VERSION 5.8 ;
DIVIDERCHAR "/" ;
BUSBITCHARS "[]" ;

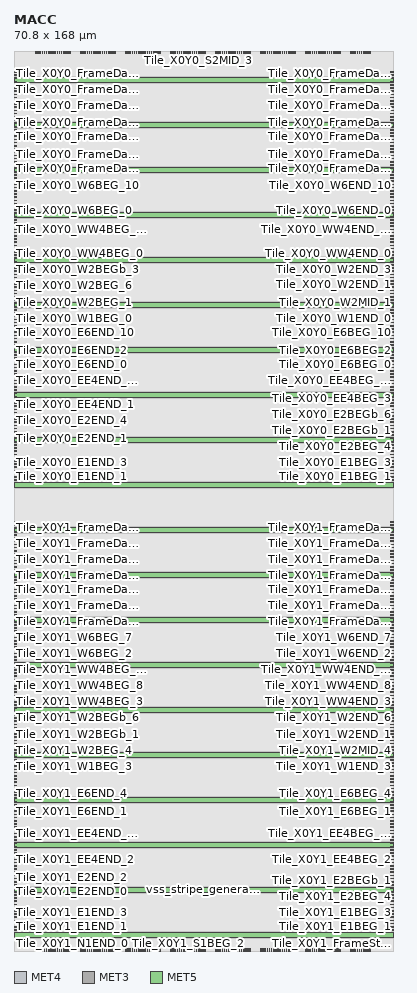
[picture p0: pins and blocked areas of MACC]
MACRO MACC
  CLASS BLOCK ;
  FOREIGN MACC ;
  ORIGIN 0.0 0.0 ;
  SIZE 70.800 BY 168.000 ;
  SYMMETRY X Y ;
  PIN Tile_X0Y0_N_GBUF_BEG_0
    DIRECTION OUTPUT ;
    USE SIGNAL ;
    PORT
      LAYER MET4 ;
        RECT 4.050 167.450 4.150 168.000 ;
    END
  END Tile_X0Y0_N_GBUF_BEG_0
  PIN Tile_X0Y0_N_GBUF_BEG_1
    DIRECTION OUTPUT ;
    USE SIGNAL ;
    PORT
      LAYER MET4 ;
        RECT 4.450 167.450 4.550 168.000 ;
    END
  END Tile_X0Y0_N_GBUF_BEG_1
  PIN Tile_X0Y0_N_GBUF_BEG_2
    DIRECTION OUTPUT ;
    USE SIGNAL ;
    PORT
      LAYER MET4 ;
        RECT 4.850 167.450 4.950 168.000 ;
    END
  END Tile_X0Y0_N_GBUF_BEG_2
  PIN Tile_X0Y0_N_GBUF_BEG_3
    DIRECTION OUTPUT ;
    USE SIGNAL ;
    PORT
      LAYER MET4 ;
        RECT 5.250 167.450 5.350 168.000 ;
    END
  END Tile_X0Y0_N_GBUF_BEG_3
  PIN Tile_X0Y0_N1BEG_0
    DIRECTION OUTPUT ;
    USE SIGNAL ;
    PORT
      LAYER MET4 ;
        RECT 5.650 167.450 5.750 168.000 ;
    END
  END Tile_X0Y0_N1BEG_0
  PIN Tile_X0Y0_N1BEG_1
    DIRECTION OUTPUT ;
    USE SIGNAL ;
    PORT
      LAYER MET4 ;
        RECT 6.050 167.450 6.150 168.000 ;
    END
  END Tile_X0Y0_N1BEG_1
  PIN Tile_X0Y0_N1BEG_2
    DIRECTION OUTPUT ;
    USE SIGNAL ;
    PORT
      LAYER MET4 ;
        RECT 6.450 167.450 6.550 168.000 ;
    END
  END Tile_X0Y0_N1BEG_2
  PIN Tile_X0Y0_N1BEG_3
    DIRECTION OUTPUT ;
    USE SIGNAL ;
    PORT
      LAYER MET4 ;
        RECT 6.850 167.450 6.950 168.000 ;
    END
  END Tile_X0Y0_N1BEG_3
  PIN Tile_X0Y0_N2BEG_0
    DIRECTION OUTPUT ;
    USE SIGNAL ;
    PORT
      LAYER MET4 ;
        RECT 7.250 167.450 7.350 168.000 ;
    END
  END Tile_X0Y0_N2BEG_0
  PIN Tile_X0Y0_N2BEG_1
    DIRECTION OUTPUT ;
    USE SIGNAL ;
    PORT
      LAYER MET4 ;
        RECT 7.650 167.450 7.750 168.000 ;
    END
  END Tile_X0Y0_N2BEG_1
  PIN Tile_X0Y0_N2BEG_2
    DIRECTION OUTPUT ;
    USE SIGNAL ;
    PORT
      LAYER MET4 ;
        RECT 8.050 167.450 8.150 168.000 ;
    END
  END Tile_X0Y0_N2BEG_2
  PIN Tile_X0Y0_N2BEG_3
    DIRECTION OUTPUT ;
    USE SIGNAL ;
    PORT
      LAYER MET4 ;
        RECT 8.450 167.450 8.550 168.000 ;
    END
  END Tile_X0Y0_N2BEG_3
  PIN Tile_X0Y0_N2BEG_4
    DIRECTION OUTPUT ;
    USE SIGNAL ;
    PORT
      LAYER MET4 ;
        RECT 8.850 167.450 8.950 168.000 ;
    END
  END Tile_X0Y0_N2BEG_4
  PIN Tile_X0Y0_N2BEG_5
    DIRECTION OUTPUT ;
    USE SIGNAL ;
    PORT
      LAYER MET4 ;
        RECT 9.250 167.450 9.350 168.000 ;
    END
  END Tile_X0Y0_N2BEG_5
  PIN Tile_X0Y0_N2BEG_6
    DIRECTION OUTPUT ;
    USE SIGNAL ;
    PORT
      LAYER MET4 ;
        RECT 9.650 167.450 9.750 168.000 ;
    END
  END Tile_X0Y0_N2BEG_6
  PIN Tile_X0Y0_N2BEG_7
    DIRECTION OUTPUT ;
    USE SIGNAL ;
    PORT
      LAYER MET4 ;
        RECT 10.050 167.450 10.150 168.000 ;
    END
  END Tile_X0Y0_N2BEG_7
  PIN Tile_X0Y0_N2BEGb_0
    DIRECTION OUTPUT ;
    USE SIGNAL ;
    PORT
      LAYER MET4 ;
        RECT 10.450 167.450 10.550 168.000 ;
    END
  END Tile_X0Y0_N2BEGb_0
  PIN Tile_X0Y0_N2BEGb_1
    DIRECTION OUTPUT ;
    USE SIGNAL ;
    PORT
      LAYER MET4 ;
        RECT 12.450 167.450 12.550 168.000 ;
    END
  END Tile_X0Y0_N2BEGb_1
  PIN Tile_X0Y0_N2BEGb_2
    DIRECTION OUTPUT ;
    USE SIGNAL ;
    PORT
      LAYER MET4 ;
        RECT 12.850 167.450 12.950 168.000 ;
    END
  END Tile_X0Y0_N2BEGb_2
  PIN Tile_X0Y0_N2BEGb_3
    DIRECTION OUTPUT ;
    USE SIGNAL ;
    PORT
      LAYER MET4 ;
        RECT 13.250 167.450 13.350 168.000 ;
    END
  END Tile_X0Y0_N2BEGb_3
  PIN Tile_X0Y0_N2BEGb_4
    DIRECTION OUTPUT ;
    USE SIGNAL ;
    PORT
      LAYER MET4 ;
        RECT 13.650 167.450 13.750 168.000 ;
    END
  END Tile_X0Y0_N2BEGb_4
  PIN Tile_X0Y0_N2BEGb_5
    DIRECTION OUTPUT ;
    USE SIGNAL ;
    PORT
      LAYER MET4 ;
        RECT 14.050 167.450 14.150 168.000 ;
    END
  END Tile_X0Y0_N2BEGb_5
  PIN Tile_X0Y0_N2BEGb_6
    DIRECTION OUTPUT ;
    USE SIGNAL ;
    PORT
      LAYER MET4 ;
        RECT 14.450 167.450 14.550 168.000 ;
    END
  END Tile_X0Y0_N2BEGb_6
  PIN Tile_X0Y0_N2BEGb_7
    DIRECTION OUTPUT ;
    USE SIGNAL ;
    PORT
      LAYER MET4 ;
        RECT 14.850 167.450 14.950 168.000 ;
    END
  END Tile_X0Y0_N2BEGb_7
  PIN Tile_X0Y0_N4BEG_0
    DIRECTION OUTPUT ;
    USE SIGNAL ;
    PORT
      LAYER MET4 ;
        RECT 15.250 167.450 15.350 168.000 ;
    END
  END Tile_X0Y0_N4BEG_0
  PIN Tile_X0Y0_N4BEG_1
    DIRECTION OUTPUT ;
    USE SIGNAL ;
    PORT
      LAYER MET4 ;
        RECT 15.650 167.450 15.750 168.000 ;
    END
  END Tile_X0Y0_N4BEG_1
  PIN Tile_X0Y0_N4BEG_2
    DIRECTION OUTPUT ;
    USE SIGNAL ;
    PORT
      LAYER MET4 ;
        RECT 16.050 167.450 16.150 168.000 ;
    END
  END Tile_X0Y0_N4BEG_2
  PIN Tile_X0Y0_N4BEG_3
    DIRECTION OUTPUT ;
    USE SIGNAL ;
    PORT
      LAYER MET4 ;
        RECT 16.450 167.450 16.550 168.000 ;
    END
  END Tile_X0Y0_N4BEG_3
  PIN Tile_X0Y0_N4BEG_4
    DIRECTION OUTPUT ;
    USE SIGNAL ;
    PORT
      LAYER MET4 ;
        RECT 16.850 167.450 16.950 168.000 ;
    END
  END Tile_X0Y0_N4BEG_4
  PIN Tile_X0Y0_N4BEG_5
    DIRECTION OUTPUT ;
    USE SIGNAL ;
    PORT
      LAYER MET4 ;
        RECT 17.250 167.450 17.350 168.000 ;
    END
  END Tile_X0Y0_N4BEG_5
  PIN Tile_X0Y0_N4BEG_6
    DIRECTION OUTPUT ;
    USE SIGNAL ;
    PORT
      LAYER MET4 ;
        RECT 17.650 167.450 17.750 168.000 ;
    END
  END Tile_X0Y0_N4BEG_6
  PIN Tile_X0Y0_N4BEG_7
    DIRECTION OUTPUT ;
    USE SIGNAL ;
    PORT
      LAYER MET4 ;
        RECT 18.050 167.450 18.150 168.000 ;
    END
  END Tile_X0Y0_N4BEG_7
  PIN Tile_X0Y0_N4BEG_8
    DIRECTION OUTPUT ;
    USE SIGNAL ;
    PORT
      LAYER MET4 ;
        RECT 18.450 167.450 18.550 168.000 ;
    END
  END Tile_X0Y0_N4BEG_8
  PIN Tile_X0Y0_N4BEG_9
    DIRECTION OUTPUT ;
    USE SIGNAL ;
    PORT
      LAYER MET4 ;
        RECT 18.850 167.450 18.950 168.000 ;
    END
  END Tile_X0Y0_N4BEG_9
  PIN Tile_X0Y0_N4BEG_10
    DIRECTION OUTPUT ;
    USE SIGNAL ;
    PORT
      LAYER MET4 ;
        RECT 20.850 167.450 20.950 168.000 ;
    END
  END Tile_X0Y0_N4BEG_10
  PIN Tile_X0Y0_N4BEG_11
    DIRECTION OUTPUT ;
    USE SIGNAL ;
    PORT
      LAYER MET4 ;
        RECT 21.250 167.450 21.350 168.000 ;
    END
  END Tile_X0Y0_N4BEG_11
  PIN Tile_X0Y0_N4BEG_12
    DIRECTION OUTPUT ;
    USE SIGNAL ;
    PORT
      LAYER MET4 ;
        RECT 21.650 167.450 21.750 168.000 ;
    END
  END Tile_X0Y0_N4BEG_12
  PIN Tile_X0Y0_N4BEG_13
    DIRECTION OUTPUT ;
    USE SIGNAL ;
    PORT
      LAYER MET4 ;
        RECT 22.050 167.450 22.150 168.000 ;
    END
  END Tile_X0Y0_N4BEG_13
  PIN Tile_X0Y0_N4BEG_14
    DIRECTION OUTPUT ;
    USE SIGNAL ;
    PORT
      LAYER MET4 ;
        RECT 22.450 167.450 22.550 168.000 ;
    END
  END Tile_X0Y0_N4BEG_14
  PIN Tile_X0Y0_N4BEG_15
    DIRECTION OUTPUT ;
    USE SIGNAL ;
    PORT
      LAYER MET4 ;
        RECT 22.850 167.450 22.950 168.000 ;
    END
  END Tile_X0Y0_N4BEG_15
  PIN Tile_X0Y0_NN4BEG_0
    DIRECTION OUTPUT ;
    USE SIGNAL ;
    PORT
      LAYER MET4 ;
        RECT 23.250 167.450 23.350 168.000 ;
    END
  END Tile_X0Y0_NN4BEG_0
  PIN Tile_X0Y0_NN4BEG_1
    DIRECTION OUTPUT ;
    USE SIGNAL ;
    PORT
      LAYER MET4 ;
        RECT 23.650 167.450 23.750 168.000 ;
    END
  END Tile_X0Y0_NN4BEG_1
  PIN Tile_X0Y0_NN4BEG_2
    DIRECTION OUTPUT ;
    USE SIGNAL ;
    PORT
      LAYER MET4 ;
        RECT 24.050 167.450 24.150 168.000 ;
    END
  END Tile_X0Y0_NN4BEG_2
  PIN Tile_X0Y0_NN4BEG_3
    DIRECTION OUTPUT ;
    USE SIGNAL ;
    PORT
      LAYER MET4 ;
        RECT 24.450 167.450 24.550 168.000 ;
    END
  END Tile_X0Y0_NN4BEG_3
  PIN Tile_X0Y0_NN4BEG_4
    DIRECTION OUTPUT ;
    USE SIGNAL ;
    PORT
      LAYER MET4 ;
        RECT 24.850 167.450 24.950 168.000 ;
    END
  END Tile_X0Y0_NN4BEG_4
  PIN Tile_X0Y0_NN4BEG_5
    DIRECTION OUTPUT ;
    USE SIGNAL ;
    PORT
      LAYER MET4 ;
        RECT 25.250 167.450 25.350 168.000 ;
    END
  END Tile_X0Y0_NN4BEG_5
  PIN Tile_X0Y0_NN4BEG_6
    DIRECTION OUTPUT ;
    USE SIGNAL ;
    PORT
      LAYER MET4 ;
        RECT 25.650 167.450 25.750 168.000 ;
    END
  END Tile_X0Y0_NN4BEG_6
  PIN Tile_X0Y0_NN4BEG_7
    DIRECTION OUTPUT ;
    USE SIGNAL ;
    PORT
      LAYER MET4 ;
        RECT 26.050 167.450 26.150 168.000 ;
    END
  END Tile_X0Y0_NN4BEG_7
  PIN Tile_X0Y0_NN4BEG_8
    DIRECTION OUTPUT ;
    USE SIGNAL ;
    PORT
      LAYER MET4 ;
        RECT 26.450 167.450 26.550 168.000 ;
    END
  END Tile_X0Y0_NN4BEG_8
  PIN Tile_X0Y0_NN4BEG_9
    DIRECTION OUTPUT ;
    USE SIGNAL ;
    PORT
      LAYER MET4 ;
        RECT 26.850 167.450 26.950 168.000 ;
    END
  END Tile_X0Y0_NN4BEG_9
  PIN Tile_X0Y0_NN4BEG_10
    DIRECTION OUTPUT ;
    USE SIGNAL ;
    PORT
      LAYER MET4 ;
        RECT 27.250 167.450 27.350 168.000 ;
    END
  END Tile_X0Y0_NN4BEG_10
  PIN Tile_X0Y0_NN4BEG_11
    DIRECTION OUTPUT ;
    USE SIGNAL ;
    PORT
      LAYER MET4 ;
        RECT 29.250 167.450 29.350 168.000 ;
    END
  END Tile_X0Y0_NN4BEG_11
  PIN Tile_X0Y0_NN4BEG_12
    DIRECTION OUTPUT ;
    USE SIGNAL ;
    PORT
      LAYER MET4 ;
        RECT 29.650 167.450 29.750 168.000 ;
    END
  END Tile_X0Y0_NN4BEG_12
  PIN Tile_X0Y0_NN4BEG_13
    DIRECTION OUTPUT ;
    USE SIGNAL ;
    PORT
      LAYER MET4 ;
        RECT 30.050 167.450 30.150 168.000 ;
    END
  END Tile_X0Y0_NN4BEG_13
  PIN Tile_X0Y0_NN4BEG_14
    DIRECTION OUTPUT ;
    USE SIGNAL ;
    PORT
      LAYER MET4 ;
        RECT 30.450 167.450 30.550 168.000 ;
    END
  END Tile_X0Y0_NN4BEG_14
  PIN Tile_X0Y0_NN4BEG_15
    DIRECTION OUTPUT ;
    USE SIGNAL ;
    PORT
      LAYER MET4 ;
        RECT 30.850 167.450 30.950 168.000 ;
    END
  END Tile_X0Y0_NN4BEG_15
  PIN Tile_X0Y0_S1END_0
    DIRECTION INPUT ;
    USE SIGNAL ;
    PORT
      LAYER MET4 ;
        RECT 31.650 167.450 31.750 168.000 ;
    END
  END Tile_X0Y0_S1END_0
  PIN Tile_X0Y0_S1END_1
    DIRECTION INPUT ;
    USE SIGNAL ;
    PORT
      LAYER MET4 ;
        RECT 32.050 167.450 32.150 168.000 ;
    END
  END Tile_X0Y0_S1END_1
  PIN Tile_X0Y0_S1END_2
    DIRECTION INPUT ;
    USE SIGNAL ;
    PORT
      LAYER MET4 ;
        RECT 32.450 167.450 32.550 168.000 ;
    END
  END Tile_X0Y0_S1END_2
  PIN Tile_X0Y0_S1END_3
    DIRECTION INPUT ;
    USE SIGNAL ;
    PORT
      LAYER MET4 ;
        RECT 32.850 167.450 32.950 168.000 ;
    END
  END Tile_X0Y0_S1END_3
  PIN Tile_X0Y0_S2MID_0
    DIRECTION INPUT ;
    USE SIGNAL ;
    PORT
      LAYER MET4 ;
        RECT 33.250 167.450 33.350 168.000 ;
    END
  END Tile_X0Y0_S2MID_0
  PIN Tile_X0Y0_S2MID_1
    DIRECTION INPUT ;
    USE SIGNAL ;
    PORT
      LAYER MET4 ;
        RECT 33.650 167.450 33.750 168.000 ;
    END
  END Tile_X0Y0_S2MID_1
  PIN Tile_X0Y0_S2MID_2
    DIRECTION INPUT ;
    USE SIGNAL ;
    PORT
      LAYER MET4 ;
        RECT 34.050 167.450 34.150 168.000 ;
    END
  END Tile_X0Y0_S2MID_2
  PIN Tile_X0Y0_S2MID_3
    DIRECTION INPUT ;
    USE SIGNAL ;
    PORT
      LAYER MET4 ;
        RECT 34.450 167.450 34.550 168.000 ;
    END
  END Tile_X0Y0_S2MID_3
  PIN Tile_X0Y0_S2MID_4
    DIRECTION INPUT ;
    USE SIGNAL ;
    PORT
      LAYER MET4 ;
        RECT 34.850 167.450 34.950 168.000 ;
    END
  END Tile_X0Y0_S2MID_4
  PIN Tile_X0Y0_S2MID_5
    DIRECTION INPUT ;
    USE SIGNAL ;
    PORT
      LAYER MET4 ;
        RECT 35.250 167.450 35.350 168.000 ;
    END
  END Tile_X0Y0_S2MID_5
  PIN Tile_X0Y0_S2MID_6
    DIRECTION INPUT ;
    USE SIGNAL ;
    PORT
      LAYER MET4 ;
        RECT 35.650 167.450 35.750 168.000 ;
    END
  END Tile_X0Y0_S2MID_6
  PIN Tile_X0Y0_S2MID_7
    DIRECTION INPUT ;
    USE SIGNAL ;
    PORT
      LAYER MET4 ;
        RECT 37.650 167.450 37.750 168.000 ;
    END
  END Tile_X0Y0_S2MID_7
  PIN Tile_X0Y0_S2END_0
    DIRECTION INPUT ;
    USE SIGNAL ;
    PORT
      LAYER MET4 ;
        RECT 38.050 167.450 38.150 168.000 ;
    END
  END Tile_X0Y0_S2END_0
  PIN Tile_X0Y0_S2END_1
    DIRECTION INPUT ;
    USE SIGNAL ;
    PORT
      LAYER MET4 ;
        RECT 38.450 167.450 38.550 168.000 ;
    END
  END Tile_X0Y0_S2END_1
  PIN Tile_X0Y0_S2END_2
    DIRECTION INPUT ;
    USE SIGNAL ;
    PORT
      LAYER MET4 ;
        RECT 38.850 167.450 38.950 168.000 ;
    END
  END Tile_X0Y0_S2END_2
  PIN Tile_X0Y0_S2END_3
    DIRECTION INPUT ;
    USE SIGNAL ;
    PORT
      LAYER MET4 ;
        RECT 39.250 167.450 39.350 168.000 ;
    END
  END Tile_X0Y0_S2END_3
  PIN Tile_X0Y0_S2END_4
    DIRECTION INPUT ;
    USE SIGNAL ;
    PORT
      LAYER MET4 ;
        RECT 39.650 167.450 39.750 168.000 ;
    END
  END Tile_X0Y0_S2END_4
  PIN Tile_X0Y0_S2END_5
    DIRECTION INPUT ;
    USE SIGNAL ;
    PORT
      LAYER MET4 ;
        RECT 40.050 167.450 40.150 168.000 ;
    END
  END Tile_X0Y0_S2END_5
  PIN Tile_X0Y0_S2END_6
    DIRECTION INPUT ;
    USE SIGNAL ;
    PORT
      LAYER MET4 ;
        RECT 40.450 167.450 40.550 168.000 ;
    END
  END Tile_X0Y0_S2END_6
  PIN Tile_X0Y0_S2END_7
    DIRECTION INPUT ;
    USE SIGNAL ;
    PORT
      LAYER MET4 ;
        RECT 40.850 167.450 40.950 168.000 ;
    END
  END Tile_X0Y0_S2END_7
  PIN Tile_X0Y0_S4END_0
    DIRECTION INPUT ;
    USE SIGNAL ;
    PORT
      LAYER MET4 ;
        RECT 41.250 167.450 41.350 168.000 ;
    END
  END Tile_X0Y0_S4END_0
  PIN Tile_X0Y0_S4END_1
    DIRECTION INPUT ;
    USE SIGNAL ;
    PORT
      LAYER MET4 ;
        RECT 41.650 167.450 41.750 168.000 ;
    END
  END Tile_X0Y0_S4END_1
  PIN Tile_X0Y0_S4END_2
    DIRECTION INPUT ;
    USE SIGNAL ;
    PORT
      LAYER MET4 ;
        RECT 42.050 167.450 42.150 168.000 ;
    END
  END Tile_X0Y0_S4END_2
  PIN Tile_X0Y0_S4END_3
    DIRECTION INPUT ;
    USE SIGNAL ;
    PORT
      LAYER MET4 ;
        RECT 42.450 167.450 42.550 168.000 ;
    END
  END Tile_X0Y0_S4END_3
  PIN Tile_X0Y0_S4END_4
    DIRECTION INPUT ;
    USE SIGNAL ;
    PORT
      LAYER MET4 ;
        RECT 42.850 167.450 42.950 168.000 ;
    END
  END Tile_X0Y0_S4END_4
  PIN Tile_X0Y0_S4END_5
    DIRECTION INPUT ;
    USE SIGNAL ;
    PORT
      LAYER MET4 ;
        RECT 43.250 167.450 43.350 168.000 ;
    END
  END Tile_X0Y0_S4END_5
  PIN Tile_X0Y0_S4END_6
    DIRECTION INPUT ;
    USE SIGNAL ;
    PORT
      LAYER MET4 ;
        RECT 43.650 167.450 43.750 168.000 ;
    END
  END Tile_X0Y0_S4END_6
  PIN Tile_X0Y0_S4END_7
    DIRECTION INPUT ;
    USE SIGNAL ;
    PORT
      LAYER MET4 ;
        RECT 44.050 167.450 44.150 168.000 ;
    END
  END Tile_X0Y0_S4END_7
  PIN Tile_X0Y0_S4END_8
    DIRECTION INPUT ;
    USE SIGNAL ;
    PORT
      LAYER MET4 ;
        RECT 46.050 167.450 46.150 168.000 ;
    END
  END Tile_X0Y0_S4END_8
  PIN Tile_X0Y0_S4END_9
    DIRECTION INPUT ;
    USE SIGNAL ;
    PORT
      LAYER MET4 ;
        RECT 46.450 167.450 46.550 168.000 ;
    END
  END Tile_X0Y0_S4END_9
  PIN Tile_X0Y0_S4END_10
    DIRECTION INPUT ;
    USE SIGNAL ;
    PORT
      LAYER MET4 ;
        RECT 46.850 167.450 46.950 168.000 ;
    END
  END Tile_X0Y0_S4END_10
  PIN Tile_X0Y0_S4END_11
    DIRECTION INPUT ;
    USE SIGNAL ;
    PORT
      LAYER MET4 ;
        RECT 47.250 167.450 47.350 168.000 ;
    END
  END Tile_X0Y0_S4END_11
  PIN Tile_X0Y0_S4END_12
    DIRECTION INPUT ;
    USE SIGNAL ;
    PORT
      LAYER MET4 ;
        RECT 47.650 167.450 47.750 168.000 ;
    END
  END Tile_X0Y0_S4END_12
  PIN Tile_X0Y0_S4END_13
    DIRECTION INPUT ;
    USE SIGNAL ;
    PORT
      LAYER MET4 ;
        RECT 48.050 167.450 48.150 168.000 ;
    END
  END Tile_X0Y0_S4END_13
  PIN Tile_X0Y0_S4END_14
    DIRECTION INPUT ;
    USE SIGNAL ;
    PORT
      LAYER MET4 ;
        RECT 48.450 167.450 48.550 168.000 ;
    END
  END Tile_X0Y0_S4END_14
  PIN Tile_X0Y0_S4END_15
    DIRECTION INPUT ;
    USE SIGNAL ;
    PORT
      LAYER MET4 ;
        RECT 48.850 167.450 48.950 168.000 ;
    END
  END Tile_X0Y0_S4END_15
  PIN Tile_X0Y0_SS4END_0
    DIRECTION INPUT ;
    USE SIGNAL ;
    PORT
      LAYER MET4 ;
        RECT 49.250 167.450 49.350 168.000 ;
    END
  END Tile_X0Y0_SS4END_0
  PIN Tile_X0Y0_SS4END_1
    DIRECTION INPUT ;
    USE SIGNAL ;
    PORT
      LAYER MET4 ;
        RECT 49.650 167.450 49.750 168.000 ;
    END
  END Tile_X0Y0_SS4END_1
  PIN Tile_X0Y0_SS4END_2
    DIRECTION INPUT ;
    USE SIGNAL ;
    PORT
      LAYER MET4 ;
        RECT 50.050 167.450 50.150 168.000 ;
    END
  END Tile_X0Y0_SS4END_2
  PIN Tile_X0Y0_SS4END_3
    DIRECTION INPUT ;
    USE SIGNAL ;
    PORT
      LAYER MET4 ;
        RECT 50.450 167.450 50.550 168.000 ;
    END
  END Tile_X0Y0_SS4END_3
  PIN Tile_X0Y0_SS4END_4
    DIRECTION INPUT ;
    USE SIGNAL ;
    PORT
      LAYER MET4 ;
        RECT 50.850 167.450 50.950 168.000 ;
    END
  END Tile_X0Y0_SS4END_4
  PIN Tile_X0Y0_SS4END_5
    DIRECTION INPUT ;
    USE SIGNAL ;
    PORT
      LAYER MET4 ;
        RECT 51.250 167.450 51.350 168.000 ;
    END
  END Tile_X0Y0_SS4END_5
  PIN Tile_X0Y0_SS4END_6
    DIRECTION INPUT ;
    USE SIGNAL ;
    PORT
      LAYER MET4 ;
        RECT 51.650 167.450 51.750 168.000 ;
    END
  END Tile_X0Y0_SS4END_6
  PIN Tile_X0Y0_SS4END_7
    DIRECTION INPUT ;
    USE SIGNAL ;
    PORT
      LAYER MET4 ;
        RECT 52.050 167.450 52.150 168.000 ;
    END
  END Tile_X0Y0_SS4END_7
  PIN Tile_X0Y0_SS4END_8
    DIRECTION INPUT ;
    USE SIGNAL ;
    PORT
      LAYER MET4 ;
        RECT 52.450 167.450 52.550 168.000 ;
    END
  END Tile_X0Y0_SS4END_8
  PIN Tile_X0Y0_SS4END_9
    DIRECTION INPUT ;
    USE SIGNAL ;
    PORT
      LAYER MET4 ;
        RECT 54.450 167.450 54.550 168.000 ;
    END
  END Tile_X0Y0_SS4END_9
  PIN Tile_X0Y0_SS4END_10
    DIRECTION INPUT ;
    USE SIGNAL ;
    PORT
      LAYER MET4 ;
        RECT 54.850 167.450 54.950 168.000 ;
    END
  END Tile_X0Y0_SS4END_10
  PIN Tile_X0Y0_SS4END_11
    DIRECTION INPUT ;
    USE SIGNAL ;
    PORT
      LAYER MET4 ;
        RECT 55.250 167.450 55.350 168.000 ;
    END
  END Tile_X0Y0_SS4END_11
  PIN Tile_X0Y0_SS4END_12
    DIRECTION INPUT ;
    USE SIGNAL ;
    PORT
      LAYER MET4 ;
        RECT 55.650 167.450 55.750 168.000 ;
    END
  END Tile_X0Y0_SS4END_12
  PIN Tile_X0Y0_SS4END_13
    DIRECTION INPUT ;
    USE SIGNAL ;
    PORT
      LAYER MET4 ;
        RECT 56.050 167.450 56.150 168.000 ;
    END
  END Tile_X0Y0_SS4END_13
  PIN Tile_X0Y0_SS4END_14
    DIRECTION INPUT ;
    USE SIGNAL ;
    PORT
      LAYER MET4 ;
        RECT 56.450 167.450 56.550 168.000 ;
    END
  END Tile_X0Y0_SS4END_14
  PIN Tile_X0Y0_SS4END_15
    DIRECTION INPUT ;
    USE SIGNAL ;
    PORT
      LAYER MET4 ;
        RECT 56.850 167.450 56.950 168.000 ;
    END
  END Tile_X0Y0_SS4END_15
  PIN Tile_X0Y0_CO_0
    DIRECTION OUTPUT ;
    USE SIGNAL ;
    PORT
      LAYER MET4 ;
        RECT 31.250 167.450 31.350 168.000 ;
    END
  END Tile_X0Y0_CO_0
  PIN Tile_X0Y0_E1BEG_0
    DIRECTION OUTPUT ;
    USE SIGNAL ;
    PORT
      LAYER MET3 ;
        RECT 70.250 87.850 70.800 87.950 ;
    END
  END Tile_X0Y0_E1BEG_0
  PIN Tile_X0Y0_E1BEG_1
    DIRECTION OUTPUT ;
    USE SIGNAL ;
    PORT
      LAYER MET3 ;
        RECT 70.250 88.450 70.800 88.550 ;
    END
  END Tile_X0Y0_E1BEG_1
  PIN Tile_X0Y0_E1BEG_2
    DIRECTION OUTPUT ;
    USE SIGNAL ;
    PORT
      LAYER MET3 ;
        RECT 70.250 89.050 70.800 89.150 ;
    END
  END Tile_X0Y0_E1BEG_2
  PIN Tile_X0Y0_E1BEG_3
    DIRECTION OUTPUT ;
    USE SIGNAL ;
    PORT
      LAYER MET3 ;
        RECT 70.250 89.650 70.800 89.750 ;
    END
  END Tile_X0Y0_E1BEG_3
  PIN Tile_X0Y0_E2BEG_0
    DIRECTION OUTPUT ;
    USE SIGNAL ;
    PORT
      LAYER MET3 ;
        RECT 70.250 90.250 70.800 90.350 ;
    END
  END Tile_X0Y0_E2BEG_0
  PIN Tile_X0Y0_E2BEG_1
    DIRECTION OUTPUT ;
    USE SIGNAL ;
    PORT
      LAYER MET3 ;
        RECT 70.250 90.850 70.800 90.950 ;
    END
  END Tile_X0Y0_E2BEG_1
  PIN Tile_X0Y0_E2BEG_2
    DIRECTION OUTPUT ;
    USE SIGNAL ;
    PORT
      LAYER MET3 ;
        RECT 70.250 91.450 70.800 91.550 ;
    END
  END Tile_X0Y0_E2BEG_2
  PIN Tile_X0Y0_E2BEG_3
    DIRECTION OUTPUT ;
    USE SIGNAL ;
    PORT
      LAYER MET3 ;
        RECT 70.250 92.050 70.800 92.150 ;
    END
  END Tile_X0Y0_E2BEG_3
  PIN Tile_X0Y0_E2BEG_4
    DIRECTION OUTPUT ;
    USE SIGNAL ;
    PORT
      LAYER MET3 ;
        RECT 70.250 92.650 70.800 92.750 ;
    END
  END Tile_X0Y0_E2BEG_4
  PIN Tile_X0Y0_E2BEG_5
    DIRECTION OUTPUT ;
    USE SIGNAL ;
    PORT
      LAYER MET3 ;
        RECT 70.250 93.250 70.800 93.350 ;
    END
  END Tile_X0Y0_E2BEG_5
  PIN Tile_X0Y0_E2BEG_6
    DIRECTION OUTPUT ;
    USE SIGNAL ;
    PORT
      LAYER MET3 ;
        RECT 70.250 93.850 70.800 93.950 ;
    END
  END Tile_X0Y0_E2BEG_6
  PIN Tile_X0Y0_E2BEG_7
    DIRECTION OUTPUT ;
    USE SIGNAL ;
    PORT
      LAYER MET3 ;
        RECT 70.250 94.450 70.800 94.550 ;
    END
  END Tile_X0Y0_E2BEG_7
  PIN Tile_X0Y0_E2BEGb_0
    DIRECTION OUTPUT ;
    USE SIGNAL ;
    PORT
      LAYER MET3 ;
        RECT 70.250 95.050 70.800 95.150 ;
    END
  END Tile_X0Y0_E2BEGb_0
  PIN Tile_X0Y0_E2BEGb_1
    DIRECTION OUTPUT ;
    USE SIGNAL ;
    PORT
      LAYER MET3 ;
        RECT 70.250 95.650 70.800 95.750 ;
    END
  END Tile_X0Y0_E2BEGb_1
  PIN Tile_X0Y0_E2BEGb_2
    DIRECTION OUTPUT ;
    USE SIGNAL ;
    PORT
      LAYER MET3 ;
        RECT 70.250 96.250 70.800 96.350 ;
    END
  END Tile_X0Y0_E2BEGb_2
  PIN Tile_X0Y0_E2BEGb_3
    DIRECTION OUTPUT ;
    USE SIGNAL ;
    PORT
      LAYER MET3 ;
        RECT 70.250 96.850 70.800 96.950 ;
    END
  END Tile_X0Y0_E2BEGb_3
  PIN Tile_X0Y0_E2BEGb_4
    DIRECTION OUTPUT ;
    USE SIGNAL ;
    PORT
      LAYER MET3 ;
        RECT 70.250 97.450 70.800 97.550 ;
    END
  END Tile_X0Y0_E2BEGb_4
  PIN Tile_X0Y0_E2BEGb_5
    DIRECTION OUTPUT ;
    USE SIGNAL ;
    PORT
      LAYER MET3 ;
        RECT 70.250 98.050 70.800 98.150 ;
    END
  END Tile_X0Y0_E2BEGb_5
  PIN Tile_X0Y0_E2BEGb_6
    DIRECTION OUTPUT ;
    USE SIGNAL ;
    PORT
      LAYER MET3 ;
        RECT 70.250 98.650 70.800 98.750 ;
    END
  END Tile_X0Y0_E2BEGb_6
  PIN Tile_X0Y0_E2BEGb_7
    DIRECTION OUTPUT ;
    USE SIGNAL ;
    PORT
      LAYER MET3 ;
        RECT 70.250 99.250 70.800 99.350 ;
    END
  END Tile_X0Y0_E2BEGb_7
  PIN Tile_X0Y0_EE4BEG_0
    DIRECTION OUTPUT ;
    USE SIGNAL ;
    PORT
      LAYER MET3 ;
        RECT 70.250 99.850 70.800 99.950 ;
    END
  END Tile_X0Y0_EE4BEG_0
  PIN Tile_X0Y0_EE4BEG_1
    DIRECTION OUTPUT ;
    USE SIGNAL ;
    PORT
      LAYER MET3 ;
        RECT 70.250 100.450 70.800 100.550 ;
    END
  END Tile_X0Y0_EE4BEG_1
  PIN Tile_X0Y0_EE4BEG_2
    DIRECTION OUTPUT ;
    USE SIGNAL ;
    PORT
      LAYER MET3 ;
        RECT 70.250 101.050 70.800 101.150 ;
    END
  END Tile_X0Y0_EE4BEG_2
  PIN Tile_X0Y0_EE4BEG_3
    DIRECTION OUTPUT ;
    USE SIGNAL ;
    PORT
      LAYER MET3 ;
        RECT 70.250 101.650 70.800 101.750 ;
    END
  END Tile_X0Y0_EE4BEG_3
  PIN Tile_X0Y0_EE4BEG_4
    DIRECTION OUTPUT ;
    USE SIGNAL ;
    PORT
      LAYER MET3 ;
        RECT 70.250 102.250 70.800 102.350 ;
    END
  END Tile_X0Y0_EE4BEG_4
  PIN Tile_X0Y0_EE4BEG_5
    DIRECTION OUTPUT ;
    USE SIGNAL ;
    PORT
      LAYER MET3 ;
        RECT 70.250 102.850 70.800 102.950 ;
    END
  END Tile_X0Y0_EE4BEG_5
  PIN Tile_X0Y0_EE4BEG_6
    DIRECTION OUTPUT ;
    USE SIGNAL ;
    PORT
      LAYER MET3 ;
        RECT 70.250 103.450 70.800 103.550 ;
    END
  END Tile_X0Y0_EE4BEG_6
  PIN Tile_X0Y0_EE4BEG_7
    DIRECTION OUTPUT ;
    USE SIGNAL ;
    PORT
      LAYER MET3 ;
        RECT 70.250 104.050 70.800 104.150 ;
    END
  END Tile_X0Y0_EE4BEG_7
  PIN Tile_X0Y0_EE4BEG_8
    DIRECTION OUTPUT ;
    USE SIGNAL ;
    PORT
      LAYER MET3 ;
        RECT 70.250 104.650 70.800 104.750 ;
    END
  END Tile_X0Y0_EE4BEG_8
  PIN Tile_X0Y0_EE4BEG_9
    DIRECTION OUTPUT ;
    USE SIGNAL ;
    PORT
      LAYER MET3 ;
        RECT 70.250 105.250 70.800 105.350 ;
    END
  END Tile_X0Y0_EE4BEG_9
  PIN Tile_X0Y0_EE4BEG_10
    DIRECTION OUTPUT ;
    USE SIGNAL ;
    PORT
      LAYER MET3 ;
        RECT 70.250 105.850 70.800 105.950 ;
    END
  END Tile_X0Y0_EE4BEG_10
  PIN Tile_X0Y0_EE4BEG_11
    DIRECTION OUTPUT ;
    USE SIGNAL ;
    PORT
      LAYER MET3 ;
        RECT 70.250 106.450 70.800 106.550 ;
    END
  END Tile_X0Y0_EE4BEG_11
  PIN Tile_X0Y0_EE4BEG_12
    DIRECTION OUTPUT ;
    USE SIGNAL ;
    PORT
      LAYER MET3 ;
        RECT 70.250 107.050 70.800 107.150 ;
    END
  END Tile_X0Y0_EE4BEG_12
  PIN Tile_X0Y0_EE4BEG_13
    DIRECTION OUTPUT ;
    USE SIGNAL ;
    PORT
      LAYER MET3 ;
        RECT 70.250 107.650 70.800 107.750 ;
    END
  END Tile_X0Y0_EE4BEG_13
  PIN Tile_X0Y0_EE4BEG_14
    DIRECTION OUTPUT ;
    USE SIGNAL ;
    PORT
      LAYER MET3 ;
        RECT 70.250 108.250 70.800 108.350 ;
    END
  END Tile_X0Y0_EE4BEG_14
  PIN Tile_X0Y0_EE4BEG_15
    DIRECTION OUTPUT ;
    USE SIGNAL ;
    PORT
      LAYER MET3 ;
        RECT 70.250 108.850 70.800 108.950 ;
    END
  END Tile_X0Y0_EE4BEG_15
  PIN Tile_X0Y0_E6BEG_0
    DIRECTION OUTPUT ;
    USE SIGNAL ;
    PORT
      LAYER MET3 ;
        RECT 70.250 109.450 70.800 109.550 ;
    END
  END Tile_X0Y0_E6BEG_0
  PIN Tile_X0Y0_E6BEG_1
    DIRECTION OUTPUT ;
    USE SIGNAL ;
    PORT
      LAYER MET3 ;
        RECT 70.250 110.050 70.800 110.150 ;
    END
  END Tile_X0Y0_E6BEG_1
  PIN Tile_X0Y0_E6BEG_2
    DIRECTION OUTPUT ;
    USE SIGNAL ;
    PORT
      LAYER MET3 ;
        RECT 70.250 110.650 70.800 110.750 ;
    END
  END Tile_X0Y0_E6BEG_2
  PIN Tile_X0Y0_E6BEG_3
    DIRECTION OUTPUT ;
    USE SIGNAL ;
    PORT
      LAYER MET3 ;
        RECT 70.250 111.250 70.800 111.350 ;
    END
  END Tile_X0Y0_E6BEG_3
  PIN Tile_X0Y0_E6BEG_4
    DIRECTION OUTPUT ;
    USE SIGNAL ;
    PORT
      LAYER MET3 ;
        RECT 70.250 111.850 70.800 111.950 ;
    END
  END Tile_X0Y0_E6BEG_4
  PIN Tile_X0Y0_E6BEG_5
    DIRECTION OUTPUT ;
    USE SIGNAL ;
    PORT
      LAYER MET3 ;
        RECT 70.250 112.450 70.800 112.550 ;
    END
  END Tile_X0Y0_E6BEG_5
  PIN Tile_X0Y0_E6BEG_6
    DIRECTION OUTPUT ;
    USE SIGNAL ;
    PORT
      LAYER MET3 ;
        RECT 70.250 113.050 70.800 113.150 ;
    END
  END Tile_X0Y0_E6BEG_6
  PIN Tile_X0Y0_E6BEG_7
    DIRECTION OUTPUT ;
    USE SIGNAL ;
    PORT
      LAYER MET3 ;
        RECT 70.250 113.650 70.800 113.750 ;
    END
  END Tile_X0Y0_E6BEG_7
  PIN Tile_X0Y0_E6BEG_8
    DIRECTION OUTPUT ;
    USE SIGNAL ;
    PORT
      LAYER MET3 ;
        RECT 70.250 114.250 70.800 114.350 ;
    END
  END Tile_X0Y0_E6BEG_8
  PIN Tile_X0Y0_E6BEG_9
    DIRECTION OUTPUT ;
    USE SIGNAL ;
    PORT
      LAYER MET3 ;
        RECT 70.250 114.850 70.800 114.950 ;
    END
  END Tile_X0Y0_E6BEG_9
  PIN Tile_X0Y0_E6BEG_10
    DIRECTION OUTPUT ;
    USE SIGNAL ;
    PORT
      LAYER MET3 ;
        RECT 70.250 115.450 70.800 115.550 ;
    END
  END Tile_X0Y0_E6BEG_10
  PIN Tile_X0Y0_E6BEG_11
    DIRECTION OUTPUT ;
    USE SIGNAL ;
    PORT
      LAYER MET3 ;
        RECT 70.250 116.050 70.800 116.150 ;
    END
  END Tile_X0Y0_E6BEG_11
  PIN Tile_X0Y0_W1END_0
    DIRECTION INPUT ;
    USE SIGNAL ;
    PORT
      LAYER MET3 ;
        RECT 70.250 116.650 70.800 116.750 ;
    END
  END Tile_X0Y0_W1END_0
  PIN Tile_X0Y0_W1END_1
    DIRECTION INPUT ;
    USE SIGNAL ;
    PORT
      LAYER MET3 ;
        RECT 70.250 117.250 70.800 117.350 ;
    END
  END Tile_X0Y0_W1END_1
  PIN Tile_X0Y0_W1END_2
    DIRECTION INPUT ;
    USE SIGNAL ;
    PORT
      LAYER MET3 ;
        RECT 70.250 117.850 70.800 117.950 ;
    END
  END Tile_X0Y0_W1END_2
  PIN Tile_X0Y0_W1END_3
    DIRECTION INPUT ;
    USE SIGNAL ;
    PORT
      LAYER MET3 ;
        RECT 70.250 118.450 70.800 118.550 ;
    END
  END Tile_X0Y0_W1END_3
  PIN Tile_X0Y0_W2MID_0
    DIRECTION INPUT ;
    USE SIGNAL ;
    PORT
      LAYER MET3 ;
        RECT 70.250 119.050 70.800 119.150 ;
    END
  END Tile_X0Y0_W2MID_0
  PIN Tile_X0Y0_W2MID_1
    DIRECTION INPUT ;
    USE SIGNAL ;
    PORT
      LAYER MET3 ;
        RECT 70.250 119.650 70.800 119.750 ;
    END
  END Tile_X0Y0_W2MID_1
  PIN Tile_X0Y0_W2MID_2
    DIRECTION INPUT ;
    USE SIGNAL ;
    PORT
      LAYER MET3 ;
        RECT 70.250 120.250 70.800 120.350 ;
    END
  END Tile_X0Y0_W2MID_2
  PIN Tile_X0Y0_W2MID_3
    DIRECTION INPUT ;
    USE SIGNAL ;
    PORT
      LAYER MET3 ;
        RECT 70.250 120.850 70.800 120.950 ;
    END
  END Tile_X0Y0_W2MID_3
  PIN Tile_X0Y0_W2MID_4
    DIRECTION INPUT ;
    USE SIGNAL ;
    PORT
      LAYER MET3 ;
        RECT 70.250 121.450 70.800 121.550 ;
    END
  END Tile_X0Y0_W2MID_4
  PIN Tile_X0Y0_W2MID_5
    DIRECTION INPUT ;
    USE SIGNAL ;
    PORT
      LAYER MET3 ;
        RECT 70.250 122.050 70.800 122.150 ;
    END
  END Tile_X0Y0_W2MID_5
  PIN Tile_X0Y0_W2MID_6
    DIRECTION INPUT ;
    USE SIGNAL ;
    PORT
      LAYER MET3 ;
        RECT 70.250 122.650 70.800 122.750 ;
    END
  END Tile_X0Y0_W2MID_6
  PIN Tile_X0Y0_W2MID_7
    DIRECTION INPUT ;
    USE SIGNAL ;
    PORT
      LAYER MET3 ;
        RECT 70.250 123.250 70.800 123.350 ;
    END
  END Tile_X0Y0_W2MID_7
  PIN Tile_X0Y0_W2END_0
    DIRECTION INPUT ;
    USE SIGNAL ;
    PORT
      LAYER MET3 ;
        RECT 70.250 123.850 70.800 123.950 ;
    END
  END Tile_X0Y0_W2END_0
  PIN Tile_X0Y0_W2END_1
    DIRECTION INPUT ;
    USE SIGNAL ;
    PORT
      LAYER MET3 ;
        RECT 70.250 124.450 70.800 124.550 ;
    END
  END Tile_X0Y0_W2END_1
  PIN Tile_X0Y0_W2END_2
    DIRECTION INPUT ;
    USE SIGNAL ;
    PORT
      LAYER MET3 ;
        RECT 70.250 125.050 70.800 125.150 ;
    END
  END Tile_X0Y0_W2END_2
  PIN Tile_X0Y0_W2END_3
    DIRECTION INPUT ;
    USE SIGNAL ;
    PORT
      LAYER MET3 ;
        RECT 70.250 125.650 70.800 125.750 ;
    END
  END Tile_X0Y0_W2END_3
  PIN Tile_X0Y0_W2END_4
    DIRECTION INPUT ;
    USE SIGNAL ;
    PORT
      LAYER MET3 ;
        RECT 70.250 126.250 70.800 126.350 ;
    END
  END Tile_X0Y0_W2END_4
  PIN Tile_X0Y0_W2END_5
    DIRECTION INPUT ;
    USE SIGNAL ;
    PORT
      LAYER MET3 ;
        RECT 70.250 126.850 70.800 126.950 ;
    END
  END Tile_X0Y0_W2END_5
  PIN Tile_X0Y0_W2END_6
    DIRECTION INPUT ;
    USE SIGNAL ;
    PORT
      LAYER MET3 ;
        RECT 70.250 127.450 70.800 127.550 ;
    END
  END Tile_X0Y0_W2END_6
  PIN Tile_X0Y0_W2END_7
    DIRECTION INPUT ;
    USE SIGNAL ;
    PORT
      LAYER MET3 ;
        RECT 70.250 128.050 70.800 128.150 ;
    END
  END Tile_X0Y0_W2END_7
  PIN Tile_X0Y0_WW4END_0
    DIRECTION INPUT ;
    USE SIGNAL ;
    PORT
      LAYER MET3 ;
        RECT 70.250 128.650 70.800 128.750 ;
    END
  END Tile_X0Y0_WW4END_0
  PIN Tile_X0Y0_WW4END_1
    DIRECTION INPUT ;
    USE SIGNAL ;
    PORT
      LAYER MET3 ;
        RECT 70.250 129.250 70.800 129.350 ;
    END
  END Tile_X0Y0_WW4END_1
  PIN Tile_X0Y0_WW4END_2
    DIRECTION INPUT ;
    USE SIGNAL ;
    PORT
      LAYER MET3 ;
        RECT 70.250 129.850 70.800 129.950 ;
    END
  END Tile_X0Y0_WW4END_2
  PIN Tile_X0Y0_WW4END_3
    DIRECTION INPUT ;
    USE SIGNAL ;
    PORT
      LAYER MET3 ;
        RECT 70.250 130.450 70.800 130.550 ;
    END
  END Tile_X0Y0_WW4END_3
  PIN Tile_X0Y0_WW4END_4
    DIRECTION INPUT ;
    USE SIGNAL ;
    PORT
      LAYER MET3 ;
        RECT 70.250 131.050 70.800 131.150 ;
    END
  END Tile_X0Y0_WW4END_4
  PIN Tile_X0Y0_WW4END_5
    DIRECTION INPUT ;
    USE SIGNAL ;
    PORT
      LAYER MET3 ;
        RECT 70.250 131.650 70.800 131.750 ;
    END
  END Tile_X0Y0_WW4END_5
  PIN Tile_X0Y0_WW4END_6
    DIRECTION INPUT ;
    USE SIGNAL ;
    PORT
      LAYER MET3 ;
        RECT 70.250 132.250 70.800 132.350 ;
    END
  END Tile_X0Y0_WW4END_6
  PIN Tile_X0Y0_WW4END_7
    DIRECTION INPUT ;
    USE SIGNAL ;
    PORT
      LAYER MET3 ;
        RECT 70.250 132.850 70.800 132.950 ;
    END
  END Tile_X0Y0_WW4END_7
  PIN Tile_X0Y0_WW4END_8
    DIRECTION INPUT ;
    USE SIGNAL ;
    PORT
      LAYER MET3 ;
        RECT 70.250 133.450 70.800 133.550 ;
    END
  END Tile_X0Y0_WW4END_8
  PIN Tile_X0Y0_WW4END_9
    DIRECTION INPUT ;
    USE SIGNAL ;
    PORT
      LAYER MET3 ;
        RECT 70.250 134.050 70.800 134.150 ;
    END
  END Tile_X0Y0_WW4END_9
  PIN Tile_X0Y0_WW4END_10
    DIRECTION INPUT ;
    USE SIGNAL ;
    PORT
      LAYER MET3 ;
        RECT 70.250 134.650 70.800 134.750 ;
    END
  END Tile_X0Y0_WW4END_10
  PIN Tile_X0Y0_WW4END_11
    DIRECTION INPUT ;
    USE SIGNAL ;
    PORT
      LAYER MET3 ;
        RECT 70.250 135.250 70.800 135.350 ;
    END
  END Tile_X0Y0_WW4END_11
  PIN Tile_X0Y0_WW4END_12
    DIRECTION INPUT ;
    USE SIGNAL ;
    PORT
      LAYER MET3 ;
        RECT 70.250 135.850 70.800 135.950 ;
    END
  END Tile_X0Y0_WW4END_12
  PIN Tile_X0Y0_WW4END_13
    DIRECTION INPUT ;
    USE SIGNAL ;
    PORT
      LAYER MET3 ;
        RECT 70.250 136.450 70.800 136.550 ;
    END
  END Tile_X0Y0_WW4END_13
  PIN Tile_X0Y0_WW4END_14
    DIRECTION INPUT ;
    USE SIGNAL ;
    PORT
      LAYER MET3 ;
        RECT 70.250 137.050 70.800 137.150 ;
    END
  END Tile_X0Y0_WW4END_14
  PIN Tile_X0Y0_WW4END_15
    DIRECTION INPUT ;
    USE SIGNAL ;
    PORT
      LAYER MET3 ;
        RECT 70.250 137.650 70.800 137.750 ;
    END
  END Tile_X0Y0_WW4END_15
  PIN Tile_X0Y0_W6END_0
    DIRECTION INPUT ;
    USE SIGNAL ;
    PORT
      LAYER MET3 ;
        RECT 70.250 138.250 70.800 138.350 ;
    END
  END Tile_X0Y0_W6END_0
  PIN Tile_X0Y0_W6END_1
    DIRECTION INPUT ;
    USE SIGNAL ;
    PORT
      LAYER MET3 ;
        RECT 70.250 138.850 70.800 138.950 ;
    END
  END Tile_X0Y0_W6END_1
  PIN Tile_X0Y0_W6END_2
    DIRECTION INPUT ;
    USE SIGNAL ;
    PORT
      LAYER MET3 ;
        RECT 70.250 139.450 70.800 139.550 ;
    END
  END Tile_X0Y0_W6END_2
  PIN Tile_X0Y0_W6END_3
    DIRECTION INPUT ;
    USE SIGNAL ;
    PORT
      LAYER MET3 ;
        RECT 70.250 140.050 70.800 140.150 ;
    END
  END Tile_X0Y0_W6END_3
  PIN Tile_X0Y0_W6END_4
    DIRECTION INPUT ;
    USE SIGNAL ;
    PORT
      LAYER MET3 ;
        RECT 70.250 140.650 70.800 140.750 ;
    END
  END Tile_X0Y0_W6END_4
  PIN Tile_X0Y0_W6END_5
    DIRECTION INPUT ;
    USE SIGNAL ;
    PORT
      LAYER MET3 ;
        RECT 70.250 141.250 70.800 141.350 ;
    END
  END Tile_X0Y0_W6END_5
  PIN Tile_X0Y0_W6END_6
    DIRECTION INPUT ;
    USE SIGNAL ;
    PORT
      LAYER MET3 ;
        RECT 70.250 141.850 70.800 141.950 ;
    END
  END Tile_X0Y0_W6END_6
  PIN Tile_X0Y0_W6END_7
    DIRECTION INPUT ;
    USE SIGNAL ;
    PORT
      LAYER MET3 ;
        RECT 70.250 142.450 70.800 142.550 ;
    END
  END Tile_X0Y0_W6END_7
  PIN Tile_X0Y0_W6END_8
    DIRECTION INPUT ;
    USE SIGNAL ;
    PORT
      LAYER MET3 ;
        RECT 70.250 143.050 70.800 143.150 ;
    END
  END Tile_X0Y0_W6END_8
  PIN Tile_X0Y0_W6END_9
    DIRECTION INPUT ;
    USE SIGNAL ;
    PORT
      LAYER MET3 ;
        RECT 70.250 143.650 70.800 143.750 ;
    END
  END Tile_X0Y0_W6END_9
  PIN Tile_X0Y0_W6END_10
    DIRECTION INPUT ;
    USE SIGNAL ;
    PORT
      LAYER MET3 ;
        RECT 70.250 144.250 70.800 144.350 ;
    END
  END Tile_X0Y0_W6END_10
  PIN Tile_X0Y0_W6END_11
    DIRECTION INPUT ;
    USE SIGNAL ;
    PORT
      LAYER MET3 ;
        RECT 70.250 144.850 70.800 144.950 ;
    END
  END Tile_X0Y0_W6END_11
  PIN Tile_X0Y0_E1END_0
    DIRECTION INPUT ;
    USE SIGNAL ;
    PORT
      LAYER MET3 ;
        RECT 0.000 87.850 0.550 87.950 ;
    END
  END Tile_X0Y0_E1END_0
  PIN Tile_X0Y0_E1END_1
    DIRECTION INPUT ;
    USE SIGNAL ;
    PORT
      LAYER MET3 ;
        RECT 0.000 88.450 0.550 88.550 ;
    END
  END Tile_X0Y0_E1END_1
  PIN Tile_X0Y0_E1END_2
    DIRECTION INPUT ;
    USE SIGNAL ;
    PORT
      LAYER MET3 ;
        RECT 0.000 89.050 0.550 89.150 ;
    END
  END Tile_X0Y0_E1END_2
  PIN Tile_X0Y0_E1END_3
    DIRECTION INPUT ;
    USE SIGNAL ;
    PORT
      LAYER MET3 ;
        RECT 0.000 89.650 0.550 89.750 ;
    END
  END Tile_X0Y0_E1END_3
  PIN Tile_X0Y0_E2MID_0
    DIRECTION INPUT ;
    USE SIGNAL ;
    PORT
      LAYER MET3 ;
        RECT 0.000 90.250 0.550 90.350 ;
    END
  END Tile_X0Y0_E2MID_0
  PIN Tile_X0Y0_E2MID_1
    DIRECTION INPUT ;
    USE SIGNAL ;
    PORT
      LAYER MET3 ;
        RECT 0.000 90.850 0.550 90.950 ;
    END
  END Tile_X0Y0_E2MID_1
  PIN Tile_X0Y0_E2MID_2
    DIRECTION INPUT ;
    USE SIGNAL ;
    PORT
      LAYER MET3 ;
        RECT 0.000 91.450 0.550 91.550 ;
    END
  END Tile_X0Y0_E2MID_2
  PIN Tile_X0Y0_E2MID_3
    DIRECTION INPUT ;
    USE SIGNAL ;
    PORT
      LAYER MET3 ;
        RECT 0.000 92.050 0.550 92.150 ;
    END
  END Tile_X0Y0_E2MID_3
  PIN Tile_X0Y0_E2MID_4
    DIRECTION INPUT ;
    USE SIGNAL ;
    PORT
      LAYER MET3 ;
        RECT 0.000 92.650 0.550 92.750 ;
    END
  END Tile_X0Y0_E2MID_4
  PIN Tile_X0Y0_E2MID_5
    DIRECTION INPUT ;
    USE SIGNAL ;
    PORT
      LAYER MET3 ;
        RECT 0.000 93.250 0.550 93.350 ;
    END
  END Tile_X0Y0_E2MID_5
  PIN Tile_X0Y0_E2MID_6
    DIRECTION INPUT ;
    USE SIGNAL ;
    PORT
      LAYER MET3 ;
        RECT 0.000 93.850 0.550 93.950 ;
    END
  END Tile_X0Y0_E2MID_6
  PIN Tile_X0Y0_E2MID_7
    DIRECTION INPUT ;
    USE SIGNAL ;
    PORT
      LAYER MET3 ;
        RECT 0.000 94.450 0.550 94.550 ;
    END
  END Tile_X0Y0_E2MID_7
  PIN Tile_X0Y0_E2END_0
    DIRECTION INPUT ;
    USE SIGNAL ;
    PORT
      LAYER MET3 ;
        RECT 0.000 95.050 0.550 95.150 ;
    END
  END Tile_X0Y0_E2END_0
  PIN Tile_X0Y0_E2END_1
    DIRECTION INPUT ;
    USE SIGNAL ;
    PORT
      LAYER MET3 ;
        RECT 0.000 95.650 0.550 95.750 ;
    END
  END Tile_X0Y0_E2END_1
  PIN Tile_X0Y0_E2END_2
    DIRECTION INPUT ;
    USE SIGNAL ;
    PORT
      LAYER MET3 ;
        RECT 0.000 96.250 0.550 96.350 ;
    END
  END Tile_X0Y0_E2END_2
  PIN Tile_X0Y0_E2END_3
    DIRECTION INPUT ;
    USE SIGNAL ;
    PORT
      LAYER MET3 ;
        RECT 0.000 96.850 0.550 96.950 ;
    END
  END Tile_X0Y0_E2END_3
  PIN Tile_X0Y0_E2END_4
    DIRECTION INPUT ;
    USE SIGNAL ;
    PORT
      LAYER MET3 ;
        RECT 0.000 97.450 0.550 97.550 ;
    END
  END Tile_X0Y0_E2END_4
  PIN Tile_X0Y0_E2END_5
    DIRECTION INPUT ;
    USE SIGNAL ;
    PORT
      LAYER MET3 ;
        RECT 0.000 98.050 0.550 98.150 ;
    END
  END Tile_X0Y0_E2END_5
  PIN Tile_X0Y0_E2END_6
    DIRECTION INPUT ;
    USE SIGNAL ;
    PORT
      LAYER MET3 ;
        RECT 0.000 98.650 0.550 98.750 ;
    END
  END Tile_X0Y0_E2END_6
  PIN Tile_X0Y0_E2END_7
    DIRECTION INPUT ;
    USE SIGNAL ;
    PORT
      LAYER MET3 ;
        RECT 0.000 99.250 0.550 99.350 ;
    END
  END Tile_X0Y0_E2END_7
  PIN Tile_X0Y0_EE4END_0
    DIRECTION INPUT ;
    USE SIGNAL ;
    PORT
      LAYER MET3 ;
        RECT 0.000 99.850 0.550 99.950 ;
    END
  END Tile_X0Y0_EE4END_0
  PIN Tile_X0Y0_EE4END_1
    DIRECTION INPUT ;
    USE SIGNAL ;
    PORT
      LAYER MET3 ;
        RECT 0.000 100.450 0.550 100.550 ;
    END
  END Tile_X0Y0_EE4END_1
  PIN Tile_X0Y0_EE4END_2
    DIRECTION INPUT ;
    USE SIGNAL ;
    PORT
      LAYER MET3 ;
        RECT 0.000 101.050 0.550 101.150 ;
    END
  END Tile_X0Y0_EE4END_2
  PIN Tile_X0Y0_EE4END_3
    DIRECTION INPUT ;
    USE SIGNAL ;
    PORT
      LAYER MET3 ;
        RECT 0.000 101.650 0.550 101.750 ;
    END
  END Tile_X0Y0_EE4END_3
  PIN Tile_X0Y0_EE4END_4
    DIRECTION INPUT ;
    USE SIGNAL ;
    PORT
      LAYER MET3 ;
        RECT 0.000 102.250 0.550 102.350 ;
    END
  END Tile_X0Y0_EE4END_4
  PIN Tile_X0Y0_EE4END_5
    DIRECTION INPUT ;
    USE SIGNAL ;
    PORT
      LAYER MET3 ;
        RECT 0.000 102.850 0.550 102.950 ;
    END
  END Tile_X0Y0_EE4END_5
  PIN Tile_X0Y0_EE4END_6
    DIRECTION INPUT ;
    USE SIGNAL ;
    PORT
      LAYER MET3 ;
        RECT 0.000 103.450 0.550 103.550 ;
    END
  END Tile_X0Y0_EE4END_6
  PIN Tile_X0Y0_EE4END_7
    DIRECTION INPUT ;
    USE SIGNAL ;
    PORT
      LAYER MET3 ;
        RECT 0.000 104.050 0.550 104.150 ;
    END
  END Tile_X0Y0_EE4END_7
  PIN Tile_X0Y0_EE4END_8
    DIRECTION INPUT ;
    USE SIGNAL ;
    PORT
      LAYER MET3 ;
        RECT 0.000 104.650 0.550 104.750 ;
    END
  END Tile_X0Y0_EE4END_8
  PIN Tile_X0Y0_EE4END_9
    DIRECTION INPUT ;
    USE SIGNAL ;
    PORT
      LAYER MET3 ;
        RECT 0.000 105.250 0.550 105.350 ;
    END
  END Tile_X0Y0_EE4END_9
  PIN Tile_X0Y0_EE4END_10
    DIRECTION INPUT ;
    USE SIGNAL ;
    PORT
      LAYER MET3 ;
        RECT 0.000 105.850 0.550 105.950 ;
    END
  END Tile_X0Y0_EE4END_10
  PIN Tile_X0Y0_EE4END_11
    DIRECTION INPUT ;
    USE SIGNAL ;
    PORT
      LAYER MET3 ;
        RECT 0.000 106.450 0.550 106.550 ;
    END
  END Tile_X0Y0_EE4END_11
  PIN Tile_X0Y0_EE4END_12
    DIRECTION INPUT ;
    USE SIGNAL ;
    PORT
      LAYER MET3 ;
        RECT 0.000 107.050 0.550 107.150 ;
    END
  END Tile_X0Y0_EE4END_12
  PIN Tile_X0Y0_EE4END_13
    DIRECTION INPUT ;
    USE SIGNAL ;
    PORT
      LAYER MET3 ;
        RECT 0.000 107.650 0.550 107.750 ;
    END
  END Tile_X0Y0_EE4END_13
  PIN Tile_X0Y0_EE4END_14
    DIRECTION INPUT ;
    USE SIGNAL ;
    PORT
      LAYER MET3 ;
        RECT 0.000 108.250 0.550 108.350 ;
    END
  END Tile_X0Y0_EE4END_14
  PIN Tile_X0Y0_EE4END_15
    DIRECTION INPUT ;
    USE SIGNAL ;
    PORT
      LAYER MET3 ;
        RECT 0.000 108.850 0.550 108.950 ;
    END
  END Tile_X0Y0_EE4END_15
  PIN Tile_X0Y0_E6END_0
    DIRECTION INPUT ;
    USE SIGNAL ;
    PORT
      LAYER MET3 ;
        RECT 0.000 109.450 0.550 109.550 ;
    END
  END Tile_X0Y0_E6END_0
  PIN Tile_X0Y0_E6END_1
    DIRECTION INPUT ;
    USE SIGNAL ;
    PORT
      LAYER MET3 ;
        RECT 0.000 110.050 0.550 110.150 ;
    END
  END Tile_X0Y0_E6END_1
  PIN Tile_X0Y0_E6END_2
    DIRECTION INPUT ;
    USE SIGNAL ;
    PORT
      LAYER MET3 ;
        RECT 0.000 110.650 0.550 110.750 ;
    END
  END Tile_X0Y0_E6END_2
  PIN Tile_X0Y0_E6END_3
    DIRECTION INPUT ;
    USE SIGNAL ;
    PORT
      LAYER MET3 ;
        RECT 0.000 111.250 0.550 111.350 ;
    END
  END Tile_X0Y0_E6END_3
  PIN Tile_X0Y0_E6END_4
    DIRECTION INPUT ;
    USE SIGNAL ;
    PORT
      LAYER MET3 ;
        RECT 0.000 111.850 0.550 111.950 ;
    END
  END Tile_X0Y0_E6END_4
  PIN Tile_X0Y0_E6END_5
    DIRECTION INPUT ;
    USE SIGNAL ;
    PORT
      LAYER MET3 ;
        RECT 0.000 112.450 0.550 112.550 ;
    END
  END Tile_X0Y0_E6END_5
  PIN Tile_X0Y0_E6END_6
    DIRECTION INPUT ;
    USE SIGNAL ;
    PORT
      LAYER MET3 ;
        RECT 0.000 113.050 0.550 113.150 ;
    END
  END Tile_X0Y0_E6END_6
  PIN Tile_X0Y0_E6END_7
    DIRECTION INPUT ;
    USE SIGNAL ;
    PORT
      LAYER MET3 ;
        RECT 0.000 113.650 0.550 113.750 ;
    END
  END Tile_X0Y0_E6END_7
  PIN Tile_X0Y0_E6END_8
    DIRECTION INPUT ;
    USE SIGNAL ;
    PORT
      LAYER MET3 ;
        RECT 0.000 114.250 0.550 114.350 ;
    END
  END Tile_X0Y0_E6END_8
  PIN Tile_X0Y0_E6END_9
    DIRECTION INPUT ;
    USE SIGNAL ;
    PORT
      LAYER MET3 ;
        RECT 0.000 114.850 0.550 114.950 ;
    END
  END Tile_X0Y0_E6END_9
  PIN Tile_X0Y0_E6END_10
    DIRECTION INPUT ;
    USE SIGNAL ;
    PORT
      LAYER MET3 ;
        RECT 0.000 115.450 0.550 115.550 ;
    END
  END Tile_X0Y0_E6END_10
  PIN Tile_X0Y0_E6END_11
    DIRECTION INPUT ;
    USE SIGNAL ;
    PORT
      LAYER MET3 ;
        RECT 0.000 116.050 0.550 116.150 ;
    END
  END Tile_X0Y0_E6END_11
  PIN Tile_X0Y0_W1BEG_0
    DIRECTION OUTPUT ;
    USE SIGNAL ;
    PORT
      LAYER MET3 ;
        RECT 0.000 116.650 0.550 116.750 ;
    END
  END Tile_X0Y0_W1BEG_0
  PIN Tile_X0Y0_W1BEG_1
    DIRECTION OUTPUT ;
    USE SIGNAL ;
    PORT
      LAYER MET3 ;
        RECT 0.000 117.250 0.550 117.350 ;
    END
  END Tile_X0Y0_W1BEG_1
  PIN Tile_X0Y0_W1BEG_2
    DIRECTION OUTPUT ;
    USE SIGNAL ;
    PORT
      LAYER MET3 ;
        RECT 0.000 117.850 0.550 117.950 ;
    END
  END Tile_X0Y0_W1BEG_2
  PIN Tile_X0Y0_W1BEG_3
    DIRECTION OUTPUT ;
    USE SIGNAL ;
    PORT
      LAYER MET3 ;
        RECT 0.000 118.450 0.550 118.550 ;
    END
  END Tile_X0Y0_W1BEG_3
  PIN Tile_X0Y0_W2BEG_0
    DIRECTION OUTPUT ;
    USE SIGNAL ;
    PORT
      LAYER MET3 ;
        RECT 0.000 119.050 0.550 119.150 ;
    END
  END Tile_X0Y0_W2BEG_0
  PIN Tile_X0Y0_W2BEG_1
    DIRECTION OUTPUT ;
    USE SIGNAL ;
    PORT
      LAYER MET3 ;
        RECT 0.000 119.650 0.550 119.750 ;
    END
  END Tile_X0Y0_W2BEG_1
  PIN Tile_X0Y0_W2BEG_2
    DIRECTION OUTPUT ;
    USE SIGNAL ;
    PORT
      LAYER MET3 ;
        RECT 0.000 120.250 0.550 120.350 ;
    END
  END Tile_X0Y0_W2BEG_2
  PIN Tile_X0Y0_W2BEG_3
    DIRECTION OUTPUT ;
    USE SIGNAL ;
    PORT
      LAYER MET3 ;
        RECT 0.000 120.850 0.550 120.950 ;
    END
  END Tile_X0Y0_W2BEG_3
  PIN Tile_X0Y0_W2BEG_4
    DIRECTION OUTPUT ;
    USE SIGNAL ;
    PORT
      LAYER MET3 ;
        RECT 0.000 121.450 0.550 121.550 ;
    END
  END Tile_X0Y0_W2BEG_4
  PIN Tile_X0Y0_W2BEG_5
    DIRECTION OUTPUT ;
    USE SIGNAL ;
    PORT
      LAYER MET3 ;
        RECT 0.000 122.050 0.550 122.150 ;
    END
  END Tile_X0Y0_W2BEG_5
  PIN Tile_X0Y0_W2BEG_6
    DIRECTION OUTPUT ;
    USE SIGNAL ;
    PORT
      LAYER MET3 ;
        RECT 0.000 122.650 0.550 122.750 ;
    END
  END Tile_X0Y0_W2BEG_6
  PIN Tile_X0Y0_W2BEG_7
    DIRECTION OUTPUT ;
    USE SIGNAL ;
    PORT
      LAYER MET3 ;
        RECT 0.000 123.250 0.550 123.350 ;
    END
  END Tile_X0Y0_W2BEG_7
  PIN Tile_X0Y0_W2BEGb_0
    DIRECTION OUTPUT ;
    USE SIGNAL ;
    PORT
      LAYER MET3 ;
        RECT 0.000 123.850 0.550 123.950 ;
    END
  END Tile_X0Y0_W2BEGb_0
  PIN Tile_X0Y0_W2BEGb_1
    DIRECTION OUTPUT ;
    USE SIGNAL ;
    PORT
      LAYER MET3 ;
        RECT 0.000 124.450 0.550 124.550 ;
    END
  END Tile_X0Y0_W2BEGb_1
  PIN Tile_X0Y0_W2BEGb_2
    DIRECTION OUTPUT ;
    USE SIGNAL ;
    PORT
      LAYER MET3 ;
        RECT 0.000 125.050 0.550 125.150 ;
    END
  END Tile_X0Y0_W2BEGb_2
  PIN Tile_X0Y0_W2BEGb_3
    DIRECTION OUTPUT ;
    USE SIGNAL ;
    PORT
      LAYER MET3 ;
        RECT 0.000 125.650 0.550 125.750 ;
    END
  END Tile_X0Y0_W2BEGb_3
  PIN Tile_X0Y0_W2BEGb_4
    DIRECTION OUTPUT ;
    USE SIGNAL ;
    PORT
      LAYER MET3 ;
        RECT 0.000 126.250 0.550 126.350 ;
    END
  END Tile_X0Y0_W2BEGb_4
  PIN Tile_X0Y0_W2BEGb_5
    DIRECTION OUTPUT ;
    USE SIGNAL ;
    PORT
      LAYER MET3 ;
        RECT 0.000 126.850 0.550 126.950 ;
    END
  END Tile_X0Y0_W2BEGb_5
  PIN Tile_X0Y0_W2BEGb_6
    DIRECTION OUTPUT ;
    USE SIGNAL ;
    PORT
      LAYER MET3 ;
        RECT 0.000 127.450 0.550 127.550 ;
    END
  END Tile_X0Y0_W2BEGb_6
  PIN Tile_X0Y0_W2BEGb_7
    DIRECTION OUTPUT ;
    USE SIGNAL ;
    PORT
      LAYER MET3 ;
        RECT 0.000 128.050 0.550 128.150 ;
    END
  END Tile_X0Y0_W2BEGb_7
  PIN Tile_X0Y0_WW4BEG_0
    DIRECTION OUTPUT ;
    USE SIGNAL ;
    PORT
      LAYER MET3 ;
        RECT 0.000 128.650 0.550 128.750 ;
    END
  END Tile_X0Y0_WW4BEG_0
  PIN Tile_X0Y0_WW4BEG_1
    DIRECTION OUTPUT ;
    USE SIGNAL ;
    PORT
      LAYER MET3 ;
        RECT 0.000 129.250 0.550 129.350 ;
    END
  END Tile_X0Y0_WW4BEG_1
  PIN Tile_X0Y0_WW4BEG_2
    DIRECTION OUTPUT ;
    USE SIGNAL ;
    PORT
      LAYER MET3 ;
        RECT 0.000 129.850 0.550 129.950 ;
    END
  END Tile_X0Y0_WW4BEG_2
  PIN Tile_X0Y0_WW4BEG_3
    DIRECTION OUTPUT ;
    USE SIGNAL ;
    PORT
      LAYER MET3 ;
        RECT 0.000 130.450 0.550 130.550 ;
    END
  END Tile_X0Y0_WW4BEG_3
  PIN Tile_X0Y0_WW4BEG_4
    DIRECTION OUTPUT ;
    USE SIGNAL ;
    PORT
      LAYER MET3 ;
        RECT 0.000 131.050 0.550 131.150 ;
    END
  END Tile_X0Y0_WW4BEG_4
  PIN Tile_X0Y0_WW4BEG_5
    DIRECTION OUTPUT ;
    USE SIGNAL ;
    PORT
      LAYER MET3 ;
        RECT 0.000 131.650 0.550 131.750 ;
    END
  END Tile_X0Y0_WW4BEG_5
  PIN Tile_X0Y0_WW4BEG_6
    DIRECTION OUTPUT ;
    USE SIGNAL ;
    PORT
      LAYER MET3 ;
        RECT 0.000 132.250 0.550 132.350 ;
    END
  END Tile_X0Y0_WW4BEG_6
  PIN Tile_X0Y0_WW4BEG_7
    DIRECTION OUTPUT ;
    USE SIGNAL ;
    PORT
      LAYER MET3 ;
        RECT 0.000 132.850 0.550 132.950 ;
    END
  END Tile_X0Y0_WW4BEG_7
  PIN Tile_X0Y0_WW4BEG_8
    DIRECTION OUTPUT ;
    USE SIGNAL ;
    PORT
      LAYER MET3 ;
        RECT 0.000 133.450 0.550 133.550 ;
    END
  END Tile_X0Y0_WW4BEG_8
  PIN Tile_X0Y0_WW4BEG_9
    DIRECTION OUTPUT ;
    USE SIGNAL ;
    PORT
      LAYER MET3 ;
        RECT 0.000 134.050 0.550 134.150 ;
    END
  END Tile_X0Y0_WW4BEG_9
  PIN Tile_X0Y0_WW4BEG_10
    DIRECTION OUTPUT ;
    USE SIGNAL ;
    PORT
      LAYER MET3 ;
        RECT 0.000 134.650 0.550 134.750 ;
    END
  END Tile_X0Y0_WW4BEG_10
  PIN Tile_X0Y0_WW4BEG_11
    DIRECTION OUTPUT ;
    USE SIGNAL ;
    PORT
      LAYER MET3 ;
        RECT 0.000 135.250 0.550 135.350 ;
    END
  END Tile_X0Y0_WW4BEG_11
  PIN Tile_X0Y0_WW4BEG_12
    DIRECTION OUTPUT ;
    USE SIGNAL ;
    PORT
      LAYER MET3 ;
        RECT 0.000 135.850 0.550 135.950 ;
    END
  END Tile_X0Y0_WW4BEG_12
  PIN Tile_X0Y0_WW4BEG_13
    DIRECTION OUTPUT ;
    USE SIGNAL ;
    PORT
      LAYER MET3 ;
        RECT 0.000 136.450 0.550 136.550 ;
    END
  END Tile_X0Y0_WW4BEG_13
  PIN Tile_X0Y0_WW4BEG_14
    DIRECTION OUTPUT ;
    USE SIGNAL ;
    PORT
      LAYER MET3 ;
        RECT 0.000 137.050 0.550 137.150 ;
    END
  END Tile_X0Y0_WW4BEG_14
  PIN Tile_X0Y0_WW4BEG_15
    DIRECTION OUTPUT ;
    USE SIGNAL ;
    PORT
      LAYER MET3 ;
        RECT 0.000 137.650 0.550 137.750 ;
    END
  END Tile_X0Y0_WW4BEG_15
  PIN Tile_X0Y0_W6BEG_0
    DIRECTION OUTPUT ;
    USE SIGNAL ;
    PORT
      LAYER MET3 ;
        RECT 0.000 138.250 0.550 138.350 ;
    END
  END Tile_X0Y0_W6BEG_0
  PIN Tile_X0Y0_W6BEG_1
    DIRECTION OUTPUT ;
    USE SIGNAL ;
    PORT
      LAYER MET3 ;
        RECT 0.000 138.850 0.550 138.950 ;
    END
  END Tile_X0Y0_W6BEG_1
  PIN Tile_X0Y0_W6BEG_2
    DIRECTION OUTPUT ;
    USE SIGNAL ;
    PORT
      LAYER MET3 ;
        RECT 0.000 139.450 0.550 139.550 ;
    END
  END Tile_X0Y0_W6BEG_2
  PIN Tile_X0Y0_W6BEG_3
    DIRECTION OUTPUT ;
    USE SIGNAL ;
    PORT
      LAYER MET3 ;
        RECT 0.000 140.050 0.550 140.150 ;
    END
  END Tile_X0Y0_W6BEG_3
  PIN Tile_X0Y0_W6BEG_4
    DIRECTION OUTPUT ;
    USE SIGNAL ;
    PORT
      LAYER MET3 ;
        RECT 0.000 140.650 0.550 140.750 ;
    END
  END Tile_X0Y0_W6BEG_4
  PIN Tile_X0Y0_W6BEG_5
    DIRECTION OUTPUT ;
    USE SIGNAL ;
    PORT
      LAYER MET3 ;
        RECT 0.000 141.250 0.550 141.350 ;
    END
  END Tile_X0Y0_W6BEG_5
  PIN Tile_X0Y0_W6BEG_6
    DIRECTION OUTPUT ;
    USE SIGNAL ;
    PORT
      LAYER MET3 ;
        RECT 0.000 141.850 0.550 141.950 ;
    END
  END Tile_X0Y0_W6BEG_6
  PIN Tile_X0Y0_W6BEG_7
    DIRECTION OUTPUT ;
    USE SIGNAL ;
    PORT
      LAYER MET3 ;
        RECT 0.000 142.450 0.550 142.550 ;
    END
  END Tile_X0Y0_W6BEG_7
  PIN Tile_X0Y0_W6BEG_8
    DIRECTION OUTPUT ;
    USE SIGNAL ;
    PORT
      LAYER MET3 ;
        RECT 0.000 143.050 0.550 143.150 ;
    END
  END Tile_X0Y0_W6BEG_8
  PIN Tile_X0Y0_W6BEG_9
    DIRECTION OUTPUT ;
    USE SIGNAL ;
    PORT
      LAYER MET3 ;
        RECT 0.000 143.650 0.550 143.750 ;
    END
  END Tile_X0Y0_W6BEG_9
  PIN Tile_X0Y0_W6BEG_10
    DIRECTION OUTPUT ;
    USE SIGNAL ;
    PORT
      LAYER MET3 ;
        RECT 0.000 144.250 0.550 144.350 ;
    END
  END Tile_X0Y0_W6BEG_10
  PIN Tile_X0Y0_W6BEG_11
    DIRECTION OUTPUT ;
    USE SIGNAL ;
    PORT
      LAYER MET3 ;
        RECT 0.000 144.850 0.550 144.950 ;
    END
  END Tile_X0Y0_W6BEG_11
  PIN Tile_X0Y1_E1BEG_0
    DIRECTION OUTPUT ;
    USE SIGNAL ;
    PORT
      LAYER MET3 ;
        RECT 70.250 3.850 70.800 3.950 ;
    END
  END Tile_X0Y1_E1BEG_0
  PIN Tile_X0Y1_E1BEG_1
    DIRECTION OUTPUT ;
    USE SIGNAL ;
    PORT
      LAYER MET3 ;
        RECT 70.250 4.450 70.800 4.550 ;
    END
  END Tile_X0Y1_E1BEG_1
  PIN Tile_X0Y1_E1BEG_2
    DIRECTION OUTPUT ;
    USE SIGNAL ;
    PORT
      LAYER MET3 ;
        RECT 70.250 5.050 70.800 5.150 ;
    END
  END Tile_X0Y1_E1BEG_2
  PIN Tile_X0Y1_E1BEG_3
    DIRECTION OUTPUT ;
    USE SIGNAL ;
    PORT
      LAYER MET3 ;
        RECT 70.250 5.650 70.800 5.750 ;
    END
  END Tile_X0Y1_E1BEG_3
  PIN Tile_X0Y1_E2BEG_0
    DIRECTION OUTPUT ;
    USE SIGNAL ;
    PORT
      LAYER MET3 ;
        RECT 70.250 6.250 70.800 6.350 ;
    END
  END Tile_X0Y1_E2BEG_0
  PIN Tile_X0Y1_E2BEG_1
    DIRECTION OUTPUT ;
    USE SIGNAL ;
    PORT
      LAYER MET3 ;
        RECT 70.250 6.850 70.800 6.950 ;
    END
  END Tile_X0Y1_E2BEG_1
  PIN Tile_X0Y1_E2BEG_2
    DIRECTION OUTPUT ;
    USE SIGNAL ;
    PORT
      LAYER MET3 ;
        RECT 70.250 7.450 70.800 7.550 ;
    END
  END Tile_X0Y1_E2BEG_2
  PIN Tile_X0Y1_E2BEG_3
    DIRECTION OUTPUT ;
    USE SIGNAL ;
    PORT
      LAYER MET3 ;
        RECT 70.250 8.050 70.800 8.150 ;
    END
  END Tile_X0Y1_E2BEG_3
  PIN Tile_X0Y1_E2BEG_4
    DIRECTION OUTPUT ;
    USE SIGNAL ;
    PORT
      LAYER MET3 ;
        RECT 70.250 8.650 70.800 8.750 ;
    END
  END Tile_X0Y1_E2BEG_4
  PIN Tile_X0Y1_E2BEG_5
    DIRECTION OUTPUT ;
    USE SIGNAL ;
    PORT
      LAYER MET3 ;
        RECT 70.250 9.250 70.800 9.350 ;
    END
  END Tile_X0Y1_E2BEG_5
  PIN Tile_X0Y1_E2BEG_6
    DIRECTION OUTPUT ;
    USE SIGNAL ;
    PORT
      LAYER MET3 ;
        RECT 70.250 9.850 70.800 9.950 ;
    END
  END Tile_X0Y1_E2BEG_6
  PIN Tile_X0Y1_E2BEG_7
    DIRECTION OUTPUT ;
    USE SIGNAL ;
    PORT
      LAYER MET3 ;
        RECT 70.250 10.450 70.800 10.550 ;
    END
  END Tile_X0Y1_E2BEG_7
  PIN Tile_X0Y1_E2BEGb_0
    DIRECTION OUTPUT ;
    USE SIGNAL ;
    PORT
      LAYER MET3 ;
        RECT 70.250 11.050 70.800 11.150 ;
    END
  END Tile_X0Y1_E2BEGb_0
  PIN Tile_X0Y1_E2BEGb_1
    DIRECTION OUTPUT ;
    USE SIGNAL ;
    PORT
      LAYER MET3 ;
        RECT 70.250 11.650 70.800 11.750 ;
    END
  END Tile_X0Y1_E2BEGb_1
  PIN Tile_X0Y1_E2BEGb_2
    DIRECTION OUTPUT ;
    USE SIGNAL ;
    PORT
      LAYER MET3 ;
        RECT 70.250 12.250 70.800 12.350 ;
    END
  END Tile_X0Y1_E2BEGb_2
  PIN Tile_X0Y1_E2BEGb_3
    DIRECTION OUTPUT ;
    USE SIGNAL ;
    PORT
      LAYER MET3 ;
        RECT 70.250 12.850 70.800 12.950 ;
    END
  END Tile_X0Y1_E2BEGb_3
  PIN Tile_X0Y1_E2BEGb_4
    DIRECTION OUTPUT ;
    USE SIGNAL ;
    PORT
      LAYER MET3 ;
        RECT 70.250 13.450 70.800 13.550 ;
    END
  END Tile_X0Y1_E2BEGb_4
  PIN Tile_X0Y1_E2BEGb_5
    DIRECTION OUTPUT ;
    USE SIGNAL ;
    PORT
      LAYER MET3 ;
        RECT 70.250 14.050 70.800 14.150 ;
    END
  END Tile_X0Y1_E2BEGb_5
  PIN Tile_X0Y1_E2BEGb_6
    DIRECTION OUTPUT ;
    USE SIGNAL ;
    PORT
      LAYER MET3 ;
        RECT 70.250 14.650 70.800 14.750 ;
    END
  END Tile_X0Y1_E2BEGb_6
  PIN Tile_X0Y1_E2BEGb_7
    DIRECTION OUTPUT ;
    USE SIGNAL ;
    PORT
      LAYER MET3 ;
        RECT 70.250 15.250 70.800 15.350 ;
    END
  END Tile_X0Y1_E2BEGb_7
  PIN Tile_X0Y1_EE4BEG_0
    DIRECTION OUTPUT ;
    USE SIGNAL ;
    PORT
      LAYER MET3 ;
        RECT 70.250 15.850 70.800 15.950 ;
    END
  END Tile_X0Y1_EE4BEG_0
  PIN Tile_X0Y1_EE4BEG_1
    DIRECTION OUTPUT ;
    USE SIGNAL ;
    PORT
      LAYER MET3 ;
        RECT 70.250 16.450 70.800 16.550 ;
    END
  END Tile_X0Y1_EE4BEG_1
  PIN Tile_X0Y1_EE4BEG_2
    DIRECTION OUTPUT ;
    USE SIGNAL ;
    PORT
      LAYER MET3 ;
        RECT 70.250 17.050 70.800 17.150 ;
    END
  END Tile_X0Y1_EE4BEG_2
  PIN Tile_X0Y1_EE4BEG_3
    DIRECTION OUTPUT ;
    USE SIGNAL ;
    PORT
      LAYER MET3 ;
        RECT 70.250 17.650 70.800 17.750 ;
    END
  END Tile_X0Y1_EE4BEG_3
  PIN Tile_X0Y1_EE4BEG_4
    DIRECTION OUTPUT ;
    USE SIGNAL ;
    PORT
      LAYER MET3 ;
        RECT 70.250 18.250 70.800 18.350 ;
    END
  END Tile_X0Y1_EE4BEG_4
  PIN Tile_X0Y1_EE4BEG_5
    DIRECTION OUTPUT ;
    USE SIGNAL ;
    PORT
      LAYER MET3 ;
        RECT 70.250 18.850 70.800 18.950 ;
    END
  END Tile_X0Y1_EE4BEG_5
  PIN Tile_X0Y1_EE4BEG_6
    DIRECTION OUTPUT ;
    USE SIGNAL ;
    PORT
      LAYER MET3 ;
        RECT 70.250 19.450 70.800 19.550 ;
    END
  END Tile_X0Y1_EE4BEG_6
  PIN Tile_X0Y1_EE4BEG_7
    DIRECTION OUTPUT ;
    USE SIGNAL ;
    PORT
      LAYER MET3 ;
        RECT 70.250 20.050 70.800 20.150 ;
    END
  END Tile_X0Y1_EE4BEG_7
  PIN Tile_X0Y1_EE4BEG_8
    DIRECTION OUTPUT ;
    USE SIGNAL ;
    PORT
      LAYER MET3 ;
        RECT 70.250 20.650 70.800 20.750 ;
    END
  END Tile_X0Y1_EE4BEG_8
  PIN Tile_X0Y1_EE4BEG_9
    DIRECTION OUTPUT ;
    USE SIGNAL ;
    PORT
      LAYER MET3 ;
        RECT 70.250 21.250 70.800 21.350 ;
    END
  END Tile_X0Y1_EE4BEG_9
  PIN Tile_X0Y1_EE4BEG_10
    DIRECTION OUTPUT ;
    USE SIGNAL ;
    PORT
      LAYER MET3 ;
        RECT 70.250 21.850 70.800 21.950 ;
    END
  END Tile_X0Y1_EE4BEG_10
  PIN Tile_X0Y1_EE4BEG_11
    DIRECTION OUTPUT ;
    USE SIGNAL ;
    PORT
      LAYER MET3 ;
        RECT 70.250 22.450 70.800 22.550 ;
    END
  END Tile_X0Y1_EE4BEG_11
  PIN Tile_X0Y1_EE4BEG_12
    DIRECTION OUTPUT ;
    USE SIGNAL ;
    PORT
      LAYER MET3 ;
        RECT 70.250 23.050 70.800 23.150 ;
    END
  END Tile_X0Y1_EE4BEG_12
  PIN Tile_X0Y1_EE4BEG_13
    DIRECTION OUTPUT ;
    USE SIGNAL ;
    PORT
      LAYER MET3 ;
        RECT 70.250 23.650 70.800 23.750 ;
    END
  END Tile_X0Y1_EE4BEG_13
  PIN Tile_X0Y1_EE4BEG_14
    DIRECTION OUTPUT ;
    USE SIGNAL ;
    PORT
      LAYER MET3 ;
        RECT 70.250 24.250 70.800 24.350 ;
    END
  END Tile_X0Y1_EE4BEG_14
  PIN Tile_X0Y1_EE4BEG_15
    DIRECTION OUTPUT ;
    USE SIGNAL ;
    PORT
      LAYER MET3 ;
        RECT 70.250 24.850 70.800 24.950 ;
    END
  END Tile_X0Y1_EE4BEG_15
  PIN Tile_X0Y1_E6BEG_0
    DIRECTION OUTPUT ;
    USE SIGNAL ;
    PORT
      LAYER MET3 ;
        RECT 70.250 25.450 70.800 25.550 ;
    END
  END Tile_X0Y1_E6BEG_0
  PIN Tile_X0Y1_E6BEG_1
    DIRECTION OUTPUT ;
    USE SIGNAL ;
    PORT
      LAYER MET3 ;
        RECT 70.250 26.050 70.800 26.150 ;
    END
  END Tile_X0Y1_E6BEG_1
  PIN Tile_X0Y1_E6BEG_2
    DIRECTION OUTPUT ;
    USE SIGNAL ;
    PORT
      LAYER MET3 ;
        RECT 70.250 26.650 70.800 26.750 ;
    END
  END Tile_X0Y1_E6BEG_2
  PIN Tile_X0Y1_E6BEG_3
    DIRECTION OUTPUT ;
    USE SIGNAL ;
    PORT
      LAYER MET3 ;
        RECT 70.250 27.250 70.800 27.350 ;
    END
  END Tile_X0Y1_E6BEG_3
  PIN Tile_X0Y1_E6BEG_4
    DIRECTION OUTPUT ;
    USE SIGNAL ;
    PORT
      LAYER MET3 ;
        RECT 70.250 27.850 70.800 27.950 ;
    END
  END Tile_X0Y1_E6BEG_4
  PIN Tile_X0Y1_E6BEG_5
    DIRECTION OUTPUT ;
    USE SIGNAL ;
    PORT
      LAYER MET3 ;
        RECT 70.250 28.450 70.800 28.550 ;
    END
  END Tile_X0Y1_E6BEG_5
  PIN Tile_X0Y1_E6BEG_6
    DIRECTION OUTPUT ;
    USE SIGNAL ;
    PORT
      LAYER MET3 ;
        RECT 70.250 29.050 70.800 29.150 ;
    END
  END Tile_X0Y1_E6BEG_6
  PIN Tile_X0Y1_E6BEG_7
    DIRECTION OUTPUT ;
    USE SIGNAL ;
    PORT
      LAYER MET3 ;
        RECT 70.250 29.650 70.800 29.750 ;
    END
  END Tile_X0Y1_E6BEG_7
  PIN Tile_X0Y1_E6BEG_8
    DIRECTION OUTPUT ;
    USE SIGNAL ;
    PORT
      LAYER MET3 ;
        RECT 70.250 30.250 70.800 30.350 ;
    END
  END Tile_X0Y1_E6BEG_8
  PIN Tile_X0Y1_E6BEG_9
    DIRECTION OUTPUT ;
    USE SIGNAL ;
    PORT
      LAYER MET3 ;
        RECT 70.250 30.850 70.800 30.950 ;
    END
  END Tile_X0Y1_E6BEG_9
  PIN Tile_X0Y1_E6BEG_10
    DIRECTION OUTPUT ;
    USE SIGNAL ;
    PORT
      LAYER MET3 ;
        RECT 70.250 31.450 70.800 31.550 ;
    END
  END Tile_X0Y1_E6BEG_10
  PIN Tile_X0Y1_E6BEG_11
    DIRECTION OUTPUT ;
    USE SIGNAL ;
    PORT
      LAYER MET3 ;
        RECT 70.250 32.050 70.800 32.150 ;
    END
  END Tile_X0Y1_E6BEG_11
  PIN Tile_X0Y1_W1END_0
    DIRECTION INPUT ;
    USE SIGNAL ;
    PORT
      LAYER MET3 ;
        RECT 70.250 32.650 70.800 32.750 ;
    END
  END Tile_X0Y1_W1END_0
  PIN Tile_X0Y1_W1END_1
    DIRECTION INPUT ;
    USE SIGNAL ;
    PORT
      LAYER MET3 ;
        RECT 70.250 33.250 70.800 33.350 ;
    END
  END Tile_X0Y1_W1END_1
  PIN Tile_X0Y1_W1END_2
    DIRECTION INPUT ;
    USE SIGNAL ;
    PORT
      LAYER MET3 ;
        RECT 70.250 33.850 70.800 33.950 ;
    END
  END Tile_X0Y1_W1END_2
  PIN Tile_X0Y1_W1END_3
    DIRECTION INPUT ;
    USE SIGNAL ;
    PORT
      LAYER MET3 ;
        RECT 70.250 34.450 70.800 34.550 ;
    END
  END Tile_X0Y1_W1END_3
  PIN Tile_X0Y1_W2MID_0
    DIRECTION INPUT ;
    USE SIGNAL ;
    PORT
      LAYER MET3 ;
        RECT 70.250 35.050 70.800 35.150 ;
    END
  END Tile_X0Y1_W2MID_0
  PIN Tile_X0Y1_W2MID_1
    DIRECTION INPUT ;
    USE SIGNAL ;
    PORT
      LAYER MET3 ;
        RECT 70.250 35.650 70.800 35.750 ;
    END
  END Tile_X0Y1_W2MID_1
  PIN Tile_X0Y1_W2MID_2
    DIRECTION INPUT ;
    USE SIGNAL ;
    PORT
      LAYER MET3 ;
        RECT 70.250 36.250 70.800 36.350 ;
    END
  END Tile_X0Y1_W2MID_2
  PIN Tile_X0Y1_W2MID_3
    DIRECTION INPUT ;
    USE SIGNAL ;
    PORT
      LAYER MET3 ;
        RECT 70.250 36.850 70.800 36.950 ;
    END
  END Tile_X0Y1_W2MID_3
  PIN Tile_X0Y1_W2MID_4
    DIRECTION INPUT ;
    USE SIGNAL ;
    PORT
      LAYER MET3 ;
        RECT 70.250 37.450 70.800 37.550 ;
    END
  END Tile_X0Y1_W2MID_4
  PIN Tile_X0Y1_W2MID_5
    DIRECTION INPUT ;
    USE SIGNAL ;
    PORT
      LAYER MET3 ;
        RECT 70.250 38.050 70.800 38.150 ;
    END
  END Tile_X0Y1_W2MID_5
  PIN Tile_X0Y1_W2MID_6
    DIRECTION INPUT ;
    USE SIGNAL ;
    PORT
      LAYER MET3 ;
        RECT 70.250 38.650 70.800 38.750 ;
    END
  END Tile_X0Y1_W2MID_6
  PIN Tile_X0Y1_W2MID_7
    DIRECTION INPUT ;
    USE SIGNAL ;
    PORT
      LAYER MET3 ;
        RECT 70.250 39.250 70.800 39.350 ;
    END
  END Tile_X0Y1_W2MID_7
  PIN Tile_X0Y1_W2END_0
    DIRECTION INPUT ;
    USE SIGNAL ;
    PORT
      LAYER MET3 ;
        RECT 70.250 39.850 70.800 39.950 ;
    END
  END Tile_X0Y1_W2END_0
  PIN Tile_X0Y1_W2END_1
    DIRECTION INPUT ;
    USE SIGNAL ;
    PORT
      LAYER MET3 ;
        RECT 70.250 40.450 70.800 40.550 ;
    END
  END Tile_X0Y1_W2END_1
  PIN Tile_X0Y1_W2END_2
    DIRECTION INPUT ;
    USE SIGNAL ;
    PORT
      LAYER MET3 ;
        RECT 70.250 41.050 70.800 41.150 ;
    END
  END Tile_X0Y1_W2END_2
  PIN Tile_X0Y1_W2END_3
    DIRECTION INPUT ;
    USE SIGNAL ;
    PORT
      LAYER MET3 ;
        RECT 70.250 41.650 70.800 41.750 ;
    END
  END Tile_X0Y1_W2END_3
  PIN Tile_X0Y1_W2END_4
    DIRECTION INPUT ;
    USE SIGNAL ;
    PORT
      LAYER MET3 ;
        RECT 70.250 42.250 70.800 42.350 ;
    END
  END Tile_X0Y1_W2END_4
  PIN Tile_X0Y1_W2END_5
    DIRECTION INPUT ;
    USE SIGNAL ;
    PORT
      LAYER MET3 ;
        RECT 70.250 42.850 70.800 42.950 ;
    END
  END Tile_X0Y1_W2END_5
  PIN Tile_X0Y1_W2END_6
    DIRECTION INPUT ;
    USE SIGNAL ;
    PORT
      LAYER MET3 ;
        RECT 70.250 43.450 70.800 43.550 ;
    END
  END Tile_X0Y1_W2END_6
  PIN Tile_X0Y1_W2END_7
    DIRECTION INPUT ;
    USE SIGNAL ;
    PORT
      LAYER MET3 ;
        RECT 70.250 44.050 70.800 44.150 ;
    END
  END Tile_X0Y1_W2END_7
  PIN Tile_X0Y1_WW4END_0
    DIRECTION INPUT ;
    USE SIGNAL ;
    PORT
      LAYER MET3 ;
        RECT 70.250 44.650 70.800 44.750 ;
    END
  END Tile_X0Y1_WW4END_0
  PIN Tile_X0Y1_WW4END_1
    DIRECTION INPUT ;
    USE SIGNAL ;
    PORT
      LAYER MET3 ;
        RECT 70.250 45.250 70.800 45.350 ;
    END
  END Tile_X0Y1_WW4END_1
  PIN Tile_X0Y1_WW4END_2
    DIRECTION INPUT ;
    USE SIGNAL ;
    PORT
      LAYER MET3 ;
        RECT 70.250 45.850 70.800 45.950 ;
    END
  END Tile_X0Y1_WW4END_2
  PIN Tile_X0Y1_WW4END_3
    DIRECTION INPUT ;
    USE SIGNAL ;
    PORT
      LAYER MET3 ;
        RECT 70.250 46.450 70.800 46.550 ;
    END
  END Tile_X0Y1_WW4END_3
  PIN Tile_X0Y1_WW4END_4
    DIRECTION INPUT ;
    USE SIGNAL ;
    PORT
      LAYER MET3 ;
        RECT 70.250 47.050 70.800 47.150 ;
    END
  END Tile_X0Y1_WW4END_4
  PIN Tile_X0Y1_WW4END_5
    DIRECTION INPUT ;
    USE SIGNAL ;
    PORT
      LAYER MET3 ;
        RECT 70.250 47.650 70.800 47.750 ;
    END
  END Tile_X0Y1_WW4END_5
  PIN Tile_X0Y1_WW4END_6
    DIRECTION INPUT ;
    USE SIGNAL ;
    PORT
      LAYER MET3 ;
        RECT 70.250 48.250 70.800 48.350 ;
    END
  END Tile_X0Y1_WW4END_6
  PIN Tile_X0Y1_WW4END_7
    DIRECTION INPUT ;
    USE SIGNAL ;
    PORT
      LAYER MET3 ;
        RECT 70.250 48.850 70.800 48.950 ;
    END
  END Tile_X0Y1_WW4END_7
  PIN Tile_X0Y1_WW4END_8
    DIRECTION INPUT ;
    USE SIGNAL ;
    PORT
      LAYER MET3 ;
        RECT 70.250 49.450 70.800 49.550 ;
    END
  END Tile_X0Y1_WW4END_8
  PIN Tile_X0Y1_WW4END_9
    DIRECTION INPUT ;
    USE SIGNAL ;
    PORT
      LAYER MET3 ;
        RECT 70.250 50.050 70.800 50.150 ;
    END
  END Tile_X0Y1_WW4END_9
  PIN Tile_X0Y1_WW4END_10
    DIRECTION INPUT ;
    USE SIGNAL ;
    PORT
      LAYER MET3 ;
        RECT 70.250 50.650 70.800 50.750 ;
    END
  END Tile_X0Y1_WW4END_10
  PIN Tile_X0Y1_WW4END_11
    DIRECTION INPUT ;
    USE SIGNAL ;
    PORT
      LAYER MET3 ;
        RECT 70.250 51.250 70.800 51.350 ;
    END
  END Tile_X0Y1_WW4END_11
  PIN Tile_X0Y1_WW4END_12
    DIRECTION INPUT ;
    USE SIGNAL ;
    PORT
      LAYER MET3 ;
        RECT 70.250 51.850 70.800 51.950 ;
    END
  END Tile_X0Y1_WW4END_12
  PIN Tile_X0Y1_WW4END_13
    DIRECTION INPUT ;
    USE SIGNAL ;
    PORT
      LAYER MET3 ;
        RECT 70.250 52.450 70.800 52.550 ;
    END
  END Tile_X0Y1_WW4END_13
  PIN Tile_X0Y1_WW4END_14
    DIRECTION INPUT ;
    USE SIGNAL ;
    PORT
      LAYER MET3 ;
        RECT 70.250 53.050 70.800 53.150 ;
    END
  END Tile_X0Y1_WW4END_14
  PIN Tile_X0Y1_WW4END_15
    DIRECTION INPUT ;
    USE SIGNAL ;
    PORT
      LAYER MET3 ;
        RECT 70.250 53.650 70.800 53.750 ;
    END
  END Tile_X0Y1_WW4END_15
  PIN Tile_X0Y1_W6END_0
    DIRECTION INPUT ;
    USE SIGNAL ;
    PORT
      LAYER MET3 ;
        RECT 70.250 54.250 70.800 54.350 ;
    END
  END Tile_X0Y1_W6END_0
  PIN Tile_X0Y1_W6END_1
    DIRECTION INPUT ;
    USE SIGNAL ;
    PORT
      LAYER MET3 ;
        RECT 70.250 54.850 70.800 54.950 ;
    END
  END Tile_X0Y1_W6END_1
  PIN Tile_X0Y1_W6END_2
    DIRECTION INPUT ;
    USE SIGNAL ;
    PORT
      LAYER MET3 ;
        RECT 70.250 55.450 70.800 55.550 ;
    END
  END Tile_X0Y1_W6END_2
  PIN Tile_X0Y1_W6END_3
    DIRECTION INPUT ;
    USE SIGNAL ;
    PORT
      LAYER MET3 ;
        RECT 70.250 56.050 70.800 56.150 ;
    END
  END Tile_X0Y1_W6END_3
  PIN Tile_X0Y1_W6END_4
    DIRECTION INPUT ;
    USE SIGNAL ;
    PORT
      LAYER MET3 ;
        RECT 70.250 56.650 70.800 56.750 ;
    END
  END Tile_X0Y1_W6END_4
  PIN Tile_X0Y1_W6END_5
    DIRECTION INPUT ;
    USE SIGNAL ;
    PORT
      LAYER MET3 ;
        RECT 70.250 57.250 70.800 57.350 ;
    END
  END Tile_X0Y1_W6END_5
  PIN Tile_X0Y1_W6END_6
    DIRECTION INPUT ;
    USE SIGNAL ;
    PORT
      LAYER MET3 ;
        RECT 70.250 57.850 70.800 57.950 ;
    END
  END Tile_X0Y1_W6END_6
  PIN Tile_X0Y1_W6END_7
    DIRECTION INPUT ;
    USE SIGNAL ;
    PORT
      LAYER MET3 ;
        RECT 70.250 58.450 70.800 58.550 ;
    END
  END Tile_X0Y1_W6END_7
  PIN Tile_X0Y1_W6END_8
    DIRECTION INPUT ;
    USE SIGNAL ;
    PORT
      LAYER MET3 ;
        RECT 70.250 59.050 70.800 59.150 ;
    END
  END Tile_X0Y1_W6END_8
  PIN Tile_X0Y1_W6END_9
    DIRECTION INPUT ;
    USE SIGNAL ;
    PORT
      LAYER MET3 ;
        RECT 70.250 59.650 70.800 59.750 ;
    END
  END Tile_X0Y1_W6END_9
  PIN Tile_X0Y1_W6END_10
    DIRECTION INPUT ;
    USE SIGNAL ;
    PORT
      LAYER MET3 ;
        RECT 70.250 60.250 70.800 60.350 ;
    END
  END Tile_X0Y1_W6END_10
  PIN Tile_X0Y1_W6END_11
    DIRECTION INPUT ;
    USE SIGNAL ;
    PORT
      LAYER MET3 ;
        RECT 70.250 60.850 70.800 60.950 ;
    END
  END Tile_X0Y1_W6END_11
  PIN Tile_X0Y1_N_GBUF_END_0
    DIRECTION INPUT ;
    USE SIGNAL ;
    PORT
      LAYER MET4 ;
        RECT 4.050 0.000 4.150 0.550 ;
    END
  END Tile_X0Y1_N_GBUF_END_0
  PIN Tile_X0Y1_N_GBUF_END_1
    DIRECTION INPUT ;
    USE SIGNAL ;
    PORT
      LAYER MET4 ;
        RECT 4.450 0.000 4.550 0.550 ;
    END
  END Tile_X0Y1_N_GBUF_END_1
  PIN Tile_X0Y1_N_GBUF_END_2
    DIRECTION INPUT ;
    USE SIGNAL ;
    PORT
      LAYER MET4 ;
        RECT 4.850 0.000 4.950 0.550 ;
    END
  END Tile_X0Y1_N_GBUF_END_2
  PIN Tile_X0Y1_N_GBUF_END_3
    DIRECTION INPUT ;
    USE SIGNAL ;
    PORT
      LAYER MET4 ;
        RECT 5.250 0.000 5.350 0.550 ;
    END
  END Tile_X0Y1_N_GBUF_END_3
  PIN Tile_X0Y1_N1END_0
    DIRECTION INPUT ;
    USE SIGNAL ;
    PORT
      LAYER MET4 ;
        RECT 5.650 0.000 5.750 0.550 ;
    END
  END Tile_X0Y1_N1END_0
  PIN Tile_X0Y1_N1END_1
    DIRECTION INPUT ;
    USE SIGNAL ;
    PORT
      LAYER MET4 ;
        RECT 6.050 0.000 6.150 0.550 ;
    END
  END Tile_X0Y1_N1END_1
  PIN Tile_X0Y1_N1END_2
    DIRECTION INPUT ;
    USE SIGNAL ;
    PORT
      LAYER MET4 ;
        RECT 6.450 0.000 6.550 0.550 ;
    END
  END Tile_X0Y1_N1END_2
  PIN Tile_X0Y1_N1END_3
    DIRECTION INPUT ;
    USE SIGNAL ;
    PORT
      LAYER MET4 ;
        RECT 6.850 0.000 6.950 0.550 ;
    END
  END Tile_X0Y1_N1END_3
  PIN Tile_X0Y1_N2MID_0
    DIRECTION INPUT ;
    USE SIGNAL ;
    PORT
      LAYER MET4 ;
        RECT 7.250 0.000 7.350 0.550 ;
    END
  END Tile_X0Y1_N2MID_0
  PIN Tile_X0Y1_N2MID_1
    DIRECTION INPUT ;
    USE SIGNAL ;
    PORT
      LAYER MET4 ;
        RECT 7.650 0.000 7.750 0.550 ;
    END
  END Tile_X0Y1_N2MID_1
  PIN Tile_X0Y1_N2MID_2
    DIRECTION INPUT ;
    USE SIGNAL ;
    PORT
      LAYER MET4 ;
        RECT 8.050 0.000 8.150 0.550 ;
    END
  END Tile_X0Y1_N2MID_2
  PIN Tile_X0Y1_N2MID_3
    DIRECTION INPUT ;
    USE SIGNAL ;
    PORT
      LAYER MET4 ;
        RECT 8.450 0.000 8.550 0.550 ;
    END
  END Tile_X0Y1_N2MID_3
  PIN Tile_X0Y1_N2MID_4
    DIRECTION INPUT ;
    USE SIGNAL ;
    PORT
      LAYER MET4 ;
        RECT 8.850 0.000 8.950 0.550 ;
    END
  END Tile_X0Y1_N2MID_4
  PIN Tile_X0Y1_N2MID_5
    DIRECTION INPUT ;
    USE SIGNAL ;
    PORT
      LAYER MET4 ;
        RECT 9.250 0.000 9.350 0.550 ;
    END
  END Tile_X0Y1_N2MID_5
  PIN Tile_X0Y1_N2MID_6
    DIRECTION INPUT ;
    USE SIGNAL ;
    PORT
      LAYER MET4 ;
        RECT 9.650 0.000 9.750 0.550 ;
    END
  END Tile_X0Y1_N2MID_6
  PIN Tile_X0Y1_N2MID_7
    DIRECTION INPUT ;
    USE SIGNAL ;
    PORT
      LAYER MET4 ;
        RECT 10.050 0.000 10.150 0.550 ;
    END
  END Tile_X0Y1_N2MID_7
  PIN Tile_X0Y1_N2END_0
    DIRECTION INPUT ;
    USE SIGNAL ;
    PORT
      LAYER MET4 ;
        RECT 10.450 0.000 10.550 0.550 ;
    END
  END Tile_X0Y1_N2END_0
  PIN Tile_X0Y1_N2END_1
    DIRECTION INPUT ;
    USE SIGNAL ;
    PORT
      LAYER MET4 ;
        RECT 12.450 0.000 12.550 0.550 ;
    END
  END Tile_X0Y1_N2END_1
  PIN Tile_X0Y1_N2END_2
    DIRECTION INPUT ;
    USE SIGNAL ;
    PORT
      LAYER MET4 ;
        RECT 12.850 0.000 12.950 0.550 ;
    END
  END Tile_X0Y1_N2END_2
  PIN Tile_X0Y1_N2END_3
    DIRECTION INPUT ;
    USE SIGNAL ;
    PORT
      LAYER MET4 ;
        RECT 13.250 0.000 13.350 0.550 ;
    END
  END Tile_X0Y1_N2END_3
  PIN Tile_X0Y1_N2END_4
    DIRECTION INPUT ;
    USE SIGNAL ;
    PORT
      LAYER MET4 ;
        RECT 13.650 0.000 13.750 0.550 ;
    END
  END Tile_X0Y1_N2END_4
  PIN Tile_X0Y1_N2END_5
    DIRECTION INPUT ;
    USE SIGNAL ;
    PORT
      LAYER MET4 ;
        RECT 14.050 0.000 14.150 0.550 ;
    END
  END Tile_X0Y1_N2END_5
  PIN Tile_X0Y1_N2END_6
    DIRECTION INPUT ;
    USE SIGNAL ;
    PORT
      LAYER MET4 ;
        RECT 14.450 0.000 14.550 0.550 ;
    END
  END Tile_X0Y1_N2END_6
  PIN Tile_X0Y1_N2END_7
    DIRECTION INPUT ;
    USE SIGNAL ;
    PORT
      LAYER MET4 ;
        RECT 14.850 0.000 14.950 0.550 ;
    END
  END Tile_X0Y1_N2END_7
  PIN Tile_X0Y1_N4END_0
    DIRECTION INPUT ;
    USE SIGNAL ;
    PORT
      LAYER MET4 ;
        RECT 15.250 0.000 15.350 0.550 ;
    END
  END Tile_X0Y1_N4END_0
  PIN Tile_X0Y1_N4END_1
    DIRECTION INPUT ;
    USE SIGNAL ;
    PORT
      LAYER MET4 ;
        RECT 15.650 0.000 15.750 0.550 ;
    END
  END Tile_X0Y1_N4END_1
  PIN Tile_X0Y1_N4END_2
    DIRECTION INPUT ;
    USE SIGNAL ;
    PORT
      LAYER MET4 ;
        RECT 16.050 0.000 16.150 0.550 ;
    END
  END Tile_X0Y1_N4END_2
  PIN Tile_X0Y1_N4END_3
    DIRECTION INPUT ;
    USE SIGNAL ;
    PORT
      LAYER MET4 ;
        RECT 16.450 0.000 16.550 0.550 ;
    END
  END Tile_X0Y1_N4END_3
  PIN Tile_X0Y1_N4END_4
    DIRECTION INPUT ;
    USE SIGNAL ;
    PORT
      LAYER MET4 ;
        RECT 16.850 0.000 16.950 0.550 ;
    END
  END Tile_X0Y1_N4END_4
  PIN Tile_X0Y1_N4END_5
    DIRECTION INPUT ;
    USE SIGNAL ;
    PORT
      LAYER MET4 ;
        RECT 17.250 0.000 17.350 0.550 ;
    END
  END Tile_X0Y1_N4END_5
  PIN Tile_X0Y1_N4END_6
    DIRECTION INPUT ;
    USE SIGNAL ;
    PORT
      LAYER MET4 ;
        RECT 17.650 0.000 17.750 0.550 ;
    END
  END Tile_X0Y1_N4END_6
  PIN Tile_X0Y1_N4END_7
    DIRECTION INPUT ;
    USE SIGNAL ;
    PORT
      LAYER MET4 ;
        RECT 18.050 0.000 18.150 0.550 ;
    END
  END Tile_X0Y1_N4END_7
  PIN Tile_X0Y1_N4END_8
    DIRECTION INPUT ;
    USE SIGNAL ;
    PORT
      LAYER MET4 ;
        RECT 18.450 0.000 18.550 0.550 ;
    END
  END Tile_X0Y1_N4END_8
  PIN Tile_X0Y1_N4END_9
    DIRECTION INPUT ;
    USE SIGNAL ;
    PORT
      LAYER MET4 ;
        RECT 18.850 0.000 18.950 0.550 ;
    END
  END Tile_X0Y1_N4END_9
  PIN Tile_X0Y1_N4END_10
    DIRECTION INPUT ;
    USE SIGNAL ;
    PORT
      LAYER MET4 ;
        RECT 20.850 0.000 20.950 0.550 ;
    END
  END Tile_X0Y1_N4END_10
  PIN Tile_X0Y1_N4END_11
    DIRECTION INPUT ;
    USE SIGNAL ;
    PORT
      LAYER MET4 ;
        RECT 21.250 0.000 21.350 0.550 ;
    END
  END Tile_X0Y1_N4END_11
  PIN Tile_X0Y1_N4END_12
    DIRECTION INPUT ;
    USE SIGNAL ;
    PORT
      LAYER MET4 ;
        RECT 21.650 0.000 21.750 0.550 ;
    END
  END Tile_X0Y1_N4END_12
  PIN Tile_X0Y1_N4END_13
    DIRECTION INPUT ;
    USE SIGNAL ;
    PORT
      LAYER MET4 ;
        RECT 22.050 0.000 22.150 0.550 ;
    END
  END Tile_X0Y1_N4END_13
  PIN Tile_X0Y1_N4END_14
    DIRECTION INPUT ;
    USE SIGNAL ;
    PORT
      LAYER MET4 ;
        RECT 22.450 0.000 22.550 0.550 ;
    END
  END Tile_X0Y1_N4END_14
  PIN Tile_X0Y1_N4END_15
    DIRECTION INPUT ;
    USE SIGNAL ;
    PORT
      LAYER MET4 ;
        RECT 22.850 0.000 22.950 0.550 ;
    END
  END Tile_X0Y1_N4END_15
  PIN Tile_X0Y1_NN4END_0
    DIRECTION INPUT ;
    USE SIGNAL ;
    PORT
      LAYER MET4 ;
        RECT 23.250 0.000 23.350 0.550 ;
    END
  END Tile_X0Y1_NN4END_0
  PIN Tile_X0Y1_NN4END_1
    DIRECTION INPUT ;
    USE SIGNAL ;
    PORT
      LAYER MET4 ;
        RECT 23.650 0.000 23.750 0.550 ;
    END
  END Tile_X0Y1_NN4END_1
  PIN Tile_X0Y1_NN4END_2
    DIRECTION INPUT ;
    USE SIGNAL ;
    PORT
      LAYER MET4 ;
        RECT 24.050 0.000 24.150 0.550 ;
    END
  END Tile_X0Y1_NN4END_2
  PIN Tile_X0Y1_NN4END_3
    DIRECTION INPUT ;
    USE SIGNAL ;
    PORT
      LAYER MET4 ;
        RECT 24.450 0.000 24.550 0.550 ;
    END
  END Tile_X0Y1_NN4END_3
  PIN Tile_X0Y1_NN4END_4
    DIRECTION INPUT ;
    USE SIGNAL ;
    PORT
      LAYER MET4 ;
        RECT 24.850 0.000 24.950 0.550 ;
    END
  END Tile_X0Y1_NN4END_4
  PIN Tile_X0Y1_NN4END_5
    DIRECTION INPUT ;
    USE SIGNAL ;
    PORT
      LAYER MET4 ;
        RECT 25.250 0.000 25.350 0.550 ;
    END
  END Tile_X0Y1_NN4END_5
  PIN Tile_X0Y1_NN4END_6
    DIRECTION INPUT ;
    USE SIGNAL ;
    PORT
      LAYER MET4 ;
        RECT 25.650 0.000 25.750 0.550 ;
    END
  END Tile_X0Y1_NN4END_6
  PIN Tile_X0Y1_NN4END_7
    DIRECTION INPUT ;
    USE SIGNAL ;
    PORT
      LAYER MET4 ;
        RECT 26.050 0.000 26.150 0.550 ;
    END
  END Tile_X0Y1_NN4END_7
  PIN Tile_X0Y1_NN4END_8
    DIRECTION INPUT ;
    USE SIGNAL ;
    PORT
      LAYER MET4 ;
        RECT 26.450 0.000 26.550 0.550 ;
    END
  END Tile_X0Y1_NN4END_8
  PIN Tile_X0Y1_NN4END_9
    DIRECTION INPUT ;
    USE SIGNAL ;
    PORT
      LAYER MET4 ;
        RECT 26.850 0.000 26.950 0.550 ;
    END
  END Tile_X0Y1_NN4END_9
  PIN Tile_X0Y1_NN4END_10
    DIRECTION INPUT ;
    USE SIGNAL ;
    PORT
      LAYER MET4 ;
        RECT 27.250 0.000 27.350 0.550 ;
    END
  END Tile_X0Y1_NN4END_10
  PIN Tile_X0Y1_NN4END_11
    DIRECTION INPUT ;
    USE SIGNAL ;
    PORT
      LAYER MET4 ;
        RECT 29.250 0.000 29.350 0.550 ;
    END
  END Tile_X0Y1_NN4END_11
  PIN Tile_X0Y1_NN4END_12
    DIRECTION INPUT ;
    USE SIGNAL ;
    PORT
      LAYER MET4 ;
        RECT 29.650 0.000 29.750 0.550 ;
    END
  END Tile_X0Y1_NN4END_12
  PIN Tile_X0Y1_NN4END_13
    DIRECTION INPUT ;
    USE SIGNAL ;
    PORT
      LAYER MET4 ;
        RECT 30.050 0.000 30.150 0.550 ;
    END
  END Tile_X0Y1_NN4END_13
  PIN Tile_X0Y1_NN4END_14
    DIRECTION INPUT ;
    USE SIGNAL ;
    PORT
      LAYER MET4 ;
        RECT 30.450 0.000 30.550 0.550 ;
    END
  END Tile_X0Y1_NN4END_14
  PIN Tile_X0Y1_NN4END_15
    DIRECTION INPUT ;
    USE SIGNAL ;
    PORT
      LAYER MET4 ;
        RECT 30.850 0.000 30.950 0.550 ;
    END
  END Tile_X0Y1_NN4END_15
  PIN Tile_X0Y1_S1BEG_0
    DIRECTION OUTPUT ;
    USE SIGNAL ;
    PORT
      LAYER MET4 ;
        RECT 31.650 0.000 31.750 0.550 ;
    END
  END Tile_X0Y1_S1BEG_0
  PIN Tile_X0Y1_S1BEG_1
    DIRECTION OUTPUT ;
    USE SIGNAL ;
    PORT
      LAYER MET4 ;
        RECT 32.050 0.000 32.150 0.550 ;
    END
  END Tile_X0Y1_S1BEG_1
  PIN Tile_X0Y1_S1BEG_2
    DIRECTION OUTPUT ;
    USE SIGNAL ;
    PORT
      LAYER MET4 ;
        RECT 32.450 0.000 32.550 0.550 ;
    END
  END Tile_X0Y1_S1BEG_2
  PIN Tile_X0Y1_S1BEG_3
    DIRECTION OUTPUT ;
    USE SIGNAL ;
    PORT
      LAYER MET4 ;
        RECT 32.850 0.000 32.950 0.550 ;
    END
  END Tile_X0Y1_S1BEG_3
  PIN Tile_X0Y1_S2BEG_0
    DIRECTION OUTPUT ;
    USE SIGNAL ;
    PORT
      LAYER MET4 ;
        RECT 33.250 0.000 33.350 0.550 ;
    END
  END Tile_X0Y1_S2BEG_0
  PIN Tile_X0Y1_S2BEG_1
    DIRECTION OUTPUT ;
    USE SIGNAL ;
    PORT
      LAYER MET4 ;
        RECT 33.650 0.000 33.750 0.550 ;
    END
  END Tile_X0Y1_S2BEG_1
  PIN Tile_X0Y1_S2BEG_2
    DIRECTION OUTPUT ;
    USE SIGNAL ;
    PORT
      LAYER MET4 ;
        RECT 34.050 0.000 34.150 0.550 ;
    END
  END Tile_X0Y1_S2BEG_2
  PIN Tile_X0Y1_S2BEG_3
    DIRECTION OUTPUT ;
    USE SIGNAL ;
    PORT
      LAYER MET4 ;
        RECT 34.450 0.000 34.550 0.550 ;
    END
  END Tile_X0Y1_S2BEG_3
  PIN Tile_X0Y1_S2BEG_4
    DIRECTION OUTPUT ;
    USE SIGNAL ;
    PORT
      LAYER MET4 ;
        RECT 34.850 0.000 34.950 0.550 ;
    END
  END Tile_X0Y1_S2BEG_4
  PIN Tile_X0Y1_S2BEG_5
    DIRECTION OUTPUT ;
    USE SIGNAL ;
    PORT
      LAYER MET4 ;
        RECT 35.250 0.000 35.350 0.550 ;
    END
  END Tile_X0Y1_S2BEG_5
  PIN Tile_X0Y1_S2BEG_6
    DIRECTION OUTPUT ;
    USE SIGNAL ;
    PORT
      LAYER MET4 ;
        RECT 35.650 0.000 35.750 0.550 ;
    END
  END Tile_X0Y1_S2BEG_6
  PIN Tile_X0Y1_S2BEG_7
    DIRECTION OUTPUT ;
    USE SIGNAL ;
    PORT
      LAYER MET4 ;
        RECT 37.650 0.000 37.750 0.550 ;
    END
  END Tile_X0Y1_S2BEG_7
  PIN Tile_X0Y1_S2BEGb_0
    DIRECTION OUTPUT ;
    USE SIGNAL ;
    PORT
      LAYER MET4 ;
        RECT 38.050 0.000 38.150 0.550 ;
    END
  END Tile_X0Y1_S2BEGb_0
  PIN Tile_X0Y1_S2BEGb_1
    DIRECTION OUTPUT ;
    USE SIGNAL ;
    PORT
      LAYER MET4 ;
        RECT 38.450 0.000 38.550 0.550 ;
    END
  END Tile_X0Y1_S2BEGb_1
  PIN Tile_X0Y1_S2BEGb_2
    DIRECTION OUTPUT ;
    USE SIGNAL ;
    PORT
      LAYER MET4 ;
        RECT 38.850 0.000 38.950 0.550 ;
    END
  END Tile_X0Y1_S2BEGb_2
  PIN Tile_X0Y1_S2BEGb_3
    DIRECTION OUTPUT ;
    USE SIGNAL ;
    PORT
      LAYER MET4 ;
        RECT 39.250 0.000 39.350 0.550 ;
    END
  END Tile_X0Y1_S2BEGb_3
  PIN Tile_X0Y1_S2BEGb_4
    DIRECTION OUTPUT ;
    USE SIGNAL ;
    PORT
      LAYER MET4 ;
        RECT 39.650 0.000 39.750 0.550 ;
    END
  END Tile_X0Y1_S2BEGb_4
  PIN Tile_X0Y1_S2BEGb_5
    DIRECTION OUTPUT ;
    USE SIGNAL ;
    PORT
      LAYER MET4 ;
        RECT 40.050 0.000 40.150 0.550 ;
    END
  END Tile_X0Y1_S2BEGb_5
  PIN Tile_X0Y1_S2BEGb_6
    DIRECTION OUTPUT ;
    USE SIGNAL ;
    PORT
      LAYER MET4 ;
        RECT 40.450 0.000 40.550 0.550 ;
    END
  END Tile_X0Y1_S2BEGb_6
  PIN Tile_X0Y1_S2BEGb_7
    DIRECTION OUTPUT ;
    USE SIGNAL ;
    PORT
      LAYER MET4 ;
        RECT 40.850 0.000 40.950 0.550 ;
    END
  END Tile_X0Y1_S2BEGb_7
  PIN Tile_X0Y1_S4BEG_0
    DIRECTION OUTPUT ;
    USE SIGNAL ;
    PORT
      LAYER MET4 ;
        RECT 41.250 0.000 41.350 0.550 ;
    END
  END Tile_X0Y1_S4BEG_0
  PIN Tile_X0Y1_S4BEG_1
    DIRECTION OUTPUT ;
    USE SIGNAL ;
    PORT
      LAYER MET4 ;
        RECT 41.650 0.000 41.750 0.550 ;
    END
  END Tile_X0Y1_S4BEG_1
  PIN Tile_X0Y1_S4BEG_2
    DIRECTION OUTPUT ;
    USE SIGNAL ;
    PORT
      LAYER MET4 ;
        RECT 42.050 0.000 42.150 0.550 ;
    END
  END Tile_X0Y1_S4BEG_2
  PIN Tile_X0Y1_S4BEG_3
    DIRECTION OUTPUT ;
    USE SIGNAL ;
    PORT
      LAYER MET4 ;
        RECT 42.450 0.000 42.550 0.550 ;
    END
  END Tile_X0Y1_S4BEG_3
  PIN Tile_X0Y1_S4BEG_4
    DIRECTION OUTPUT ;
    USE SIGNAL ;
    PORT
      LAYER MET4 ;
        RECT 42.850 0.000 42.950 0.550 ;
    END
  END Tile_X0Y1_S4BEG_4
  PIN Tile_X0Y1_S4BEG_5
    DIRECTION OUTPUT ;
    USE SIGNAL ;
    PORT
      LAYER MET4 ;
        RECT 43.250 0.000 43.350 0.550 ;
    END
  END Tile_X0Y1_S4BEG_5
  PIN Tile_X0Y1_S4BEG_6
    DIRECTION OUTPUT ;
    USE SIGNAL ;
    PORT
      LAYER MET4 ;
        RECT 43.650 0.000 43.750 0.550 ;
    END
  END Tile_X0Y1_S4BEG_6
  PIN Tile_X0Y1_S4BEG_7
    DIRECTION OUTPUT ;
    USE SIGNAL ;
    PORT
      LAYER MET4 ;
        RECT 44.050 0.000 44.150 0.550 ;
    END
  END Tile_X0Y1_S4BEG_7
  PIN Tile_X0Y1_S4BEG_8
    DIRECTION OUTPUT ;
    USE SIGNAL ;
    PORT
      LAYER MET4 ;
        RECT 46.050 0.000 46.150 0.550 ;
    END
  END Tile_X0Y1_S4BEG_8
  PIN Tile_X0Y1_S4BEG_9
    DIRECTION OUTPUT ;
    USE SIGNAL ;
    PORT
      LAYER MET4 ;
        RECT 46.450 0.000 46.550 0.550 ;
    END
  END Tile_X0Y1_S4BEG_9
  PIN Tile_X0Y1_S4BEG_10
    DIRECTION OUTPUT ;
    USE SIGNAL ;
    PORT
      LAYER MET4 ;
        RECT 46.850 0.000 46.950 0.550 ;
    END
  END Tile_X0Y1_S4BEG_10
  PIN Tile_X0Y1_S4BEG_11
    DIRECTION OUTPUT ;
    USE SIGNAL ;
    PORT
      LAYER MET4 ;
        RECT 47.250 0.000 47.350 0.550 ;
    END
  END Tile_X0Y1_S4BEG_11
  PIN Tile_X0Y1_S4BEG_12
    DIRECTION OUTPUT ;
    USE SIGNAL ;
    PORT
      LAYER MET4 ;
        RECT 47.650 0.000 47.750 0.550 ;
    END
  END Tile_X0Y1_S4BEG_12
  PIN Tile_X0Y1_S4BEG_13
    DIRECTION OUTPUT ;
    USE SIGNAL ;
    PORT
      LAYER MET4 ;
        RECT 48.050 0.000 48.150 0.550 ;
    END
  END Tile_X0Y1_S4BEG_13
  PIN Tile_X0Y1_S4BEG_14
    DIRECTION OUTPUT ;
    USE SIGNAL ;
    PORT
      LAYER MET4 ;
        RECT 48.450 0.000 48.550 0.550 ;
    END
  END Tile_X0Y1_S4BEG_14
  PIN Tile_X0Y1_S4BEG_15
    DIRECTION OUTPUT ;
    USE SIGNAL ;
    PORT
      LAYER MET4 ;
        RECT 48.850 0.000 48.950 0.550 ;
    END
  END Tile_X0Y1_S4BEG_15
  PIN Tile_X0Y1_SS4BEG_0
    DIRECTION OUTPUT ;
    USE SIGNAL ;
    PORT
      LAYER MET4 ;
        RECT 49.250 0.000 49.350 0.550 ;
    END
  END Tile_X0Y1_SS4BEG_0
  PIN Tile_X0Y1_SS4BEG_1
    DIRECTION OUTPUT ;
    USE SIGNAL ;
    PORT
      LAYER MET4 ;
        RECT 49.650 0.000 49.750 0.550 ;
    END
  END Tile_X0Y1_SS4BEG_1
  PIN Tile_X0Y1_SS4BEG_2
    DIRECTION OUTPUT ;
    USE SIGNAL ;
    PORT
      LAYER MET4 ;
        RECT 50.050 0.000 50.150 0.550 ;
    END
  END Tile_X0Y1_SS4BEG_2
  PIN Tile_X0Y1_SS4BEG_3
    DIRECTION OUTPUT ;
    USE SIGNAL ;
    PORT
      LAYER MET4 ;
        RECT 50.450 0.000 50.550 0.550 ;
    END
  END Tile_X0Y1_SS4BEG_3
  PIN Tile_X0Y1_SS4BEG_4
    DIRECTION OUTPUT ;
    USE SIGNAL ;
    PORT
      LAYER MET4 ;
        RECT 50.850 0.000 50.950 0.550 ;
    END
  END Tile_X0Y1_SS4BEG_4
  PIN Tile_X0Y1_SS4BEG_5
    DIRECTION OUTPUT ;
    USE SIGNAL ;
    PORT
      LAYER MET4 ;
        RECT 51.250 0.000 51.350 0.550 ;
    END
  END Tile_X0Y1_SS4BEG_5
  PIN Tile_X0Y1_SS4BEG_6
    DIRECTION OUTPUT ;
    USE SIGNAL ;
    PORT
      LAYER MET4 ;
        RECT 51.650 0.000 51.750 0.550 ;
    END
  END Tile_X0Y1_SS4BEG_6
  PIN Tile_X0Y1_SS4BEG_7
    DIRECTION OUTPUT ;
    USE SIGNAL ;
    PORT
      LAYER MET4 ;
        RECT 52.050 0.000 52.150 0.550 ;
    END
  END Tile_X0Y1_SS4BEG_7
  PIN Tile_X0Y1_SS4BEG_8
    DIRECTION OUTPUT ;
    USE SIGNAL ;
    PORT
      LAYER MET4 ;
        RECT 52.450 0.000 52.550 0.550 ;
    END
  END Tile_X0Y1_SS4BEG_8
  PIN Tile_X0Y1_SS4BEG_9
    DIRECTION OUTPUT ;
    USE SIGNAL ;
    PORT
      LAYER MET4 ;
        RECT 54.450 0.000 54.550 0.550 ;
    END
  END Tile_X0Y1_SS4BEG_9
  PIN Tile_X0Y1_SS4BEG_10
    DIRECTION OUTPUT ;
    USE SIGNAL ;
    PORT
      LAYER MET4 ;
        RECT 54.850 0.000 54.950 0.550 ;
    END
  END Tile_X0Y1_SS4BEG_10
  PIN Tile_X0Y1_SS4BEG_11
    DIRECTION OUTPUT ;
    USE SIGNAL ;
    PORT
      LAYER MET4 ;
        RECT 55.250 0.000 55.350 0.550 ;
    END
  END Tile_X0Y1_SS4BEG_11
  PIN Tile_X0Y1_SS4BEG_12
    DIRECTION OUTPUT ;
    USE SIGNAL ;
    PORT
      LAYER MET4 ;
        RECT 55.650 0.000 55.750 0.550 ;
    END
  END Tile_X0Y1_SS4BEG_12
  PIN Tile_X0Y1_SS4BEG_13
    DIRECTION OUTPUT ;
    USE SIGNAL ;
    PORT
      LAYER MET4 ;
        RECT 56.050 0.000 56.150 0.550 ;
    END
  END Tile_X0Y1_SS4BEG_13
  PIN Tile_X0Y1_SS4BEG_14
    DIRECTION OUTPUT ;
    USE SIGNAL ;
    PORT
      LAYER MET4 ;
        RECT 56.450 0.000 56.550 0.550 ;
    END
  END Tile_X0Y1_SS4BEG_14
  PIN Tile_X0Y1_SS4BEG_15
    DIRECTION OUTPUT ;
    USE SIGNAL ;
    PORT
      LAYER MET4 ;
        RECT 56.850 0.000 56.950 0.550 ;
    END
  END Tile_X0Y1_SS4BEG_15
  PIN Tile_X0Y1_CI_0
    DIRECTION INPUT ;
    USE SIGNAL ;
    PORT
      LAYER MET4 ;
        RECT 31.250 0.000 31.350 0.550 ;
    END
  END Tile_X0Y1_CI_0
  PIN Tile_X0Y1_E1END_0
    DIRECTION INPUT ;
    USE SIGNAL ;
    PORT
      LAYER MET3 ;
        RECT 0.000 3.850 0.550 3.950 ;
    END
  END Tile_X0Y1_E1END_0
  PIN Tile_X0Y1_E1END_1
    DIRECTION INPUT ;
    USE SIGNAL ;
    PORT
      LAYER MET3 ;
        RECT 0.000 4.450 0.550 4.550 ;
    END
  END Tile_X0Y1_E1END_1
  PIN Tile_X0Y1_E1END_2
    DIRECTION INPUT ;
    USE SIGNAL ;
    PORT
      LAYER MET3 ;
        RECT 0.000 5.050 0.550 5.150 ;
    END
  END Tile_X0Y1_E1END_2
  PIN Tile_X0Y1_E1END_3
    DIRECTION INPUT ;
    USE SIGNAL ;
    PORT
      LAYER MET3 ;
        RECT 0.000 5.650 0.550 5.750 ;
    END
  END Tile_X0Y1_E1END_3
  PIN Tile_X0Y1_E2MID_0
    DIRECTION INPUT ;
    USE SIGNAL ;
    PORT
      LAYER MET3 ;
        RECT 0.000 6.250 0.550 6.350 ;
    END
  END Tile_X0Y1_E2MID_0
  PIN Tile_X0Y1_E2MID_1
    DIRECTION INPUT ;
    USE SIGNAL ;
    PORT
      LAYER MET3 ;
        RECT 0.000 6.850 0.550 6.950 ;
    END
  END Tile_X0Y1_E2MID_1
  PIN Tile_X0Y1_E2MID_2
    DIRECTION INPUT ;
    USE SIGNAL ;
    PORT
      LAYER MET3 ;
        RECT 0.000 7.450 0.550 7.550 ;
    END
  END Tile_X0Y1_E2MID_2
  PIN Tile_X0Y1_E2MID_3
    DIRECTION INPUT ;
    USE SIGNAL ;
    PORT
      LAYER MET3 ;
        RECT 0.000 8.050 0.550 8.150 ;
    END
  END Tile_X0Y1_E2MID_3
  PIN Tile_X0Y1_E2MID_4
    DIRECTION INPUT ;
    USE SIGNAL ;
    PORT
      LAYER MET3 ;
        RECT 0.000 8.650 0.550 8.750 ;
    END
  END Tile_X0Y1_E2MID_4
  PIN Tile_X0Y1_E2MID_5
    DIRECTION INPUT ;
    USE SIGNAL ;
    PORT
      LAYER MET3 ;
        RECT 0.000 9.250 0.550 9.350 ;
    END
  END Tile_X0Y1_E2MID_5
  PIN Tile_X0Y1_E2MID_6
    DIRECTION INPUT ;
    USE SIGNAL ;
    PORT
      LAYER MET3 ;
        RECT 0.000 9.850 0.550 9.950 ;
    END
  END Tile_X0Y1_E2MID_6
  PIN Tile_X0Y1_E2MID_7
    DIRECTION INPUT ;
    USE SIGNAL ;
    PORT
      LAYER MET3 ;
        RECT 0.000 10.450 0.550 10.550 ;
    END
  END Tile_X0Y1_E2MID_7
  PIN Tile_X0Y1_E2END_0
    DIRECTION INPUT ;
    USE SIGNAL ;
    PORT
      LAYER MET3 ;
        RECT 0.000 11.050 0.550 11.150 ;
    END
  END Tile_X0Y1_E2END_0
  PIN Tile_X0Y1_E2END_1
    DIRECTION INPUT ;
    USE SIGNAL ;
    PORT
      LAYER MET3 ;
        RECT 0.000 11.650 0.550 11.750 ;
    END
  END Tile_X0Y1_E2END_1
  PIN Tile_X0Y1_E2END_2
    DIRECTION INPUT ;
    USE SIGNAL ;
    PORT
      LAYER MET3 ;
        RECT 0.000 12.250 0.550 12.350 ;
    END
  END Tile_X0Y1_E2END_2
  PIN Tile_X0Y1_E2END_3
    DIRECTION INPUT ;
    USE SIGNAL ;
    PORT
      LAYER MET3 ;
        RECT 0.000 12.850 0.550 12.950 ;
    END
  END Tile_X0Y1_E2END_3
  PIN Tile_X0Y1_E2END_4
    DIRECTION INPUT ;
    USE SIGNAL ;
    PORT
      LAYER MET3 ;
        RECT 0.000 13.450 0.550 13.550 ;
    END
  END Tile_X0Y1_E2END_4
  PIN Tile_X0Y1_E2END_5
    DIRECTION INPUT ;
    USE SIGNAL ;
    PORT
      LAYER MET3 ;
        RECT 0.000 14.050 0.550 14.150 ;
    END
  END Tile_X0Y1_E2END_5
  PIN Tile_X0Y1_E2END_6
    DIRECTION INPUT ;
    USE SIGNAL ;
    PORT
      LAYER MET3 ;
        RECT 0.000 14.650 0.550 14.750 ;
    END
  END Tile_X0Y1_E2END_6
  PIN Tile_X0Y1_E2END_7
    DIRECTION INPUT ;
    USE SIGNAL ;
    PORT
      LAYER MET3 ;
        RECT 0.000 15.250 0.550 15.350 ;
    END
  END Tile_X0Y1_E2END_7
  PIN Tile_X0Y1_EE4END_0
    DIRECTION INPUT ;
    USE SIGNAL ;
    PORT
      LAYER MET3 ;
        RECT 0.000 15.850 0.550 15.950 ;
    END
  END Tile_X0Y1_EE4END_0
  PIN Tile_X0Y1_EE4END_1
    DIRECTION INPUT ;
    USE SIGNAL ;
    PORT
      LAYER MET3 ;
        RECT 0.000 16.450 0.550 16.550 ;
    END
  END Tile_X0Y1_EE4END_1
  PIN Tile_X0Y1_EE4END_2
    DIRECTION INPUT ;
    USE SIGNAL ;
    PORT
      LAYER MET3 ;
        RECT 0.000 17.050 0.550 17.150 ;
    END
  END Tile_X0Y1_EE4END_2
  PIN Tile_X0Y1_EE4END_3
    DIRECTION INPUT ;
    USE SIGNAL ;
    PORT
      LAYER MET3 ;
        RECT 0.000 17.650 0.550 17.750 ;
    END
  END Tile_X0Y1_EE4END_3
  PIN Tile_X0Y1_EE4END_4
    DIRECTION INPUT ;
    USE SIGNAL ;
    PORT
      LAYER MET3 ;
        RECT 0.000 18.250 0.550 18.350 ;
    END
  END Tile_X0Y1_EE4END_4
  PIN Tile_X0Y1_EE4END_5
    DIRECTION INPUT ;
    USE SIGNAL ;
    PORT
      LAYER MET3 ;
        RECT 0.000 18.850 0.550 18.950 ;
    END
  END Tile_X0Y1_EE4END_5
  PIN Tile_X0Y1_EE4END_6
    DIRECTION INPUT ;
    USE SIGNAL ;
    PORT
      LAYER MET3 ;
        RECT 0.000 19.450 0.550 19.550 ;
    END
  END Tile_X0Y1_EE4END_6
  PIN Tile_X0Y1_EE4END_7
    DIRECTION INPUT ;
    USE SIGNAL ;
    PORT
      LAYER MET3 ;
        RECT 0.000 20.050 0.550 20.150 ;
    END
  END Tile_X0Y1_EE4END_7
  PIN Tile_X0Y1_EE4END_8
    DIRECTION INPUT ;
    USE SIGNAL ;
    PORT
      LAYER MET3 ;
        RECT 0.000 20.650 0.550 20.750 ;
    END
  END Tile_X0Y1_EE4END_8
  PIN Tile_X0Y1_EE4END_9
    DIRECTION INPUT ;
    USE SIGNAL ;
    PORT
      LAYER MET3 ;
        RECT 0.000 21.250 0.550 21.350 ;
    END
  END Tile_X0Y1_EE4END_9
  PIN Tile_X0Y1_EE4END_10
    DIRECTION INPUT ;
    USE SIGNAL ;
    PORT
      LAYER MET3 ;
        RECT 0.000 21.850 0.550 21.950 ;
    END
  END Tile_X0Y1_EE4END_10
  PIN Tile_X0Y1_EE4END_11
    DIRECTION INPUT ;
    USE SIGNAL ;
    PORT
      LAYER MET3 ;
        RECT 0.000 22.450 0.550 22.550 ;
    END
  END Tile_X0Y1_EE4END_11
  PIN Tile_X0Y1_EE4END_12
    DIRECTION INPUT ;
    USE SIGNAL ;
    PORT
      LAYER MET3 ;
        RECT 0.000 23.050 0.550 23.150 ;
    END
  END Tile_X0Y1_EE4END_12
  PIN Tile_X0Y1_EE4END_13
    DIRECTION INPUT ;
    USE SIGNAL ;
    PORT
      LAYER MET3 ;
        RECT 0.000 23.650 0.550 23.750 ;
    END
  END Tile_X0Y1_EE4END_13
  PIN Tile_X0Y1_EE4END_14
    DIRECTION INPUT ;
    USE SIGNAL ;
    PORT
      LAYER MET3 ;
        RECT 0.000 24.250 0.550 24.350 ;
    END
  END Tile_X0Y1_EE4END_14
  PIN Tile_X0Y1_EE4END_15
    DIRECTION INPUT ;
    USE SIGNAL ;
    PORT
      LAYER MET3 ;
        RECT 0.000 24.850 0.550 24.950 ;
    END
  END Tile_X0Y1_EE4END_15
  PIN Tile_X0Y1_E6END_0
    DIRECTION INPUT ;
    USE SIGNAL ;
    PORT
      LAYER MET3 ;
        RECT 0.000 25.450 0.550 25.550 ;
    END
  END Tile_X0Y1_E6END_0
  PIN Tile_X0Y1_E6END_1
    DIRECTION INPUT ;
    USE SIGNAL ;
    PORT
      LAYER MET3 ;
        RECT 0.000 26.050 0.550 26.150 ;
    END
  END Tile_X0Y1_E6END_1
  PIN Tile_X0Y1_E6END_2
    DIRECTION INPUT ;
    USE SIGNAL ;
    PORT
      LAYER MET3 ;
        RECT 0.000 26.650 0.550 26.750 ;
    END
  END Tile_X0Y1_E6END_2
  PIN Tile_X0Y1_E6END_3
    DIRECTION INPUT ;
    USE SIGNAL ;
    PORT
      LAYER MET3 ;
        RECT 0.000 27.250 0.550 27.350 ;
    END
  END Tile_X0Y1_E6END_3
  PIN Tile_X0Y1_E6END_4
    DIRECTION INPUT ;
    USE SIGNAL ;
    PORT
      LAYER MET3 ;
        RECT 0.000 27.850 0.550 27.950 ;
    END
  END Tile_X0Y1_E6END_4
  PIN Tile_X0Y1_E6END_5
    DIRECTION INPUT ;
    USE SIGNAL ;
    PORT
      LAYER MET3 ;
        RECT 0.000 28.450 0.550 28.550 ;
    END
  END Tile_X0Y1_E6END_5
  PIN Tile_X0Y1_E6END_6
    DIRECTION INPUT ;
    USE SIGNAL ;
    PORT
      LAYER MET3 ;
        RECT 0.000 29.050 0.550 29.150 ;
    END
  END Tile_X0Y1_E6END_6
  PIN Tile_X0Y1_E6END_7
    DIRECTION INPUT ;
    USE SIGNAL ;
    PORT
      LAYER MET3 ;
        RECT 0.000 29.650 0.550 29.750 ;
    END
  END Tile_X0Y1_E6END_7
  PIN Tile_X0Y1_E6END_8
    DIRECTION INPUT ;
    USE SIGNAL ;
    PORT
      LAYER MET3 ;
        RECT 0.000 30.250 0.550 30.350 ;
    END
  END Tile_X0Y1_E6END_8
  PIN Tile_X0Y1_E6END_9
    DIRECTION INPUT ;
    USE SIGNAL ;
    PORT
      LAYER MET3 ;
        RECT 0.000 30.850 0.550 30.950 ;
    END
  END Tile_X0Y1_E6END_9
  PIN Tile_X0Y1_E6END_10
    DIRECTION INPUT ;
    USE SIGNAL ;
    PORT
      LAYER MET3 ;
        RECT 0.000 31.450 0.550 31.550 ;
    END
  END Tile_X0Y1_E6END_10
  PIN Tile_X0Y1_E6END_11
    DIRECTION INPUT ;
    USE SIGNAL ;
    PORT
      LAYER MET3 ;
        RECT 0.000 32.050 0.550 32.150 ;
    END
  END Tile_X0Y1_E6END_11
  PIN Tile_X0Y1_W1BEG_0
    DIRECTION OUTPUT ;
    USE SIGNAL ;
    PORT
      LAYER MET3 ;
        RECT 0.000 32.650 0.550 32.750 ;
    END
  END Tile_X0Y1_W1BEG_0
  PIN Tile_X0Y1_W1BEG_1
    DIRECTION OUTPUT ;
    USE SIGNAL ;
    PORT
      LAYER MET3 ;
        RECT 0.000 33.250 0.550 33.350 ;
    END
  END Tile_X0Y1_W1BEG_1
  PIN Tile_X0Y1_W1BEG_2
    DIRECTION OUTPUT ;
    USE SIGNAL ;
    PORT
      LAYER MET3 ;
        RECT 0.000 33.850 0.550 33.950 ;
    END
  END Tile_X0Y1_W1BEG_2
  PIN Tile_X0Y1_W1BEG_3
    DIRECTION OUTPUT ;
    USE SIGNAL ;
    PORT
      LAYER MET3 ;
        RECT 0.000 34.450 0.550 34.550 ;
    END
  END Tile_X0Y1_W1BEG_3
  PIN Tile_X0Y1_W2BEG_0
    DIRECTION OUTPUT ;
    USE SIGNAL ;
    PORT
      LAYER MET3 ;
        RECT 0.000 35.050 0.550 35.150 ;
    END
  END Tile_X0Y1_W2BEG_0
  PIN Tile_X0Y1_W2BEG_1
    DIRECTION OUTPUT ;
    USE SIGNAL ;
    PORT
      LAYER MET3 ;
        RECT 0.000 35.650 0.550 35.750 ;
    END
  END Tile_X0Y1_W2BEG_1
  PIN Tile_X0Y1_W2BEG_2
    DIRECTION OUTPUT ;
    USE SIGNAL ;
    PORT
      LAYER MET3 ;
        RECT 0.000 36.250 0.550 36.350 ;
    END
  END Tile_X0Y1_W2BEG_2
  PIN Tile_X0Y1_W2BEG_3
    DIRECTION OUTPUT ;
    USE SIGNAL ;
    PORT
      LAYER MET3 ;
        RECT 0.000 36.850 0.550 36.950 ;
    END
  END Tile_X0Y1_W2BEG_3
  PIN Tile_X0Y1_W2BEG_4
    DIRECTION OUTPUT ;
    USE SIGNAL ;
    PORT
      LAYER MET3 ;
        RECT 0.000 37.450 0.550 37.550 ;
    END
  END Tile_X0Y1_W2BEG_4
  PIN Tile_X0Y1_W2BEG_5
    DIRECTION OUTPUT ;
    USE SIGNAL ;
    PORT
      LAYER MET3 ;
        RECT 0.000 38.050 0.550 38.150 ;
    END
  END Tile_X0Y1_W2BEG_5
  PIN Tile_X0Y1_W2BEG_6
    DIRECTION OUTPUT ;
    USE SIGNAL ;
    PORT
      LAYER MET3 ;
        RECT 0.000 38.650 0.550 38.750 ;
    END
  END Tile_X0Y1_W2BEG_6
  PIN Tile_X0Y1_W2BEG_7
    DIRECTION OUTPUT ;
    USE SIGNAL ;
    PORT
      LAYER MET3 ;
        RECT 0.000 39.250 0.550 39.350 ;
    END
  END Tile_X0Y1_W2BEG_7
  PIN Tile_X0Y1_W2BEGb_0
    DIRECTION OUTPUT ;
    USE SIGNAL ;
    PORT
      LAYER MET3 ;
        RECT 0.000 39.850 0.550 39.950 ;
    END
  END Tile_X0Y1_W2BEGb_0
  PIN Tile_X0Y1_W2BEGb_1
    DIRECTION OUTPUT ;
    USE SIGNAL ;
    PORT
      LAYER MET3 ;
        RECT 0.000 40.450 0.550 40.550 ;
    END
  END Tile_X0Y1_W2BEGb_1
  PIN Tile_X0Y1_W2BEGb_2
    DIRECTION OUTPUT ;
    USE SIGNAL ;
    PORT
      LAYER MET3 ;
        RECT 0.000 41.050 0.550 41.150 ;
    END
  END Tile_X0Y1_W2BEGb_2
  PIN Tile_X0Y1_W2BEGb_3
    DIRECTION OUTPUT ;
    USE SIGNAL ;
    PORT
      LAYER MET3 ;
        RECT 0.000 41.650 0.550 41.750 ;
    END
  END Tile_X0Y1_W2BEGb_3
  PIN Tile_X0Y1_W2BEGb_4
    DIRECTION OUTPUT ;
    USE SIGNAL ;
    PORT
      LAYER MET3 ;
        RECT 0.000 42.250 0.550 42.350 ;
    END
  END Tile_X0Y1_W2BEGb_4
  PIN Tile_X0Y1_W2BEGb_5
    DIRECTION OUTPUT ;
    USE SIGNAL ;
    PORT
      LAYER MET3 ;
        RECT 0.000 42.850 0.550 42.950 ;
    END
  END Tile_X0Y1_W2BEGb_5
  PIN Tile_X0Y1_W2BEGb_6
    DIRECTION OUTPUT ;
    USE SIGNAL ;
    PORT
      LAYER MET3 ;
        RECT 0.000 43.450 0.550 43.550 ;
    END
  END Tile_X0Y1_W2BEGb_6
  PIN Tile_X0Y1_W2BEGb_7
    DIRECTION OUTPUT ;
    USE SIGNAL ;
    PORT
      LAYER MET3 ;
        RECT 0.000 44.050 0.550 44.150 ;
    END
  END Tile_X0Y1_W2BEGb_7
  PIN Tile_X0Y1_WW4BEG_0
    DIRECTION OUTPUT ;
    USE SIGNAL ;
    PORT
      LAYER MET3 ;
        RECT 0.000 44.650 0.550 44.750 ;
    END
  END Tile_X0Y1_WW4BEG_0
  PIN Tile_X0Y1_WW4BEG_1
    DIRECTION OUTPUT ;
    USE SIGNAL ;
    PORT
      LAYER MET3 ;
        RECT 0.000 45.250 0.550 45.350 ;
    END
  END Tile_X0Y1_WW4BEG_1
  PIN Tile_X0Y1_WW4BEG_2
    DIRECTION OUTPUT ;
    USE SIGNAL ;
    PORT
      LAYER MET3 ;
        RECT 0.000 45.850 0.550 45.950 ;
    END
  END Tile_X0Y1_WW4BEG_2
  PIN Tile_X0Y1_WW4BEG_3
    DIRECTION OUTPUT ;
    USE SIGNAL ;
    PORT
      LAYER MET3 ;
        RECT 0.000 46.450 0.550 46.550 ;
    END
  END Tile_X0Y1_WW4BEG_3
  PIN Tile_X0Y1_WW4BEG_4
    DIRECTION OUTPUT ;
    USE SIGNAL ;
    PORT
      LAYER MET3 ;
        RECT 0.000 47.050 0.550 47.150 ;
    END
  END Tile_X0Y1_WW4BEG_4
  PIN Tile_X0Y1_WW4BEG_5
    DIRECTION OUTPUT ;
    USE SIGNAL ;
    PORT
      LAYER MET3 ;
        RECT 0.000 47.650 0.550 47.750 ;
    END
  END Tile_X0Y1_WW4BEG_5
  PIN Tile_X0Y1_WW4BEG_6
    DIRECTION OUTPUT ;
    USE SIGNAL ;
    PORT
      LAYER MET3 ;
        RECT 0.000 48.250 0.550 48.350 ;
    END
  END Tile_X0Y1_WW4BEG_6
  PIN Tile_X0Y1_WW4BEG_7
    DIRECTION OUTPUT ;
    USE SIGNAL ;
    PORT
      LAYER MET3 ;
        RECT 0.000 48.850 0.550 48.950 ;
    END
  END Tile_X0Y1_WW4BEG_7
  PIN Tile_X0Y1_WW4BEG_8
    DIRECTION OUTPUT ;
    USE SIGNAL ;
    PORT
      LAYER MET3 ;
        RECT 0.000 49.450 0.550 49.550 ;
    END
  END Tile_X0Y1_WW4BEG_8
  PIN Tile_X0Y1_WW4BEG_9
    DIRECTION OUTPUT ;
    USE SIGNAL ;
    PORT
      LAYER MET3 ;
        RECT 0.000 50.050 0.550 50.150 ;
    END
  END Tile_X0Y1_WW4BEG_9
  PIN Tile_X0Y1_WW4BEG_10
    DIRECTION OUTPUT ;
    USE SIGNAL ;
    PORT
      LAYER MET3 ;
        RECT 0.000 50.650 0.550 50.750 ;
    END
  END Tile_X0Y1_WW4BEG_10
  PIN Tile_X0Y1_WW4BEG_11
    DIRECTION OUTPUT ;
    USE SIGNAL ;
    PORT
      LAYER MET3 ;
        RECT 0.000 51.250 0.550 51.350 ;
    END
  END Tile_X0Y1_WW4BEG_11
  PIN Tile_X0Y1_WW4BEG_12
    DIRECTION OUTPUT ;
    USE SIGNAL ;
    PORT
      LAYER MET3 ;
        RECT 0.000 51.850 0.550 51.950 ;
    END
  END Tile_X0Y1_WW4BEG_12
  PIN Tile_X0Y1_WW4BEG_13
    DIRECTION OUTPUT ;
    USE SIGNAL ;
    PORT
      LAYER MET3 ;
        RECT 0.000 52.450 0.550 52.550 ;
    END
  END Tile_X0Y1_WW4BEG_13
  PIN Tile_X0Y1_WW4BEG_14
    DIRECTION OUTPUT ;
    USE SIGNAL ;
    PORT
      LAYER MET3 ;
        RECT 0.000 53.050 0.550 53.150 ;
    END
  END Tile_X0Y1_WW4BEG_14
  PIN Tile_X0Y1_WW4BEG_15
    DIRECTION OUTPUT ;
    USE SIGNAL ;
    PORT
      LAYER MET3 ;
        RECT 0.000 53.650 0.550 53.750 ;
    END
  END Tile_X0Y1_WW4BEG_15
  PIN Tile_X0Y1_W6BEG_0
    DIRECTION OUTPUT ;
    USE SIGNAL ;
    PORT
      LAYER MET3 ;
        RECT 0.000 54.250 0.550 54.350 ;
    END
  END Tile_X0Y1_W6BEG_0
  PIN Tile_X0Y1_W6BEG_1
    DIRECTION OUTPUT ;
    USE SIGNAL ;
    PORT
      LAYER MET3 ;
        RECT 0.000 54.850 0.550 54.950 ;
    END
  END Tile_X0Y1_W6BEG_1
  PIN Tile_X0Y1_W6BEG_2
    DIRECTION OUTPUT ;
    USE SIGNAL ;
    PORT
      LAYER MET3 ;
        RECT 0.000 55.450 0.550 55.550 ;
    END
  END Tile_X0Y1_W6BEG_2
  PIN Tile_X0Y1_W6BEG_3
    DIRECTION OUTPUT ;
    USE SIGNAL ;
    PORT
      LAYER MET3 ;
        RECT 0.000 56.050 0.550 56.150 ;
    END
  END Tile_X0Y1_W6BEG_3
  PIN Tile_X0Y1_W6BEG_4
    DIRECTION OUTPUT ;
    USE SIGNAL ;
    PORT
      LAYER MET3 ;
        RECT 0.000 56.650 0.550 56.750 ;
    END
  END Tile_X0Y1_W6BEG_4
  PIN Tile_X0Y1_W6BEG_5
    DIRECTION OUTPUT ;
    USE SIGNAL ;
    PORT
      LAYER MET3 ;
        RECT 0.000 57.250 0.550 57.350 ;
    END
  END Tile_X0Y1_W6BEG_5
  PIN Tile_X0Y1_W6BEG_6
    DIRECTION OUTPUT ;
    USE SIGNAL ;
    PORT
      LAYER MET3 ;
        RECT 0.000 57.850 0.550 57.950 ;
    END
  END Tile_X0Y1_W6BEG_6
  PIN Tile_X0Y1_W6BEG_7
    DIRECTION OUTPUT ;
    USE SIGNAL ;
    PORT
      LAYER MET3 ;
        RECT 0.000 58.450 0.550 58.550 ;
    END
  END Tile_X0Y1_W6BEG_7
  PIN Tile_X0Y1_W6BEG_8
    DIRECTION OUTPUT ;
    USE SIGNAL ;
    PORT
      LAYER MET3 ;
        RECT 0.000 59.050 0.550 59.150 ;
    END
  END Tile_X0Y1_W6BEG_8
  PIN Tile_X0Y1_W6BEG_9
    DIRECTION OUTPUT ;
    USE SIGNAL ;
    PORT
      LAYER MET3 ;
        RECT 0.000 59.650 0.550 59.750 ;
    END
  END Tile_X0Y1_W6BEG_9
  PIN Tile_X0Y1_W6BEG_10
    DIRECTION OUTPUT ;
    USE SIGNAL ;
    PORT
      LAYER MET3 ;
        RECT 0.000 60.250 0.550 60.350 ;
    END
  END Tile_X0Y1_W6BEG_10
  PIN Tile_X0Y1_W6BEG_11
    DIRECTION OUTPUT ;
    USE SIGNAL ;
    PORT
      LAYER MET3 ;
        RECT 0.000 60.850 0.550 60.950 ;
    END
  END Tile_X0Y1_W6BEG_11
  PIN Tile_X0Y0_FrameStrobe_O_0
    DIRECTION OUTPUT ;
    USE SIGNAL ;
    PORT
      LAYER MET4 ;
        RECT 57.250 167.450 57.350 168.000 ;
    END
  END Tile_X0Y0_FrameStrobe_O_0
  PIN Tile_X0Y0_FrameStrobe_O_1
    DIRECTION OUTPUT ;
    USE SIGNAL ;
    PORT
      LAYER MET4 ;
        RECT 57.650 167.450 57.750 168.000 ;
    END
  END Tile_X0Y0_FrameStrobe_O_1
  PIN Tile_X0Y0_FrameStrobe_O_2
    DIRECTION OUTPUT ;
    USE SIGNAL ;
    PORT
      LAYER MET4 ;
        RECT 58.050 167.450 58.150 168.000 ;
    END
  END Tile_X0Y0_FrameStrobe_O_2
  PIN Tile_X0Y0_FrameStrobe_O_3
    DIRECTION OUTPUT ;
    USE SIGNAL ;
    PORT
      LAYER MET4 ;
        RECT 58.450 167.450 58.550 168.000 ;
    END
  END Tile_X0Y0_FrameStrobe_O_3
  PIN Tile_X0Y0_FrameStrobe_O_4
    DIRECTION OUTPUT ;
    USE SIGNAL ;
    PORT
      LAYER MET4 ;
        RECT 58.850 167.450 58.950 168.000 ;
    END
  END Tile_X0Y0_FrameStrobe_O_4
  PIN Tile_X0Y0_FrameStrobe_O_5
    DIRECTION OUTPUT ;
    USE SIGNAL ;
    PORT
      LAYER MET4 ;
        RECT 59.250 167.450 59.350 168.000 ;
    END
  END Tile_X0Y0_FrameStrobe_O_5
  PIN Tile_X0Y0_FrameStrobe_O_6
    DIRECTION OUTPUT ;
    USE SIGNAL ;
    PORT
      LAYER MET4 ;
        RECT 59.650 167.450 59.750 168.000 ;
    END
  END Tile_X0Y0_FrameStrobe_O_6
  PIN Tile_X0Y0_FrameStrobe_O_7
    DIRECTION OUTPUT ;
    USE SIGNAL ;
    PORT
      LAYER MET4 ;
        RECT 60.050 167.450 60.150 168.000 ;
    END
  END Tile_X0Y0_FrameStrobe_O_7
  PIN Tile_X0Y0_FrameStrobe_O_8
    DIRECTION OUTPUT ;
    USE SIGNAL ;
    PORT
      LAYER MET4 ;
        RECT 60.450 167.450 60.550 168.000 ;
    END
  END Tile_X0Y0_FrameStrobe_O_8
  PIN Tile_X0Y0_FrameStrobe_O_9
    DIRECTION OUTPUT ;
    USE SIGNAL ;
    PORT
      LAYER MET4 ;
        RECT 60.850 167.450 60.950 168.000 ;
    END
  END Tile_X0Y0_FrameStrobe_O_9
  PIN Tile_X0Y0_FrameStrobe_O_10
    DIRECTION OUTPUT ;
    USE SIGNAL ;
    PORT
      LAYER MET4 ;
        RECT 62.850 167.450 62.950 168.000 ;
    END
  END Tile_X0Y0_FrameStrobe_O_10
  PIN Tile_X0Y0_FrameStrobe_O_11
    DIRECTION OUTPUT ;
    USE SIGNAL ;
    PORT
      LAYER MET4 ;
        RECT 63.250 167.450 63.350 168.000 ;
    END
  END Tile_X0Y0_FrameStrobe_O_11
  PIN Tile_X0Y0_FrameStrobe_O_12
    DIRECTION OUTPUT ;
    USE SIGNAL ;
    PORT
      LAYER MET4 ;
        RECT 63.650 167.450 63.750 168.000 ;
    END
  END Tile_X0Y0_FrameStrobe_O_12
  PIN Tile_X0Y0_FrameStrobe_O_13
    DIRECTION OUTPUT ;
    USE SIGNAL ;
    PORT
      LAYER MET4 ;
        RECT 64.050 167.450 64.150 168.000 ;
    END
  END Tile_X0Y0_FrameStrobe_O_13
  PIN Tile_X0Y0_FrameStrobe_O_14
    DIRECTION OUTPUT ;
    USE SIGNAL ;
    PORT
      LAYER MET4 ;
        RECT 64.450 167.450 64.550 168.000 ;
    END
  END Tile_X0Y0_FrameStrobe_O_14
  PIN Tile_X0Y0_FrameStrobe_O_15
    DIRECTION OUTPUT ;
    USE SIGNAL ;
    PORT
      LAYER MET4 ;
        RECT 64.850 167.450 64.950 168.000 ;
    END
  END Tile_X0Y0_FrameStrobe_O_15
  PIN Tile_X0Y0_FrameStrobe_O_16
    DIRECTION OUTPUT ;
    USE SIGNAL ;
    PORT
      LAYER MET4 ;
        RECT 65.250 167.450 65.350 168.000 ;
    END
  END Tile_X0Y0_FrameStrobe_O_16
  PIN Tile_X0Y0_FrameStrobe_O_17
    DIRECTION OUTPUT ;
    USE SIGNAL ;
    PORT
      LAYER MET4 ;
        RECT 65.650 167.450 65.750 168.000 ;
    END
  END Tile_X0Y0_FrameStrobe_O_17
  PIN Tile_X0Y0_FrameStrobe_O_18
    DIRECTION OUTPUT ;
    USE SIGNAL ;
    PORT
      LAYER MET4 ;
        RECT 66.050 167.450 66.150 168.000 ;
    END
  END Tile_X0Y0_FrameStrobe_O_18
  PIN Tile_X0Y0_FrameStrobe_O_19
    DIRECTION OUTPUT ;
    USE SIGNAL ;
    PORT
      LAYER MET4 ;
        RECT 66.450 167.450 66.550 168.000 ;
    END
  END Tile_X0Y0_FrameStrobe_O_19
  PIN Tile_X0Y0_FrameData_0
    DIRECTION INPUT ;
    USE SIGNAL ;
    PORT
      LAYER MET3 ;
        RECT 0.000 145.450 0.550 145.550 ;
    END
  END Tile_X0Y0_FrameData_0
  PIN Tile_X0Y0_FrameData_1
    DIRECTION INPUT ;
    USE SIGNAL ;
    PORT
      LAYER MET3 ;
        RECT 0.000 146.050 0.550 146.150 ;
    END
  END Tile_X0Y0_FrameData_1
  PIN Tile_X0Y0_FrameData_2
    DIRECTION INPUT ;
    USE SIGNAL ;
    PORT
      LAYER MET3 ;
        RECT 0.000 146.650 0.550 146.750 ;
    END
  END Tile_X0Y0_FrameData_2
  PIN Tile_X0Y0_FrameData_3
    DIRECTION INPUT ;
    USE SIGNAL ;
    PORT
      LAYER MET3 ;
        RECT 0.000 147.250 0.550 147.350 ;
    END
  END Tile_X0Y0_FrameData_3
  PIN Tile_X0Y0_FrameData_4
    DIRECTION INPUT ;
    USE SIGNAL ;
    PORT
      LAYER MET3 ;
        RECT 0.000 147.850 0.550 147.950 ;
    END
  END Tile_X0Y0_FrameData_4
  PIN Tile_X0Y0_FrameData_5
    DIRECTION INPUT ;
    USE SIGNAL ;
    PORT
      LAYER MET3 ;
        RECT 0.000 148.450 0.550 148.550 ;
    END
  END Tile_X0Y0_FrameData_5
  PIN Tile_X0Y0_FrameData_6
    DIRECTION INPUT ;
    USE SIGNAL ;
    PORT
      LAYER MET3 ;
        RECT 0.000 149.050 0.550 149.150 ;
    END
  END Tile_X0Y0_FrameData_6
  PIN Tile_X0Y0_FrameData_7
    DIRECTION INPUT ;
    USE SIGNAL ;
    PORT
      LAYER MET3 ;
        RECT 0.000 149.650 0.550 149.750 ;
    END
  END Tile_X0Y0_FrameData_7
  PIN Tile_X0Y0_FrameData_8
    DIRECTION INPUT ;
    USE SIGNAL ;
    PORT
      LAYER MET3 ;
        RECT 0.000 150.250 0.550 150.350 ;
    END
  END Tile_X0Y0_FrameData_8
  PIN Tile_X0Y0_FrameData_9
    DIRECTION INPUT ;
    USE SIGNAL ;
    PORT
      LAYER MET3 ;
        RECT 0.000 150.850 0.550 150.950 ;
    END
  END Tile_X0Y0_FrameData_9
  PIN Tile_X0Y0_FrameData_10
    DIRECTION INPUT ;
    USE SIGNAL ;
    PORT
      LAYER MET3 ;
        RECT 0.000 151.450 0.550 151.550 ;
    END
  END Tile_X0Y0_FrameData_10
  PIN Tile_X0Y0_FrameData_11
    DIRECTION INPUT ;
    USE SIGNAL ;
    PORT
      LAYER MET3 ;
        RECT 0.000 152.050 0.550 152.150 ;
    END
  END Tile_X0Y0_FrameData_11
  PIN Tile_X0Y0_FrameData_12
    DIRECTION INPUT ;
    USE SIGNAL ;
    PORT
      LAYER MET3 ;
        RECT 0.000 152.650 0.550 152.750 ;
    END
  END Tile_X0Y0_FrameData_12
  PIN Tile_X0Y0_FrameData_13
    DIRECTION INPUT ;
    USE SIGNAL ;
    PORT
      LAYER MET3 ;
        RECT 0.000 153.250 0.550 153.350 ;
    END
  END Tile_X0Y0_FrameData_13
  PIN Tile_X0Y0_FrameData_14
    DIRECTION INPUT ;
    USE SIGNAL ;
    PORT
      LAYER MET3 ;
        RECT 0.000 153.850 0.550 153.950 ;
    END
  END Tile_X0Y0_FrameData_14
  PIN Tile_X0Y0_FrameData_15
    DIRECTION INPUT ;
    USE SIGNAL ;
    PORT
      LAYER MET3 ;
        RECT 0.000 154.450 0.550 154.550 ;
    END
  END Tile_X0Y0_FrameData_15
  PIN Tile_X0Y0_FrameData_16
    DIRECTION INPUT ;
    USE SIGNAL ;
    PORT
      LAYER MET3 ;
        RECT 0.000 155.050 0.550 155.150 ;
    END
  END Tile_X0Y0_FrameData_16
  PIN Tile_X0Y0_FrameData_17
    DIRECTION INPUT ;
    USE SIGNAL ;
    PORT
      LAYER MET3 ;
        RECT 0.000 155.650 0.550 155.750 ;
    END
  END Tile_X0Y0_FrameData_17
  PIN Tile_X0Y0_FrameData_18
    DIRECTION INPUT ;
    USE SIGNAL ;
    PORT
      LAYER MET3 ;
        RECT 0.000 156.250 0.550 156.350 ;
    END
  END Tile_X0Y0_FrameData_18
  PIN Tile_X0Y0_FrameData_19
    DIRECTION INPUT ;
    USE SIGNAL ;
    PORT
      LAYER MET3 ;
        RECT 0.000 156.850 0.550 156.950 ;
    END
  END Tile_X0Y0_FrameData_19
  PIN Tile_X0Y0_FrameData_20
    DIRECTION INPUT ;
    USE SIGNAL ;
    PORT
      LAYER MET3 ;
        RECT 0.000 157.450 0.550 157.550 ;
    END
  END Tile_X0Y0_FrameData_20
  PIN Tile_X0Y0_FrameData_21
    DIRECTION INPUT ;
    USE SIGNAL ;
    PORT
      LAYER MET3 ;
        RECT 0.000 158.050 0.550 158.150 ;
    END
  END Tile_X0Y0_FrameData_21
  PIN Tile_X0Y0_FrameData_22
    DIRECTION INPUT ;
    USE SIGNAL ;
    PORT
      LAYER MET3 ;
        RECT 0.000 158.650 0.550 158.750 ;
    END
  END Tile_X0Y0_FrameData_22
  PIN Tile_X0Y0_FrameData_23
    DIRECTION INPUT ;
    USE SIGNAL ;
    PORT
      LAYER MET3 ;
        RECT 0.000 159.250 0.550 159.350 ;
    END
  END Tile_X0Y0_FrameData_23
  PIN Tile_X0Y0_FrameData_24
    DIRECTION INPUT ;
    USE SIGNAL ;
    PORT
      LAYER MET3 ;
        RECT 0.000 159.850 0.550 159.950 ;
    END
  END Tile_X0Y0_FrameData_24
  PIN Tile_X0Y0_FrameData_25
    DIRECTION INPUT ;
    USE SIGNAL ;
    PORT
      LAYER MET3 ;
        RECT 0.000 160.450 0.550 160.550 ;
    END
  END Tile_X0Y0_FrameData_25
  PIN Tile_X0Y0_FrameData_26
    DIRECTION INPUT ;
    USE SIGNAL ;
    PORT
      LAYER MET3 ;
        RECT 0.000 161.050 0.550 161.150 ;
    END
  END Tile_X0Y0_FrameData_26
  PIN Tile_X0Y0_FrameData_27
    DIRECTION INPUT ;
    USE SIGNAL ;
    PORT
      LAYER MET3 ;
        RECT 0.000 161.650 0.550 161.750 ;
    END
  END Tile_X0Y0_FrameData_27
  PIN Tile_X0Y0_FrameData_28
    DIRECTION INPUT ;
    USE SIGNAL ;
    PORT
      LAYER MET3 ;
        RECT 0.000 162.250 0.550 162.350 ;
    END
  END Tile_X0Y0_FrameData_28
  PIN Tile_X0Y0_FrameData_29
    DIRECTION INPUT ;
    USE SIGNAL ;
    PORT
      LAYER MET3 ;
        RECT 0.000 162.850 0.550 162.950 ;
    END
  END Tile_X0Y0_FrameData_29
  PIN Tile_X0Y0_FrameData_30
    DIRECTION INPUT ;
    USE SIGNAL ;
    PORT
      LAYER MET3 ;
        RECT 0.000 163.450 0.550 163.550 ;
    END
  END Tile_X0Y0_FrameData_30
  PIN Tile_X0Y0_FrameData_31
    DIRECTION INPUT ;
    USE SIGNAL ;
    PORT
      LAYER MET3 ;
        RECT 0.000 164.050 0.550 164.150 ;
    END
  END Tile_X0Y0_FrameData_31
  PIN Tile_X0Y0_FrameData_O_0
    DIRECTION OUTPUT ;
    USE SIGNAL ;
    PORT
      LAYER MET3 ;
        RECT 70.250 145.450 70.800 145.550 ;
    END
  END Tile_X0Y0_FrameData_O_0
  PIN Tile_X0Y0_FrameData_O_1
    DIRECTION OUTPUT ;
    USE SIGNAL ;
    PORT
      LAYER MET3 ;
        RECT 70.250 146.050 70.800 146.150 ;
    END
  END Tile_X0Y0_FrameData_O_1
  PIN Tile_X0Y0_FrameData_O_2
    DIRECTION OUTPUT ;
    USE SIGNAL ;
    PORT
      LAYER MET3 ;
        RECT 70.250 146.650 70.800 146.750 ;
    END
  END Tile_X0Y0_FrameData_O_2
  PIN Tile_X0Y0_FrameData_O_3
    DIRECTION OUTPUT ;
    USE SIGNAL ;
    PORT
      LAYER MET3 ;
        RECT 70.250 147.250 70.800 147.350 ;
    END
  END Tile_X0Y0_FrameData_O_3
  PIN Tile_X0Y0_FrameData_O_4
    DIRECTION OUTPUT ;
    USE SIGNAL ;
    PORT
      LAYER MET3 ;
        RECT 70.250 147.850 70.800 147.950 ;
    END
  END Tile_X0Y0_FrameData_O_4
  PIN Tile_X0Y0_FrameData_O_5
    DIRECTION OUTPUT ;
    USE SIGNAL ;
    PORT
      LAYER MET3 ;
        RECT 70.250 148.450 70.800 148.550 ;
    END
  END Tile_X0Y0_FrameData_O_5
  PIN Tile_X0Y0_FrameData_O_6
    DIRECTION OUTPUT ;
    USE SIGNAL ;
    PORT
      LAYER MET3 ;
        RECT 70.250 149.050 70.800 149.150 ;
    END
  END Tile_X0Y0_FrameData_O_6
  PIN Tile_X0Y0_FrameData_O_7
    DIRECTION OUTPUT ;
    USE SIGNAL ;
    PORT
      LAYER MET3 ;
        RECT 70.250 149.650 70.800 149.750 ;
    END
  END Tile_X0Y0_FrameData_O_7
  PIN Tile_X0Y0_FrameData_O_8
    DIRECTION OUTPUT ;
    USE SIGNAL ;
    PORT
      LAYER MET3 ;
        RECT 70.250 150.250 70.800 150.350 ;
    END
  END Tile_X0Y0_FrameData_O_8
  PIN Tile_X0Y0_FrameData_O_9
    DIRECTION OUTPUT ;
    USE SIGNAL ;
    PORT
      LAYER MET3 ;
        RECT 70.250 150.850 70.800 150.950 ;
    END
  END Tile_X0Y0_FrameData_O_9
  PIN Tile_X0Y0_FrameData_O_10
    DIRECTION OUTPUT ;
    USE SIGNAL ;
    PORT
      LAYER MET3 ;
        RECT 70.250 151.450 70.800 151.550 ;
    END
  END Tile_X0Y0_FrameData_O_10
  PIN Tile_X0Y0_FrameData_O_11
    DIRECTION OUTPUT ;
    USE SIGNAL ;
    PORT
      LAYER MET3 ;
        RECT 70.250 152.050 70.800 152.150 ;
    END
  END Tile_X0Y0_FrameData_O_11
  PIN Tile_X0Y0_FrameData_O_12
    DIRECTION OUTPUT ;
    USE SIGNAL ;
    PORT
      LAYER MET3 ;
        RECT 70.250 152.650 70.800 152.750 ;
    END
  END Tile_X0Y0_FrameData_O_12
  PIN Tile_X0Y0_FrameData_O_13
    DIRECTION OUTPUT ;
    USE SIGNAL ;
    PORT
      LAYER MET3 ;
        RECT 70.250 153.250 70.800 153.350 ;
    END
  END Tile_X0Y0_FrameData_O_13
  PIN Tile_X0Y0_FrameData_O_14
    DIRECTION OUTPUT ;
    USE SIGNAL ;
    PORT
      LAYER MET3 ;
        RECT 70.250 153.850 70.800 153.950 ;
    END
  END Tile_X0Y0_FrameData_O_14
  PIN Tile_X0Y0_FrameData_O_15
    DIRECTION OUTPUT ;
    USE SIGNAL ;
    PORT
      LAYER MET3 ;
        RECT 70.250 154.450 70.800 154.550 ;
    END
  END Tile_X0Y0_FrameData_O_15
  PIN Tile_X0Y0_FrameData_O_16
    DIRECTION OUTPUT ;
    USE SIGNAL ;
    PORT
      LAYER MET3 ;
        RECT 70.250 155.050 70.800 155.150 ;
    END
  END Tile_X0Y0_FrameData_O_16
  PIN Tile_X0Y0_FrameData_O_17
    DIRECTION OUTPUT ;
    USE SIGNAL ;
    PORT
      LAYER MET3 ;
        RECT 70.250 155.650 70.800 155.750 ;
    END
  END Tile_X0Y0_FrameData_O_17
  PIN Tile_X0Y0_FrameData_O_18
    DIRECTION OUTPUT ;
    USE SIGNAL ;
    PORT
      LAYER MET3 ;
        RECT 70.250 156.250 70.800 156.350 ;
    END
  END Tile_X0Y0_FrameData_O_18
  PIN Tile_X0Y0_FrameData_O_19
    DIRECTION OUTPUT ;
    USE SIGNAL ;
    PORT
      LAYER MET3 ;
        RECT 70.250 156.850 70.800 156.950 ;
    END
  END Tile_X0Y0_FrameData_O_19
  PIN Tile_X0Y0_FrameData_O_20
    DIRECTION OUTPUT ;
    USE SIGNAL ;
    PORT
      LAYER MET3 ;
        RECT 70.250 157.450 70.800 157.550 ;
    END
  END Tile_X0Y0_FrameData_O_20
  PIN Tile_X0Y0_FrameData_O_21
    DIRECTION OUTPUT ;
    USE SIGNAL ;
    PORT
      LAYER MET3 ;
        RECT 70.250 158.050 70.800 158.150 ;
    END
  END Tile_X0Y0_FrameData_O_21
  PIN Tile_X0Y0_FrameData_O_22
    DIRECTION OUTPUT ;
    USE SIGNAL ;
    PORT
      LAYER MET3 ;
        RECT 70.250 158.650 70.800 158.750 ;
    END
  END Tile_X0Y0_FrameData_O_22
  PIN Tile_X0Y0_FrameData_O_23
    DIRECTION OUTPUT ;
    USE SIGNAL ;
    PORT
      LAYER MET3 ;
        RECT 70.250 159.250 70.800 159.350 ;
    END
  END Tile_X0Y0_FrameData_O_23
  PIN Tile_X0Y0_FrameData_O_24
    DIRECTION OUTPUT ;
    USE SIGNAL ;
    PORT
      LAYER MET3 ;
        RECT 70.250 159.850 70.800 159.950 ;
    END
  END Tile_X0Y0_FrameData_O_24
  PIN Tile_X0Y0_FrameData_O_25
    DIRECTION OUTPUT ;
    USE SIGNAL ;
    PORT
      LAYER MET3 ;
        RECT 70.250 160.450 70.800 160.550 ;
    END
  END Tile_X0Y0_FrameData_O_25
  PIN Tile_X0Y0_FrameData_O_26
    DIRECTION OUTPUT ;
    USE SIGNAL ;
    PORT
      LAYER MET3 ;
        RECT 70.250 161.050 70.800 161.150 ;
    END
  END Tile_X0Y0_FrameData_O_26
  PIN Tile_X0Y0_FrameData_O_27
    DIRECTION OUTPUT ;
    USE SIGNAL ;
    PORT
      LAYER MET3 ;
        RECT 70.250 161.650 70.800 161.750 ;
    END
  END Tile_X0Y0_FrameData_O_27
  PIN Tile_X0Y0_FrameData_O_28
    DIRECTION OUTPUT ;
    USE SIGNAL ;
    PORT
      LAYER MET3 ;
        RECT 70.250 162.250 70.800 162.350 ;
    END
  END Tile_X0Y0_FrameData_O_28
  PIN Tile_X0Y0_FrameData_O_29
    DIRECTION OUTPUT ;
    USE SIGNAL ;
    PORT
      LAYER MET3 ;
        RECT 70.250 162.850 70.800 162.950 ;
    END
  END Tile_X0Y0_FrameData_O_29
  PIN Tile_X0Y0_FrameData_O_30
    DIRECTION OUTPUT ;
    USE SIGNAL ;
    PORT
      LAYER MET3 ;
        RECT 70.250 163.450 70.800 163.550 ;
    END
  END Tile_X0Y0_FrameData_O_30
  PIN Tile_X0Y0_FrameData_O_31
    DIRECTION OUTPUT ;
    USE SIGNAL ;
    PORT
      LAYER MET3 ;
        RECT 70.250 164.050 70.800 164.150 ;
    END
  END Tile_X0Y0_FrameData_O_31
  PIN Tile_X0Y1_FrameData_0
    DIRECTION INPUT ;
    USE SIGNAL ;
    PORT
      LAYER MET3 ;
        RECT 0.000 61.450 0.550 61.550 ;
    END
  END Tile_X0Y1_FrameData_0
  PIN Tile_X0Y1_FrameData_1
    DIRECTION INPUT ;
    USE SIGNAL ;
    PORT
      LAYER MET3 ;
        RECT 0.000 62.050 0.550 62.150 ;
    END
  END Tile_X0Y1_FrameData_1
  PIN Tile_X0Y1_FrameData_2
    DIRECTION INPUT ;
    USE SIGNAL ;
    PORT
      LAYER MET3 ;
        RECT 0.000 62.650 0.550 62.750 ;
    END
  END Tile_X0Y1_FrameData_2
  PIN Tile_X0Y1_FrameData_3
    DIRECTION INPUT ;
    USE SIGNAL ;
    PORT
      LAYER MET3 ;
        RECT 0.000 63.250 0.550 63.350 ;
    END
  END Tile_X0Y1_FrameData_3
  PIN Tile_X0Y1_FrameData_4
    DIRECTION INPUT ;
    USE SIGNAL ;
    PORT
      LAYER MET3 ;
        RECT 0.000 63.850 0.550 63.950 ;
    END
  END Tile_X0Y1_FrameData_4
  PIN Tile_X0Y1_FrameData_5
    DIRECTION INPUT ;
    USE SIGNAL ;
    PORT
      LAYER MET3 ;
        RECT 0.000 64.450 0.550 64.550 ;
    END
  END Tile_X0Y1_FrameData_5
  PIN Tile_X0Y1_FrameData_6
    DIRECTION INPUT ;
    USE SIGNAL ;
    PORT
      LAYER MET3 ;
        RECT 0.000 65.050 0.550 65.150 ;
    END
  END Tile_X0Y1_FrameData_6
  PIN Tile_X0Y1_FrameData_7
    DIRECTION INPUT ;
    USE SIGNAL ;
    PORT
      LAYER MET3 ;
        RECT 0.000 65.650 0.550 65.750 ;
    END
  END Tile_X0Y1_FrameData_7
  PIN Tile_X0Y1_FrameData_8
    DIRECTION INPUT ;
    USE SIGNAL ;
    PORT
      LAYER MET3 ;
        RECT 0.000 66.250 0.550 66.350 ;
    END
  END Tile_X0Y1_FrameData_8
  PIN Tile_X0Y1_FrameData_9
    DIRECTION INPUT ;
    USE SIGNAL ;
    PORT
      LAYER MET3 ;
        RECT 0.000 66.850 0.550 66.950 ;
    END
  END Tile_X0Y1_FrameData_9
  PIN Tile_X0Y1_FrameData_10
    DIRECTION INPUT ;
    USE SIGNAL ;
    PORT
      LAYER MET3 ;
        RECT 0.000 67.450 0.550 67.550 ;
    END
  END Tile_X0Y1_FrameData_10
  PIN Tile_X0Y1_FrameData_11
    DIRECTION INPUT ;
    USE SIGNAL ;
    PORT
      LAYER MET3 ;
        RECT 0.000 68.050 0.550 68.150 ;
    END
  END Tile_X0Y1_FrameData_11
  PIN Tile_X0Y1_FrameData_12
    DIRECTION INPUT ;
    USE SIGNAL ;
    PORT
      LAYER MET3 ;
        RECT 0.000 68.650 0.550 68.750 ;
    END
  END Tile_X0Y1_FrameData_12
  PIN Tile_X0Y1_FrameData_13
    DIRECTION INPUT ;
    USE SIGNAL ;
    PORT
      LAYER MET3 ;
        RECT 0.000 69.250 0.550 69.350 ;
    END
  END Tile_X0Y1_FrameData_13
  PIN Tile_X0Y1_FrameData_14
    DIRECTION INPUT ;
    USE SIGNAL ;
    PORT
      LAYER MET3 ;
        RECT 0.000 69.850 0.550 69.950 ;
    END
  END Tile_X0Y1_FrameData_14
  PIN Tile_X0Y1_FrameData_15
    DIRECTION INPUT ;
    USE SIGNAL ;
    PORT
      LAYER MET3 ;
        RECT 0.000 70.450 0.550 70.550 ;
    END
  END Tile_X0Y1_FrameData_15
  PIN Tile_X0Y1_FrameData_16
    DIRECTION INPUT ;
    USE SIGNAL ;
    PORT
      LAYER MET3 ;
        RECT 0.000 71.050 0.550 71.150 ;
    END
  END Tile_X0Y1_FrameData_16
  PIN Tile_X0Y1_FrameData_17
    DIRECTION INPUT ;
    USE SIGNAL ;
    PORT
      LAYER MET3 ;
        RECT 0.000 71.650 0.550 71.750 ;
    END
  END Tile_X0Y1_FrameData_17
  PIN Tile_X0Y1_FrameData_18
    DIRECTION INPUT ;
    USE SIGNAL ;
    PORT
      LAYER MET3 ;
        RECT 0.000 72.250 0.550 72.350 ;
    END
  END Tile_X0Y1_FrameData_18
  PIN Tile_X0Y1_FrameData_19
    DIRECTION INPUT ;
    USE SIGNAL ;
    PORT
      LAYER MET3 ;
        RECT 0.000 72.850 0.550 72.950 ;
    END
  END Tile_X0Y1_FrameData_19
  PIN Tile_X0Y1_FrameData_20
    DIRECTION INPUT ;
    USE SIGNAL ;
    PORT
      LAYER MET3 ;
        RECT 0.000 73.450 0.550 73.550 ;
    END
  END Tile_X0Y1_FrameData_20
  PIN Tile_X0Y1_FrameData_21
    DIRECTION INPUT ;
    USE SIGNAL ;
    PORT
      LAYER MET3 ;
        RECT 0.000 74.050 0.550 74.150 ;
    END
  END Tile_X0Y1_FrameData_21
  PIN Tile_X0Y1_FrameData_22
    DIRECTION INPUT ;
    USE SIGNAL ;
    PORT
      LAYER MET3 ;
        RECT 0.000 74.650 0.550 74.750 ;
    END
  END Tile_X0Y1_FrameData_22
  PIN Tile_X0Y1_FrameData_23
    DIRECTION INPUT ;
    USE SIGNAL ;
    PORT
      LAYER MET3 ;
        RECT 0.000 75.250 0.550 75.350 ;
    END
  END Tile_X0Y1_FrameData_23
  PIN Tile_X0Y1_FrameData_24
    DIRECTION INPUT ;
    USE SIGNAL ;
    PORT
      LAYER MET3 ;
        RECT 0.000 75.850 0.550 75.950 ;
    END
  END Tile_X0Y1_FrameData_24
  PIN Tile_X0Y1_FrameData_25
    DIRECTION INPUT ;
    USE SIGNAL ;
    PORT
      LAYER MET3 ;
        RECT 0.000 76.450 0.550 76.550 ;
    END
  END Tile_X0Y1_FrameData_25
  PIN Tile_X0Y1_FrameData_26
    DIRECTION INPUT ;
    USE SIGNAL ;
    PORT
      LAYER MET3 ;
        RECT 0.000 77.050 0.550 77.150 ;
    END
  END Tile_X0Y1_FrameData_26
  PIN Tile_X0Y1_FrameData_27
    DIRECTION INPUT ;
    USE SIGNAL ;
    PORT
      LAYER MET3 ;
        RECT 0.000 77.650 0.550 77.750 ;
    END
  END Tile_X0Y1_FrameData_27
  PIN Tile_X0Y1_FrameData_28
    DIRECTION INPUT ;
    USE SIGNAL ;
    PORT
      LAYER MET3 ;
        RECT 0.000 78.250 0.550 78.350 ;
    END
  END Tile_X0Y1_FrameData_28
  PIN Tile_X0Y1_FrameData_29
    DIRECTION INPUT ;
    USE SIGNAL ;
    PORT
      LAYER MET3 ;
        RECT 0.000 78.850 0.550 78.950 ;
    END
  END Tile_X0Y1_FrameData_29
  PIN Tile_X0Y1_FrameData_30
    DIRECTION INPUT ;
    USE SIGNAL ;
    PORT
      LAYER MET3 ;
        RECT 0.000 79.450 0.550 79.550 ;
    END
  END Tile_X0Y1_FrameData_30
  PIN Tile_X0Y1_FrameData_31
    DIRECTION INPUT ;
    USE SIGNAL ;
    PORT
      LAYER MET3 ;
        RECT 0.000 80.050 0.550 80.150 ;
    END
  END Tile_X0Y1_FrameData_31
  PIN Tile_X0Y1_FrameStrobe_0
    DIRECTION INPUT ;
    USE SIGNAL ;
    PORT
      LAYER MET4 ;
        RECT 57.250 0.000 57.350 0.550 ;
    END
  END Tile_X0Y1_FrameStrobe_0
  PIN Tile_X0Y1_FrameStrobe_1
    DIRECTION INPUT ;
    USE SIGNAL ;
    PORT
      LAYER MET4 ;
        RECT 57.650 0.000 57.750 0.550 ;
    END
  END Tile_X0Y1_FrameStrobe_1
  PIN Tile_X0Y1_FrameStrobe_2
    DIRECTION INPUT ;
    USE SIGNAL ;
    PORT
      LAYER MET4 ;
        RECT 58.050 0.000 58.150 0.550 ;
    END
  END Tile_X0Y1_FrameStrobe_2
  PIN Tile_X0Y1_FrameStrobe_3
    DIRECTION INPUT ;
    USE SIGNAL ;
    PORT
      LAYER MET4 ;
        RECT 58.450 0.000 58.550 0.550 ;
    END
  END Tile_X0Y1_FrameStrobe_3
  PIN Tile_X0Y1_FrameStrobe_4
    DIRECTION INPUT ;
    USE SIGNAL ;
    PORT
      LAYER MET4 ;
        RECT 58.850 0.000 58.950 0.550 ;
    END
  END Tile_X0Y1_FrameStrobe_4
  PIN Tile_X0Y1_FrameStrobe_5
    DIRECTION INPUT ;
    USE SIGNAL ;
    PORT
      LAYER MET4 ;
        RECT 59.250 0.000 59.350 0.550 ;
    END
  END Tile_X0Y1_FrameStrobe_5
  PIN Tile_X0Y1_FrameStrobe_6
    DIRECTION INPUT ;
    USE SIGNAL ;
    PORT
      LAYER MET4 ;
        RECT 59.650 0.000 59.750 0.550 ;
    END
  END Tile_X0Y1_FrameStrobe_6
  PIN Tile_X0Y1_FrameStrobe_7
    DIRECTION INPUT ;
    USE SIGNAL ;
    PORT
      LAYER MET4 ;
        RECT 60.050 0.000 60.150 0.550 ;
    END
  END Tile_X0Y1_FrameStrobe_7
  PIN Tile_X0Y1_FrameStrobe_8
    DIRECTION INPUT ;
    USE SIGNAL ;
    PORT
      LAYER MET4 ;
        RECT 60.450 0.000 60.550 0.550 ;
    END
  END Tile_X0Y1_FrameStrobe_8
  PIN Tile_X0Y1_FrameStrobe_9
    DIRECTION INPUT ;
    USE SIGNAL ;
    PORT
      LAYER MET4 ;
        RECT 60.850 0.000 60.950 0.550 ;
    END
  END Tile_X0Y1_FrameStrobe_9
  PIN Tile_X0Y1_FrameStrobe_10
    DIRECTION INPUT ;
    USE SIGNAL ;
    PORT
      LAYER MET4 ;
        RECT 62.850 0.000 62.950 0.550 ;
    END
  END Tile_X0Y1_FrameStrobe_10
  PIN Tile_X0Y1_FrameStrobe_11
    DIRECTION INPUT ;
    USE SIGNAL ;
    PORT
      LAYER MET4 ;
        RECT 63.250 0.000 63.350 0.550 ;
    END
  END Tile_X0Y1_FrameStrobe_11
  PIN Tile_X0Y1_FrameStrobe_12
    DIRECTION INPUT ;
    USE SIGNAL ;
    PORT
      LAYER MET4 ;
        RECT 63.650 0.000 63.750 0.550 ;
    END
  END Tile_X0Y1_FrameStrobe_12
  PIN Tile_X0Y1_FrameStrobe_13
    DIRECTION INPUT ;
    USE SIGNAL ;
    PORT
      LAYER MET4 ;
        RECT 64.050 0.000 64.150 0.550 ;
    END
  END Tile_X0Y1_FrameStrobe_13
  PIN Tile_X0Y1_FrameStrobe_14
    DIRECTION INPUT ;
    USE SIGNAL ;
    PORT
      LAYER MET4 ;
        RECT 64.450 0.000 64.550 0.550 ;
    END
  END Tile_X0Y1_FrameStrobe_14
  PIN Tile_X0Y1_FrameStrobe_15
    DIRECTION INPUT ;
    USE SIGNAL ;
    PORT
      LAYER MET4 ;
        RECT 64.850 0.000 64.950 0.550 ;
    END
  END Tile_X0Y1_FrameStrobe_15
  PIN Tile_X0Y1_FrameStrobe_16
    DIRECTION INPUT ;
    USE SIGNAL ;
    PORT
      LAYER MET4 ;
        RECT 65.250 0.000 65.350 0.550 ;
    END
  END Tile_X0Y1_FrameStrobe_16
  PIN Tile_X0Y1_FrameStrobe_17
    DIRECTION INPUT ;
    USE SIGNAL ;
    PORT
      LAYER MET4 ;
        RECT 65.650 0.000 65.750 0.550 ;
    END
  END Tile_X0Y1_FrameStrobe_17
  PIN Tile_X0Y1_FrameStrobe_18
    DIRECTION INPUT ;
    USE SIGNAL ;
    PORT
      LAYER MET4 ;
        RECT 66.050 0.000 66.150 0.550 ;
    END
  END Tile_X0Y1_FrameStrobe_18
  PIN Tile_X0Y1_FrameStrobe_19
    DIRECTION INPUT ;
    USE SIGNAL ;
    PORT
      LAYER MET4 ;
        RECT 66.450 0.000 66.550 0.550 ;
    END
  END Tile_X0Y1_FrameStrobe_19
  PIN Tile_X0Y1_FrameData_O_0
    DIRECTION OUTPUT ;
    USE SIGNAL ;
    PORT
      LAYER MET3 ;
        RECT 70.250 61.450 70.800 61.550 ;
    END
  END Tile_X0Y1_FrameData_O_0
  PIN Tile_X0Y1_FrameData_O_1
    DIRECTION OUTPUT ;
    USE SIGNAL ;
    PORT
      LAYER MET3 ;
        RECT 70.250 62.050 70.800 62.150 ;
    END
  END Tile_X0Y1_FrameData_O_1
  PIN Tile_X0Y1_FrameData_O_2
    DIRECTION OUTPUT ;
    USE SIGNAL ;
    PORT
      LAYER MET3 ;
        RECT 70.250 62.650 70.800 62.750 ;
    END
  END Tile_X0Y1_FrameData_O_2
  PIN Tile_X0Y1_FrameData_O_3
    DIRECTION OUTPUT ;
    USE SIGNAL ;
    PORT
      LAYER MET3 ;
        RECT 70.250 63.250 70.800 63.350 ;
    END
  END Tile_X0Y1_FrameData_O_3
  PIN Tile_X0Y1_FrameData_O_4
    DIRECTION OUTPUT ;
    USE SIGNAL ;
    PORT
      LAYER MET3 ;
        RECT 70.250 63.850 70.800 63.950 ;
    END
  END Tile_X0Y1_FrameData_O_4
  PIN Tile_X0Y1_FrameData_O_5
    DIRECTION OUTPUT ;
    USE SIGNAL ;
    PORT
      LAYER MET3 ;
        RECT 70.250 64.450 70.800 64.550 ;
    END
  END Tile_X0Y1_FrameData_O_5
  PIN Tile_X0Y1_FrameData_O_6
    DIRECTION OUTPUT ;
    USE SIGNAL ;
    PORT
      LAYER MET3 ;
        RECT 70.250 65.050 70.800 65.150 ;
    END
  END Tile_X0Y1_FrameData_O_6
  PIN Tile_X0Y1_FrameData_O_7
    DIRECTION OUTPUT ;
    USE SIGNAL ;
    PORT
      LAYER MET3 ;
        RECT 70.250 65.650 70.800 65.750 ;
    END
  END Tile_X0Y1_FrameData_O_7
  PIN Tile_X0Y1_FrameData_O_8
    DIRECTION OUTPUT ;
    USE SIGNAL ;
    PORT
      LAYER MET3 ;
        RECT 70.250 66.250 70.800 66.350 ;
    END
  END Tile_X0Y1_FrameData_O_8
  PIN Tile_X0Y1_FrameData_O_9
    DIRECTION OUTPUT ;
    USE SIGNAL ;
    PORT
      LAYER MET3 ;
        RECT 70.250 66.850 70.800 66.950 ;
    END
  END Tile_X0Y1_FrameData_O_9
  PIN Tile_X0Y1_FrameData_O_10
    DIRECTION OUTPUT ;
    USE SIGNAL ;
    PORT
      LAYER MET3 ;
        RECT 70.250 67.450 70.800 67.550 ;
    END
  END Tile_X0Y1_FrameData_O_10
  PIN Tile_X0Y1_FrameData_O_11
    DIRECTION OUTPUT ;
    USE SIGNAL ;
    PORT
      LAYER MET3 ;
        RECT 70.250 68.050 70.800 68.150 ;
    END
  END Tile_X0Y1_FrameData_O_11
  PIN Tile_X0Y1_FrameData_O_12
    DIRECTION OUTPUT ;
    USE SIGNAL ;
    PORT
      LAYER MET3 ;
        RECT 70.250 68.650 70.800 68.750 ;
    END
  END Tile_X0Y1_FrameData_O_12
  PIN Tile_X0Y1_FrameData_O_13
    DIRECTION OUTPUT ;
    USE SIGNAL ;
    PORT
      LAYER MET3 ;
        RECT 70.250 69.250 70.800 69.350 ;
    END
  END Tile_X0Y1_FrameData_O_13
  PIN Tile_X0Y1_FrameData_O_14
    DIRECTION OUTPUT ;
    USE SIGNAL ;
    PORT
      LAYER MET3 ;
        RECT 70.250 69.850 70.800 69.950 ;
    END
  END Tile_X0Y1_FrameData_O_14
  PIN Tile_X0Y1_FrameData_O_15
    DIRECTION OUTPUT ;
    USE SIGNAL ;
    PORT
      LAYER MET3 ;
        RECT 70.250 70.450 70.800 70.550 ;
    END
  END Tile_X0Y1_FrameData_O_15
  PIN Tile_X0Y1_FrameData_O_16
    DIRECTION OUTPUT ;
    USE SIGNAL ;
    PORT
      LAYER MET3 ;
        RECT 70.250 71.050 70.800 71.150 ;
    END
  END Tile_X0Y1_FrameData_O_16
  PIN Tile_X0Y1_FrameData_O_17
    DIRECTION OUTPUT ;
    USE SIGNAL ;
    PORT
      LAYER MET3 ;
        RECT 70.250 71.650 70.800 71.750 ;
    END
  END Tile_X0Y1_FrameData_O_17
  PIN Tile_X0Y1_FrameData_O_18
    DIRECTION OUTPUT ;
    USE SIGNAL ;
    PORT
      LAYER MET3 ;
        RECT 70.250 72.250 70.800 72.350 ;
    END
  END Tile_X0Y1_FrameData_O_18
  PIN Tile_X0Y1_FrameData_O_19
    DIRECTION OUTPUT ;
    USE SIGNAL ;
    PORT
      LAYER MET3 ;
        RECT 70.250 72.850 70.800 72.950 ;
    END
  END Tile_X0Y1_FrameData_O_19
  PIN Tile_X0Y1_FrameData_O_20
    DIRECTION OUTPUT ;
    USE SIGNAL ;
    PORT
      LAYER MET3 ;
        RECT 70.250 73.450 70.800 73.550 ;
    END
  END Tile_X0Y1_FrameData_O_20
  PIN Tile_X0Y1_FrameData_O_21
    DIRECTION OUTPUT ;
    USE SIGNAL ;
    PORT
      LAYER MET3 ;
        RECT 70.250 74.050 70.800 74.150 ;
    END
  END Tile_X0Y1_FrameData_O_21
  PIN Tile_X0Y1_FrameData_O_22
    DIRECTION OUTPUT ;
    USE SIGNAL ;
    PORT
      LAYER MET3 ;
        RECT 70.250 74.650 70.800 74.750 ;
    END
  END Tile_X0Y1_FrameData_O_22
  PIN Tile_X0Y1_FrameData_O_23
    DIRECTION OUTPUT ;
    USE SIGNAL ;
    PORT
      LAYER MET3 ;
        RECT 70.250 75.250 70.800 75.350 ;
    END
  END Tile_X0Y1_FrameData_O_23
  PIN Tile_X0Y1_FrameData_O_24
    DIRECTION OUTPUT ;
    USE SIGNAL ;
    PORT
      LAYER MET3 ;
        RECT 70.250 75.850 70.800 75.950 ;
    END
  END Tile_X0Y1_FrameData_O_24
  PIN Tile_X0Y1_FrameData_O_25
    DIRECTION OUTPUT ;
    USE SIGNAL ;
    PORT
      LAYER MET3 ;
        RECT 70.250 76.450 70.800 76.550 ;
    END
  END Tile_X0Y1_FrameData_O_25
  PIN Tile_X0Y1_FrameData_O_26
    DIRECTION OUTPUT ;
    USE SIGNAL ;
    PORT
      LAYER MET3 ;
        RECT 70.250 77.050 70.800 77.150 ;
    END
  END Tile_X0Y1_FrameData_O_26
  PIN Tile_X0Y1_FrameData_O_27
    DIRECTION OUTPUT ;
    USE SIGNAL ;
    PORT
      LAYER MET3 ;
        RECT 70.250 77.650 70.800 77.750 ;
    END
  END Tile_X0Y1_FrameData_O_27
  PIN Tile_X0Y1_FrameData_O_28
    DIRECTION OUTPUT ;
    USE SIGNAL ;
    PORT
      LAYER MET3 ;
        RECT 70.250 78.250 70.800 78.350 ;
    END
  END Tile_X0Y1_FrameData_O_28
  PIN Tile_X0Y1_FrameData_O_29
    DIRECTION OUTPUT ;
    USE SIGNAL ;
    PORT
      LAYER MET3 ;
        RECT 70.250 78.850 70.800 78.950 ;
    END
  END Tile_X0Y1_FrameData_O_29
  PIN Tile_X0Y1_FrameData_O_30
    DIRECTION OUTPUT ;
    USE SIGNAL ;
    PORT
      LAYER MET3 ;
        RECT 70.250 79.450 70.800 79.550 ;
    END
  END Tile_X0Y1_FrameData_O_30
  PIN Tile_X0Y1_FrameData_O_31
    DIRECTION OUTPUT ;
    USE SIGNAL ;
    PORT
      LAYER MET3 ;
        RECT 70.250 80.050 70.800 80.150 ;
    END
  END Tile_X0Y1_FrameData_O_31
  PIN vdd_stripe_generate
    DIRECTION INOUT ;
    USE POWER ;
    PORT
      LAYER MET5 ;
        RECT 0.000 2.500 70.800 3.500 ;
      LAYER MET5 ;
        RECT 0.000 19.300 70.800 20.300 ;
      LAYER MET5 ;
        RECT 0.000 36.100 70.800 37.100 ;
      LAYER MET5 ;
        RECT 0.000 52.900 70.800 53.900 ;
      LAYER MET5 ;
        RECT 0.000 69.700 70.800 70.700 ;
      LAYER MET5 ;
        RECT 0.000 86.500 70.800 87.500 ;
      LAYER MET5 ;
        RECT 0.000 103.300 70.800 104.300 ;
      LAYER MET5 ;
        RECT 0.000 120.100 70.800 121.100 ;
      LAYER MET5 ;
        RECT 0.000 136.900 70.800 137.900 ;
      LAYER MET5 ;
        RECT 0.000 153.700 70.800 154.700 ;
    END
  END vdd_stripe_generate
  PIN vss_stripe_generate
    DIRECTION INOUT ;
    USE GROUND ;
    PORT
      LAYER MET5 ;
        RECT 0.000 10.900 70.800 11.900 ;
      LAYER MET5 ;
        RECT 0.000 27.700 70.800 28.700 ;
      LAYER MET5 ;
        RECT 0.000 44.500 70.800 45.500 ;
      LAYER MET5 ;
        RECT 0.000 61.300 70.800 62.300 ;
      LAYER MET5 ;
        RECT 0.000 78.100 70.800 79.100 ;
      LAYER MET5 ;
        RECT 0.000 94.900 70.800 95.900 ;
      LAYER MET5 ;
        RECT 0.000 111.700 70.800 112.700 ;
      LAYER MET5 ;
        RECT 0.000 128.500 70.800 129.500 ;
      LAYER MET5 ;
        RECT 0.000 145.300 70.800 146.300 ;
      LAYER MET5 ;
        RECT 0.000 162.100 70.800 163.100 ;
    END
  END vss_stripe_generate
  OBS
    LAYER MET1 ;
    RECT 0.000 0.000 70.800 168.000 ;
    LAYER MET2 ;
    RECT 0.000 0.000 70.800 168.000 ;
    LAYER MET3 ;
    RECT 0.000 0.000 70.800 3.750 ;
    LAYER MET3 ;
    RECT 0.650 3.750 70.150 4.050 ;
    LAYER MET3 ;
    RECT 0.000 4.050 70.800 4.350 ;
    LAYER MET3 ;
    RECT 0.650 4.350 70.150 4.650 ;
    LAYER MET3 ;
    RECT 0.000 4.650 70.800 4.950 ;
    LAYER MET3 ;
    RECT 0.650 4.950 70.150 5.250 ;
    LAYER MET3 ;
    RECT 0.000 5.250 70.800 5.550 ;
    LAYER MET3 ;
    RECT 0.650 5.550 70.150 5.850 ;
    LAYER MET3 ;
    RECT 0.000 5.850 70.800 6.150 ;
    LAYER MET3 ;
    RECT 0.650 6.150 70.150 6.450 ;
    LAYER MET3 ;
    RECT 0.000 6.450 70.800 6.750 ;
    LAYER MET3 ;
    RECT 0.650 6.750 70.150 7.050 ;
    LAYER MET3 ;
    RECT 0.000 7.050 70.800 7.350 ;
    LAYER MET3 ;
    RECT 0.650 7.350 70.150 7.650 ;
    LAYER MET3 ;
    RECT 0.000 7.650 70.800 7.950 ;
    LAYER MET3 ;
    RECT 0.650 7.950 70.150 8.250 ;
    LAYER MET3 ;
    RECT 0.000 8.250 70.800 8.550 ;
    LAYER MET3 ;
    RECT 0.650 8.550 70.150 8.850 ;
    LAYER MET3 ;
    RECT 0.000 8.850 70.800 9.150 ;
    LAYER MET3 ;
    RECT 0.650 9.150 70.150 9.450 ;
    LAYER MET3 ;
    RECT 0.000 9.450 70.800 9.750 ;
    LAYER MET3 ;
    RECT 0.650 9.750 70.150 10.050 ;
    LAYER MET3 ;
    RECT 0.000 10.050 70.800 10.350 ;
    LAYER MET3 ;
    RECT 0.650 10.350 70.150 10.650 ;
    LAYER MET3 ;
    RECT 0.000 10.650 70.800 10.950 ;
    LAYER MET3 ;
    RECT 0.650 10.950 70.150 11.250 ;
    LAYER MET3 ;
    RECT 0.000 11.250 70.800 11.550 ;
    LAYER MET3 ;
    RECT 0.650 11.550 70.150 11.850 ;
    LAYER MET3 ;
    RECT 0.000 11.850 70.800 12.150 ;
    LAYER MET3 ;
    RECT 0.650 12.150 70.150 12.450 ;
    LAYER MET3 ;
    RECT 0.000 12.450 70.800 12.750 ;
    LAYER MET3 ;
    RECT 0.650 12.750 70.150 13.050 ;
    LAYER MET3 ;
    RECT 0.000 13.050 70.800 13.350 ;
    LAYER MET3 ;
    RECT 0.650 13.350 70.150 13.650 ;
    LAYER MET3 ;
    RECT 0.000 13.650 70.800 13.950 ;
    LAYER MET3 ;
    RECT 0.650 13.950 70.150 14.250 ;
    LAYER MET3 ;
    RECT 0.000 14.250 70.800 14.550 ;
    LAYER MET3 ;
    RECT 0.650 14.550 70.150 14.850 ;
    LAYER MET3 ;
    RECT 0.000 14.850 70.800 15.150 ;
    LAYER MET3 ;
    RECT 0.650 15.150 70.150 15.450 ;
    LAYER MET3 ;
    RECT 0.000 15.450 70.800 15.750 ;
    LAYER MET3 ;
    RECT 0.650 15.750 70.150 16.050 ;
    LAYER MET3 ;
    RECT 0.000 16.050 70.800 16.350 ;
    LAYER MET3 ;
    RECT 0.650 16.350 70.150 16.650 ;
    LAYER MET3 ;
    RECT 0.000 16.650 70.800 16.950 ;
    LAYER MET3 ;
    RECT 0.650 16.950 70.150 17.250 ;
    LAYER MET3 ;
    RECT 0.000 17.250 70.800 17.550 ;
    LAYER MET3 ;
    RECT 0.650 17.550 70.150 17.850 ;
    LAYER MET3 ;
    RECT 0.000 17.850 70.800 18.150 ;
    LAYER MET3 ;
    RECT 0.650 18.150 70.150 18.450 ;
    LAYER MET3 ;
    RECT 0.000 18.450 70.800 18.750 ;
    LAYER MET3 ;
    RECT 0.650 18.750 70.150 19.050 ;
    LAYER MET3 ;
    RECT 0.000 19.050 70.800 19.350 ;
    LAYER MET3 ;
    RECT 0.650 19.350 70.150 19.650 ;
    LAYER MET3 ;
    RECT 0.000 19.650 70.800 19.950 ;
    LAYER MET3 ;
    RECT 0.650 19.950 70.150 20.250 ;
    LAYER MET3 ;
    RECT 0.000 20.250 70.800 20.550 ;
    LAYER MET3 ;
    RECT 0.650 20.550 70.150 20.850 ;
    LAYER MET3 ;
    RECT 0.000 20.850 70.800 21.150 ;
    LAYER MET3 ;
    RECT 0.650 21.150 70.150 21.450 ;
    LAYER MET3 ;
    RECT 0.000 21.450 70.800 21.750 ;
    LAYER MET3 ;
    RECT 0.650 21.750 70.150 22.050 ;
    LAYER MET3 ;
    RECT 0.000 22.050 70.800 22.350 ;
    LAYER MET3 ;
    RECT 0.650 22.350 70.150 22.650 ;
    LAYER MET3 ;
    RECT 0.000 22.650 70.800 22.950 ;
    LAYER MET3 ;
    RECT 0.650 22.950 70.150 23.250 ;
    LAYER MET3 ;
    RECT 0.000 23.250 70.800 23.550 ;
    LAYER MET3 ;
    RECT 0.650 23.550 70.150 23.850 ;
    LAYER MET3 ;
    RECT 0.000 23.850 70.800 24.150 ;
    LAYER MET3 ;
    RECT 0.650 24.150 70.150 24.450 ;
    LAYER MET3 ;
    RECT 0.000 24.450 70.800 24.750 ;
    LAYER MET3 ;
    RECT 0.650 24.750 70.150 25.050 ;
    LAYER MET3 ;
    RECT 0.000 25.050 70.800 25.350 ;
    LAYER MET3 ;
    RECT 0.650 25.350 70.150 25.650 ;
    LAYER MET3 ;
    RECT 0.000 25.650 70.800 25.950 ;
    LAYER MET3 ;
    RECT 0.650 25.950 70.150 26.250 ;
    LAYER MET3 ;
    RECT 0.000 26.250 70.800 26.550 ;
    LAYER MET3 ;
    RECT 0.650 26.550 70.150 26.850 ;
    LAYER MET3 ;
    RECT 0.000 26.850 70.800 27.150 ;
    LAYER MET3 ;
    RECT 0.650 27.150 70.150 27.450 ;
    LAYER MET3 ;
    RECT 0.000 27.450 70.800 27.750 ;
    LAYER MET3 ;
    RECT 0.650 27.750 70.150 28.050 ;
    LAYER MET3 ;
    RECT 0.000 28.050 70.800 28.350 ;
    LAYER MET3 ;
    RECT 0.650 28.350 70.150 28.650 ;
    LAYER MET3 ;
    RECT 0.000 28.650 70.800 28.950 ;
    LAYER MET3 ;
    RECT 0.650 28.950 70.150 29.250 ;
    LAYER MET3 ;
    RECT 0.000 29.250 70.800 29.550 ;
    LAYER MET3 ;
    RECT 0.650 29.550 70.150 29.850 ;
    LAYER MET3 ;
    RECT 0.000 29.850 70.800 30.150 ;
    LAYER MET3 ;
    RECT 0.650 30.150 70.150 30.450 ;
    LAYER MET3 ;
    RECT 0.000 30.450 70.800 30.750 ;
    LAYER MET3 ;
    RECT 0.650 30.750 70.150 31.050 ;
    LAYER MET3 ;
    RECT 0.000 31.050 70.800 31.350 ;
    LAYER MET3 ;
    RECT 0.650 31.350 70.150 31.650 ;
    LAYER MET3 ;
    RECT 0.000 31.650 70.800 31.950 ;
    LAYER MET3 ;
    RECT 0.650 31.950 70.150 32.250 ;
    LAYER MET3 ;
    RECT 0.000 32.250 70.800 32.550 ;
    LAYER MET3 ;
    RECT 0.650 32.550 70.150 32.850 ;
    LAYER MET3 ;
    RECT 0.000 32.850 70.800 33.150 ;
    LAYER MET3 ;
    RECT 0.650 33.150 70.150 33.450 ;
    LAYER MET3 ;
    RECT 0.000 33.450 70.800 33.750 ;
    LAYER MET3 ;
    RECT 0.650 33.750 70.150 34.050 ;
    LAYER MET3 ;
    RECT 0.000 34.050 70.800 34.350 ;
    LAYER MET3 ;
    RECT 0.650 34.350 70.150 34.650 ;
    LAYER MET3 ;
    RECT 0.000 34.650 70.800 34.950 ;
    LAYER MET3 ;
    RECT 0.650 34.950 70.150 35.250 ;
    LAYER MET3 ;
    RECT 0.000 35.250 70.800 35.550 ;
    LAYER MET3 ;
    RECT 0.650 35.550 70.150 35.850 ;
    LAYER MET3 ;
    RECT 0.000 35.850 70.800 36.150 ;
    LAYER MET3 ;
    RECT 0.650 36.150 70.150 36.450 ;
    LAYER MET3 ;
    RECT 0.000 36.450 70.800 36.750 ;
    LAYER MET3 ;
    RECT 0.650 36.750 70.150 37.050 ;
    LAYER MET3 ;
    RECT 0.000 37.050 70.800 37.350 ;
    LAYER MET3 ;
    RECT 0.650 37.350 70.150 37.650 ;
    LAYER MET3 ;
    RECT 0.000 37.650 70.800 37.950 ;
    LAYER MET3 ;
    RECT 0.650 37.950 70.150 38.250 ;
    LAYER MET3 ;
    RECT 0.000 38.250 70.800 38.550 ;
    LAYER MET3 ;
    RECT 0.650 38.550 70.150 38.850 ;
    LAYER MET3 ;
    RECT 0.000 38.850 70.800 39.150 ;
    LAYER MET3 ;
    RECT 0.650 39.150 70.150 39.450 ;
    LAYER MET3 ;
    RECT 0.000 39.450 70.800 39.750 ;
    LAYER MET3 ;
    RECT 0.650 39.750 70.150 40.050 ;
    LAYER MET3 ;
    RECT 0.000 40.050 70.800 40.350 ;
    LAYER MET3 ;
    RECT 0.650 40.350 70.150 40.650 ;
    LAYER MET3 ;
    RECT 0.000 40.650 70.800 40.950 ;
    LAYER MET3 ;
    RECT 0.650 40.950 70.150 41.250 ;
    LAYER MET3 ;
    RECT 0.000 41.250 70.800 41.550 ;
    LAYER MET3 ;
    RECT 0.650 41.550 70.150 41.850 ;
    LAYER MET3 ;
    RECT 0.000 41.850 70.800 42.150 ;
    LAYER MET3 ;
    RECT 0.650 42.150 70.150 42.450 ;
    LAYER MET3 ;
    RECT 0.000 42.450 70.800 42.750 ;
    LAYER MET3 ;
    RECT 0.650 42.750 70.150 43.050 ;
    LAYER MET3 ;
    RECT 0.000 43.050 70.800 43.350 ;
    LAYER MET3 ;
    RECT 0.650 43.350 70.150 43.650 ;
    LAYER MET3 ;
    RECT 0.000 43.650 70.800 43.950 ;
    LAYER MET3 ;
    RECT 0.650 43.950 70.150 44.250 ;
    LAYER MET3 ;
    RECT 0.000 44.250 70.800 44.550 ;
    LAYER MET3 ;
    RECT 0.650 44.550 70.150 44.850 ;
    LAYER MET3 ;
    RECT 0.000 44.850 70.800 45.150 ;
    LAYER MET3 ;
    RECT 0.650 45.150 70.150 45.450 ;
    LAYER MET3 ;
    RECT 0.000 45.450 70.800 45.750 ;
    LAYER MET3 ;
    RECT 0.650 45.750 70.150 46.050 ;
    LAYER MET3 ;
    RECT 0.000 46.050 70.800 46.350 ;
    LAYER MET3 ;
    RECT 0.650 46.350 70.150 46.650 ;
    LAYER MET3 ;
    RECT 0.000 46.650 70.800 46.950 ;
    LAYER MET3 ;
    RECT 0.650 46.950 70.150 47.250 ;
    LAYER MET3 ;
    RECT 0.000 47.250 70.800 47.550 ;
    LAYER MET3 ;
    RECT 0.650 47.550 70.150 47.850 ;
    LAYER MET3 ;
    RECT 0.000 47.850 70.800 48.150 ;
    LAYER MET3 ;
    RECT 0.650 48.150 70.150 48.450 ;
    LAYER MET3 ;
    RECT 0.000 48.450 70.800 48.750 ;
    LAYER MET3 ;
    RECT 0.650 48.750 70.150 49.050 ;
    LAYER MET3 ;
    RECT 0.000 49.050 70.800 49.350 ;
    LAYER MET3 ;
    RECT 0.650 49.350 70.150 49.650 ;
    LAYER MET3 ;
    RECT 0.000 49.650 70.800 49.950 ;
    LAYER MET3 ;
    RECT 0.650 49.950 70.150 50.250 ;
    LAYER MET3 ;
    RECT 0.000 50.250 70.800 50.550 ;
    LAYER MET3 ;
    RECT 0.650 50.550 70.150 50.850 ;
    LAYER MET3 ;
    RECT 0.000 50.850 70.800 51.150 ;
    LAYER MET3 ;
    RECT 0.650 51.150 70.150 51.450 ;
    LAYER MET3 ;
    RECT 0.000 51.450 70.800 51.750 ;
    LAYER MET3 ;
    RECT 0.650 51.750 70.150 52.050 ;
    LAYER MET3 ;
    RECT 0.000 52.050 70.800 52.350 ;
    LAYER MET3 ;
    RECT 0.650 52.350 70.150 52.650 ;
    LAYER MET3 ;
    RECT 0.000 52.650 70.800 52.950 ;
    LAYER MET3 ;
    RECT 0.650 52.950 70.150 53.250 ;
    LAYER MET3 ;
    RECT 0.000 53.250 70.800 53.550 ;
    LAYER MET3 ;
    RECT 0.650 53.550 70.150 53.850 ;
    LAYER MET3 ;
    RECT 0.000 53.850 70.800 54.150 ;
    LAYER MET3 ;
    RECT 0.650 54.150 70.150 54.450 ;
    LAYER MET3 ;
    RECT 0.000 54.450 70.800 54.750 ;
    LAYER MET3 ;
    RECT 0.650 54.750 70.150 55.050 ;
    LAYER MET3 ;
    RECT 0.000 55.050 70.800 55.350 ;
    LAYER MET3 ;
    RECT 0.650 55.350 70.150 55.650 ;
    LAYER MET3 ;
    RECT 0.000 55.650 70.800 55.950 ;
    LAYER MET3 ;
    RECT 0.650 55.950 70.150 56.250 ;
    LAYER MET3 ;
    RECT 0.000 56.250 70.800 56.550 ;
    LAYER MET3 ;
    RECT 0.650 56.550 70.150 56.850 ;
    LAYER MET3 ;
    RECT 0.000 56.850 70.800 57.150 ;
    LAYER MET3 ;
    RECT 0.650 57.150 70.150 57.450 ;
    LAYER MET3 ;
    RECT 0.000 57.450 70.800 57.750 ;
    LAYER MET3 ;
    RECT 0.650 57.750 70.150 58.050 ;
    LAYER MET3 ;
    RECT 0.000 58.050 70.800 58.350 ;
    LAYER MET3 ;
    RECT 0.650 58.350 70.150 58.650 ;
    LAYER MET3 ;
    RECT 0.000 58.650 70.800 58.950 ;
    LAYER MET3 ;
    RECT 0.650 58.950 70.150 59.250 ;
    LAYER MET3 ;
    RECT 0.000 59.250 70.800 59.550 ;
    LAYER MET3 ;
    RECT 0.650 59.550 70.150 59.850 ;
    LAYER MET3 ;
    RECT 0.000 59.850 70.800 60.150 ;
    LAYER MET3 ;
    RECT 0.650 60.150 70.150 60.450 ;
    LAYER MET3 ;
    RECT 0.000 60.450 70.800 60.750 ;
    LAYER MET3 ;
    RECT 0.650 60.750 70.150 61.050 ;
    LAYER MET3 ;
    RECT 0.000 61.050 70.800 61.350 ;
    LAYER MET3 ;
    RECT 0.650 61.350 70.150 61.650 ;
    LAYER MET3 ;
    RECT 0.000 61.650 70.800 61.950 ;
    LAYER MET3 ;
    RECT 0.650 61.950 70.150 62.250 ;
    LAYER MET3 ;
    RECT 0.000 62.250 70.800 62.550 ;
    LAYER MET3 ;
    RECT 0.650 62.550 70.150 62.850 ;
    LAYER MET3 ;
    RECT 0.000 62.850 70.800 63.150 ;
    LAYER MET3 ;
    RECT 0.650 63.150 70.150 63.450 ;
    LAYER MET3 ;
    RECT 0.000 63.450 70.800 63.750 ;
    LAYER MET3 ;
    RECT 0.650 63.750 70.150 64.050 ;
    LAYER MET3 ;
    RECT 0.000 64.050 70.800 64.350 ;
    LAYER MET3 ;
    RECT 0.650 64.350 70.150 64.650 ;
    LAYER MET3 ;
    RECT 0.000 64.650 70.800 64.950 ;
    LAYER MET3 ;
    RECT 0.650 64.950 70.150 65.250 ;
    LAYER MET3 ;
    RECT 0.000 65.250 70.800 65.550 ;
    LAYER MET3 ;
    RECT 0.650 65.550 70.150 65.850 ;
    LAYER MET3 ;
    RECT 0.000 65.850 70.800 66.150 ;
    LAYER MET3 ;
    RECT 0.650 66.150 70.150 66.450 ;
    LAYER MET3 ;
    RECT 0.000 66.450 70.800 66.750 ;
    LAYER MET3 ;
    RECT 0.650 66.750 70.150 67.050 ;
    LAYER MET3 ;
    RECT 0.000 67.050 70.800 67.350 ;
    LAYER MET3 ;
    RECT 0.650 67.350 70.150 67.650 ;
    LAYER MET3 ;
    RECT 0.000 67.650 70.800 67.950 ;
    LAYER MET3 ;
    RECT 0.650 67.950 70.150 68.250 ;
    LAYER MET3 ;
    RECT 0.000 68.250 70.800 68.550 ;
    LAYER MET3 ;
    RECT 0.650 68.550 70.150 68.850 ;
    LAYER MET3 ;
    RECT 0.000 68.850 70.800 69.150 ;
    LAYER MET3 ;
    RECT 0.650 69.150 70.150 69.450 ;
    LAYER MET3 ;
    RECT 0.000 69.450 70.800 69.750 ;
    LAYER MET3 ;
    RECT 0.650 69.750 70.150 70.050 ;
    LAYER MET3 ;
    RECT 0.000 70.050 70.800 70.350 ;
    LAYER MET3 ;
    RECT 0.650 70.350 70.150 70.650 ;
    LAYER MET3 ;
    RECT 0.000 70.650 70.800 70.950 ;
    LAYER MET3 ;
    RECT 0.650 70.950 70.150 71.250 ;
    LAYER MET3 ;
    RECT 0.000 71.250 70.800 71.550 ;
    LAYER MET3 ;
    RECT 0.650 71.550 70.150 71.850 ;
    LAYER MET3 ;
    RECT 0.000 71.850 70.800 72.150 ;
    LAYER MET3 ;
    RECT 0.650 72.150 70.150 72.450 ;
    LAYER MET3 ;
    RECT 0.000 72.450 70.800 72.750 ;
    LAYER MET3 ;
    RECT 0.650 72.750 70.150 73.050 ;
    LAYER MET3 ;
    RECT 0.000 73.050 70.800 73.350 ;
    LAYER MET3 ;
    RECT 0.650 73.350 70.150 73.650 ;
    LAYER MET3 ;
    RECT 0.000 73.650 70.800 73.950 ;
    LAYER MET3 ;
    RECT 0.650 73.950 70.150 74.250 ;
    LAYER MET3 ;
    RECT 0.000 74.250 70.800 74.550 ;
    LAYER MET3 ;
    RECT 0.650 74.550 70.150 74.850 ;
    LAYER MET3 ;
    RECT 0.000 74.850 70.800 75.150 ;
    LAYER MET3 ;
    RECT 0.650 75.150 70.150 75.450 ;
    LAYER MET3 ;
    RECT 0.000 75.450 70.800 75.750 ;
    LAYER MET3 ;
    RECT 0.650 75.750 70.150 76.050 ;
    LAYER MET3 ;
    RECT 0.000 76.050 70.800 76.350 ;
    LAYER MET3 ;
    RECT 0.650 76.350 70.150 76.650 ;
    LAYER MET3 ;
    RECT 0.000 76.650 70.800 76.950 ;
    LAYER MET3 ;
    RECT 0.650 76.950 70.150 77.250 ;
    LAYER MET3 ;
    RECT 0.000 77.250 70.800 77.550 ;
    LAYER MET3 ;
    RECT 0.650 77.550 70.150 77.850 ;
    LAYER MET3 ;
    RECT 0.000 77.850 70.800 78.150 ;
    LAYER MET3 ;
    RECT 0.650 78.150 70.150 78.450 ;
    LAYER MET3 ;
    RECT 0.000 78.450 70.800 78.750 ;
    LAYER MET3 ;
    RECT 0.650 78.750 70.150 79.050 ;
    LAYER MET3 ;
    RECT 0.000 79.050 70.800 79.350 ;
    LAYER MET3 ;
    RECT 0.650 79.350 70.150 79.650 ;
    LAYER MET3 ;
    RECT 0.000 79.650 70.800 79.950 ;
    LAYER MET3 ;
    RECT 0.650 79.950 70.150 80.250 ;
    LAYER MET3 ;
    RECT 0.000 80.250 70.800 87.750 ;
    LAYER MET3 ;
    RECT 0.650 87.750 70.150 88.050 ;
    LAYER MET3 ;
    RECT 0.000 88.050 70.800 88.350 ;
    LAYER MET3 ;
    RECT 0.650 88.350 70.150 88.650 ;
    LAYER MET3 ;
    RECT 0.000 88.650 70.800 88.950 ;
    LAYER MET3 ;
    RECT 0.650 88.950 70.150 89.250 ;
    LAYER MET3 ;
    RECT 0.000 89.250 70.800 89.550 ;
    LAYER MET3 ;
    RECT 0.650 89.550 70.150 89.850 ;
    LAYER MET3 ;
    RECT 0.000 89.850 70.800 90.150 ;
    LAYER MET3 ;
    RECT 0.650 90.150 70.150 90.450 ;
    LAYER MET3 ;
    RECT 0.000 90.450 70.800 90.750 ;
    LAYER MET3 ;
    RECT 0.650 90.750 70.150 91.050 ;
    LAYER MET3 ;
    RECT 0.000 91.050 70.800 91.350 ;
    LAYER MET3 ;
    RECT 0.650 91.350 70.150 91.650 ;
    LAYER MET3 ;
    RECT 0.000 91.650 70.800 91.950 ;
    LAYER MET3 ;
    RECT 0.650 91.950 70.150 92.250 ;
    LAYER MET3 ;
    RECT 0.000 92.250 70.800 92.550 ;
    LAYER MET3 ;
    RECT 0.650 92.550 70.150 92.850 ;
    LAYER MET3 ;
    RECT 0.000 92.850 70.800 93.150 ;
    LAYER MET3 ;
    RECT 0.650 93.150 70.150 93.450 ;
    LAYER MET3 ;
    RECT 0.000 93.450 70.800 93.750 ;
    LAYER MET3 ;
    RECT 0.650 93.750 70.150 94.050 ;
    LAYER MET3 ;
    RECT 0.000 94.050 70.800 94.350 ;
    LAYER MET3 ;
    RECT 0.650 94.350 70.150 94.650 ;
    LAYER MET3 ;
    RECT 0.000 94.650 70.800 94.950 ;
    LAYER MET3 ;
    RECT 0.650 94.950 70.150 95.250 ;
    LAYER MET3 ;
    RECT 0.000 95.250 70.800 95.550 ;
    LAYER MET3 ;
    RECT 0.650 95.550 70.150 95.850 ;
    LAYER MET3 ;
    RECT 0.000 95.850 70.800 96.150 ;
    LAYER MET3 ;
    RECT 0.650 96.150 70.150 96.450 ;
    LAYER MET3 ;
    RECT 0.000 96.450 70.800 96.750 ;
    LAYER MET3 ;
    RECT 0.650 96.750 70.150 97.050 ;
    LAYER MET3 ;
    RECT 0.000 97.050 70.800 97.350 ;
    LAYER MET3 ;
    RECT 0.650 97.350 70.150 97.650 ;
    LAYER MET3 ;
    RECT 0.000 97.650 70.800 97.950 ;
    LAYER MET3 ;
    RECT 0.650 97.950 70.150 98.250 ;
    LAYER MET3 ;
    RECT 0.000 98.250 70.800 98.550 ;
    LAYER MET3 ;
    RECT 0.650 98.550 70.150 98.850 ;
    LAYER MET3 ;
    RECT 0.000 98.850 70.800 99.150 ;
    LAYER MET3 ;
    RECT 0.650 99.150 70.150 99.450 ;
    LAYER MET3 ;
    RECT 0.000 99.450 70.800 99.750 ;
    LAYER MET3 ;
    RECT 0.650 99.750 70.150 100.050 ;
    LAYER MET3 ;
    RECT 0.000 100.050 70.800 100.350 ;
    LAYER MET3 ;
    RECT 0.650 100.350 70.150 100.650 ;
    LAYER MET3 ;
    RECT 0.000 100.650 70.800 100.950 ;
    LAYER MET3 ;
    RECT 0.650 100.950 70.150 101.250 ;
    LAYER MET3 ;
    RECT 0.000 101.250 70.800 101.550 ;
    LAYER MET3 ;
    RECT 0.650 101.550 70.150 101.850 ;
    LAYER MET3 ;
    RECT 0.000 101.850 70.800 102.150 ;
    LAYER MET3 ;
    RECT 0.650 102.150 70.150 102.450 ;
    LAYER MET3 ;
    RECT 0.000 102.450 70.800 102.750 ;
    LAYER MET3 ;
    RECT 0.650 102.750 70.150 103.050 ;
    LAYER MET3 ;
    RECT 0.000 103.050 70.800 103.350 ;
    LAYER MET3 ;
    RECT 0.650 103.350 70.150 103.650 ;
    LAYER MET3 ;
    RECT 0.000 103.650 70.800 103.950 ;
    LAYER MET3 ;
    RECT 0.650 103.950 70.150 104.250 ;
    LAYER MET3 ;
    RECT 0.000 104.250 70.800 104.550 ;
    LAYER MET3 ;
    RECT 0.650 104.550 70.150 104.850 ;
    LAYER MET3 ;
    RECT 0.000 104.850 70.800 105.150 ;
    LAYER MET3 ;
    RECT 0.650 105.150 70.150 105.450 ;
    LAYER MET3 ;
    RECT 0.000 105.450 70.800 105.750 ;
    LAYER MET3 ;
    RECT 0.650 105.750 70.150 106.050 ;
    LAYER MET3 ;
    RECT 0.000 106.050 70.800 106.350 ;
    LAYER MET3 ;
    RECT 0.650 106.350 70.150 106.650 ;
    LAYER MET3 ;
    RECT 0.000 106.650 70.800 106.950 ;
    LAYER MET3 ;
    RECT 0.650 106.950 70.150 107.250 ;
    LAYER MET3 ;
    RECT 0.000 107.250 70.800 107.550 ;
    LAYER MET3 ;
    RECT 0.650 107.550 70.150 107.850 ;
    LAYER MET3 ;
    RECT 0.000 107.850 70.800 108.150 ;
    LAYER MET3 ;
    RECT 0.650 108.150 70.150 108.450 ;
    LAYER MET3 ;
    RECT 0.000 108.450 70.800 108.750 ;
    LAYER MET3 ;
    RECT 0.650 108.750 70.150 109.050 ;
    LAYER MET3 ;
    RECT 0.000 109.050 70.800 109.350 ;
    LAYER MET3 ;
    RECT 0.650 109.350 70.150 109.650 ;
    LAYER MET3 ;
    RECT 0.000 109.650 70.800 109.950 ;
    LAYER MET3 ;
    RECT 0.650 109.950 70.150 110.250 ;
    LAYER MET3 ;
    RECT 0.000 110.250 70.800 110.550 ;
    LAYER MET3 ;
    RECT 0.650 110.550 70.150 110.850 ;
    LAYER MET3 ;
    RECT 0.000 110.850 70.800 111.150 ;
    LAYER MET3 ;
    RECT 0.650 111.150 70.150 111.450 ;
    LAYER MET3 ;
    RECT 0.000 111.450 70.800 111.750 ;
    LAYER MET3 ;
    RECT 0.650 111.750 70.150 112.050 ;
    LAYER MET3 ;
    RECT 0.000 112.050 70.800 112.350 ;
    LAYER MET3 ;
    RECT 0.650 112.350 70.150 112.650 ;
    LAYER MET3 ;
    RECT 0.000 112.650 70.800 112.950 ;
    LAYER MET3 ;
    RECT 0.650 112.950 70.150 113.250 ;
    LAYER MET3 ;
    RECT 0.000 113.250 70.800 113.550 ;
    LAYER MET3 ;
    RECT 0.650 113.550 70.150 113.850 ;
    LAYER MET3 ;
    RECT 0.000 113.850 70.800 114.150 ;
    LAYER MET3 ;
    RECT 0.650 114.150 70.150 114.450 ;
    LAYER MET3 ;
    RECT 0.000 114.450 70.800 114.750 ;
    LAYER MET3 ;
    RECT 0.650 114.750 70.150 115.050 ;
    LAYER MET3 ;
    RECT 0.000 115.050 70.800 115.350 ;
    LAYER MET3 ;
    RECT 0.650 115.350 70.150 115.650 ;
    LAYER MET3 ;
    RECT 0.000 115.650 70.800 115.950 ;
    LAYER MET3 ;
    RECT 0.650 115.950 70.150 116.250 ;
    LAYER MET3 ;
    RECT 0.000 116.250 70.800 116.550 ;
    LAYER MET3 ;
    RECT 0.650 116.550 70.150 116.850 ;
    LAYER MET3 ;
    RECT 0.000 116.850 70.800 117.150 ;
    LAYER MET3 ;
    RECT 0.650 117.150 70.150 117.450 ;
    LAYER MET3 ;
    RECT 0.000 117.450 70.800 117.750 ;
    LAYER MET3 ;
    RECT 0.650 117.750 70.150 118.050 ;
    LAYER MET3 ;
    RECT 0.000 118.050 70.800 118.350 ;
    LAYER MET3 ;
    RECT 0.650 118.350 70.150 118.650 ;
    LAYER MET3 ;
    RECT 0.000 118.650 70.800 118.950 ;
    LAYER MET3 ;
    RECT 0.650 118.950 70.150 119.250 ;
    LAYER MET3 ;
    RECT 0.000 119.250 70.800 119.550 ;
    LAYER MET3 ;
    RECT 0.650 119.550 70.150 119.850 ;
    LAYER MET3 ;
    RECT 0.000 119.850 70.800 120.150 ;
    LAYER MET3 ;
    RECT 0.650 120.150 70.150 120.450 ;
    LAYER MET3 ;
    RECT 0.000 120.450 70.800 120.750 ;
    LAYER MET3 ;
    RECT 0.650 120.750 70.150 121.050 ;
    LAYER MET3 ;
    RECT 0.000 121.050 70.800 121.350 ;
    LAYER MET3 ;
    RECT 0.650 121.350 70.150 121.650 ;
    LAYER MET3 ;
    RECT 0.000 121.650 70.800 121.950 ;
    LAYER MET3 ;
    RECT 0.650 121.950 70.150 122.250 ;
    LAYER MET3 ;
    RECT 0.000 122.250 70.800 122.550 ;
    LAYER MET3 ;
    RECT 0.650 122.550 70.150 122.850 ;
    LAYER MET3 ;
    RECT 0.000 122.850 70.800 123.150 ;
    LAYER MET3 ;
    RECT 0.650 123.150 70.150 123.450 ;
    LAYER MET3 ;
    RECT 0.000 123.450 70.800 123.750 ;
    LAYER MET3 ;
    RECT 0.650 123.750 70.150 124.050 ;
    LAYER MET3 ;
    RECT 0.000 124.050 70.800 124.350 ;
    LAYER MET3 ;
    RECT 0.650 124.350 70.150 124.650 ;
    LAYER MET3 ;
    RECT 0.000 124.650 70.800 124.950 ;
    LAYER MET3 ;
    RECT 0.650 124.950 70.150 125.250 ;
    LAYER MET3 ;
    RECT 0.000 125.250 70.800 125.550 ;
    LAYER MET3 ;
    RECT 0.650 125.550 70.150 125.850 ;
    LAYER MET3 ;
    RECT 0.000 125.850 70.800 126.150 ;
    LAYER MET3 ;
    RECT 0.650 126.150 70.150 126.450 ;
    LAYER MET3 ;
    RECT 0.000 126.450 70.800 126.750 ;
    LAYER MET3 ;
    RECT 0.650 126.750 70.150 127.050 ;
    LAYER MET3 ;
    RECT 0.000 127.050 70.800 127.350 ;
    LAYER MET3 ;
    RECT 0.650 127.350 70.150 127.650 ;
    LAYER MET3 ;
    RECT 0.000 127.650 70.800 127.950 ;
    LAYER MET3 ;
    RECT 0.650 127.950 70.150 128.250 ;
    LAYER MET3 ;
    RECT 0.000 128.250 70.800 128.550 ;
    LAYER MET3 ;
    RECT 0.650 128.550 70.150 128.850 ;
    LAYER MET3 ;
    RECT 0.000 128.850 70.800 129.150 ;
    LAYER MET3 ;
    RECT 0.650 129.150 70.150 129.450 ;
    LAYER MET3 ;
    RECT 0.000 129.450 70.800 129.750 ;
    LAYER MET3 ;
    RECT 0.650 129.750 70.150 130.050 ;
    LAYER MET3 ;
    RECT 0.000 130.050 70.800 130.350 ;
    LAYER MET3 ;
    RECT 0.650 130.350 70.150 130.650 ;
    LAYER MET3 ;
    RECT 0.000 130.650 70.800 130.950 ;
    LAYER MET3 ;
    RECT 0.650 130.950 70.150 131.250 ;
    LAYER MET3 ;
    RECT 0.000 131.250 70.800 131.550 ;
    LAYER MET3 ;
    RECT 0.650 131.550 70.150 131.850 ;
    LAYER MET3 ;
    RECT 0.000 131.850 70.800 132.150 ;
    LAYER MET3 ;
    RECT 0.650 132.150 70.150 132.450 ;
    LAYER MET3 ;
    RECT 0.000 132.450 70.800 132.750 ;
    LAYER MET3 ;
    RECT 0.650 132.750 70.150 133.050 ;
    LAYER MET3 ;
    RECT 0.000 133.050 70.800 133.350 ;
    LAYER MET3 ;
    RECT 0.650 133.350 70.150 133.650 ;
    LAYER MET3 ;
    RECT 0.000 133.650 70.800 133.950 ;
    LAYER MET3 ;
    RECT 0.650 133.950 70.150 134.250 ;
    LAYER MET3 ;
    RECT 0.000 134.250 70.800 134.550 ;
    LAYER MET3 ;
    RECT 0.650 134.550 70.150 134.850 ;
    LAYER MET3 ;
    RECT 0.000 134.850 70.800 135.150 ;
    LAYER MET3 ;
    RECT 0.650 135.150 70.150 135.450 ;
    LAYER MET3 ;
    RECT 0.000 135.450 70.800 135.750 ;
    LAYER MET3 ;
    RECT 0.650 135.750 70.150 136.050 ;
    LAYER MET3 ;
    RECT 0.000 136.050 70.800 136.350 ;
    LAYER MET3 ;
    RECT 0.650 136.350 70.150 136.650 ;
    LAYER MET3 ;
    RECT 0.000 136.650 70.800 136.950 ;
    LAYER MET3 ;
    RECT 0.650 136.950 70.150 137.250 ;
    LAYER MET3 ;
    RECT 0.000 137.250 70.800 137.550 ;
    LAYER MET3 ;
    RECT 0.650 137.550 70.150 137.850 ;
    LAYER MET3 ;
    RECT 0.000 137.850 70.800 138.150 ;
    LAYER MET3 ;
    RECT 0.650 138.150 70.150 138.450 ;
    LAYER MET3 ;
    RECT 0.000 138.450 70.800 138.750 ;
    LAYER MET3 ;
    RECT 0.650 138.750 70.150 139.050 ;
    LAYER MET3 ;
    RECT 0.000 139.050 70.800 139.350 ;
    LAYER MET3 ;
    RECT 0.650 139.350 70.150 139.650 ;
    LAYER MET3 ;
    RECT 0.000 139.650 70.800 139.950 ;
    LAYER MET3 ;
    RECT 0.650 139.950 70.150 140.250 ;
    LAYER MET3 ;
    RECT 0.000 140.250 70.800 140.550 ;
    LAYER MET3 ;
    RECT 0.650 140.550 70.150 140.850 ;
    LAYER MET3 ;
    RECT 0.000 140.850 70.800 141.150 ;
    LAYER MET3 ;
    RECT 0.650 141.150 70.150 141.450 ;
    LAYER MET3 ;
    RECT 0.000 141.450 70.800 141.750 ;
    LAYER MET3 ;
    RECT 0.650 141.750 70.150 142.050 ;
    LAYER MET3 ;
    RECT 0.000 142.050 70.800 142.350 ;
    LAYER MET3 ;
    RECT 0.650 142.350 70.150 142.650 ;
    LAYER MET3 ;
    RECT 0.000 142.650 70.800 142.950 ;
    LAYER MET3 ;
    RECT 0.650 142.950 70.150 143.250 ;
    LAYER MET3 ;
    RECT 0.000 143.250 70.800 143.550 ;
    LAYER MET3 ;
    RECT 0.650 143.550 70.150 143.850 ;
    LAYER MET3 ;
    RECT 0.000 143.850 70.800 144.150 ;
    LAYER MET3 ;
    RECT 0.650 144.150 70.150 144.450 ;
    LAYER MET3 ;
    RECT 0.000 144.450 70.800 144.750 ;
    LAYER MET3 ;
    RECT 0.650 144.750 70.150 145.050 ;
    LAYER MET3 ;
    RECT 0.000 145.050 70.800 145.350 ;
    LAYER MET3 ;
    RECT 0.650 145.350 70.150 145.650 ;
    LAYER MET3 ;
    RECT 0.000 145.650 70.800 145.950 ;
    LAYER MET3 ;
    RECT 0.650 145.950 70.150 146.250 ;
    LAYER MET3 ;
    RECT 0.000 146.250 70.800 146.550 ;
    LAYER MET3 ;
    RECT 0.650 146.550 70.150 146.850 ;
    LAYER MET3 ;
    RECT 0.000 146.850 70.800 147.150 ;
    LAYER MET3 ;
    RECT 0.650 147.150 70.150 147.450 ;
    LAYER MET3 ;
    RECT 0.000 147.450 70.800 147.750 ;
    LAYER MET3 ;
    RECT 0.650 147.750 70.150 148.050 ;
    LAYER MET3 ;
    RECT 0.000 148.050 70.800 148.350 ;
    LAYER MET3 ;
    RECT 0.650 148.350 70.150 148.650 ;
    LAYER MET3 ;
    RECT 0.000 148.650 70.800 148.950 ;
    LAYER MET3 ;
    RECT 0.650 148.950 70.150 149.250 ;
    LAYER MET3 ;
    RECT 0.000 149.250 70.800 149.550 ;
    LAYER MET3 ;
    RECT 0.650 149.550 70.150 149.850 ;
    LAYER MET3 ;
    RECT 0.000 149.850 70.800 150.150 ;
    LAYER MET3 ;
    RECT 0.650 150.150 70.150 150.450 ;
    LAYER MET3 ;
    RECT 0.000 150.450 70.800 150.750 ;
    LAYER MET3 ;
    RECT 0.650 150.750 70.150 151.050 ;
    LAYER MET3 ;
    RECT 0.000 151.050 70.800 151.350 ;
    LAYER MET3 ;
    RECT 0.650 151.350 70.150 151.650 ;
    LAYER MET3 ;
    RECT 0.000 151.650 70.800 151.950 ;
    LAYER MET3 ;
    RECT 0.650 151.950 70.150 152.250 ;
    LAYER MET3 ;
    RECT 0.000 152.250 70.800 152.550 ;
    LAYER MET3 ;
    RECT 0.650 152.550 70.150 152.850 ;
    LAYER MET3 ;
    RECT 0.000 152.850 70.800 153.150 ;
    LAYER MET3 ;
    RECT 0.650 153.150 70.150 153.450 ;
    LAYER MET3 ;
    RECT 0.000 153.450 70.800 153.750 ;
    LAYER MET3 ;
    RECT 0.650 153.750 70.150 154.050 ;
    LAYER MET3 ;
    RECT 0.000 154.050 70.800 154.350 ;
    LAYER MET3 ;
    RECT 0.650 154.350 70.150 154.650 ;
    LAYER MET3 ;
    RECT 0.000 154.650 70.800 154.950 ;
    LAYER MET3 ;
    RECT 0.650 154.950 70.150 155.250 ;
    LAYER MET3 ;
    RECT 0.000 155.250 70.800 155.550 ;
    LAYER MET3 ;
    RECT 0.650 155.550 70.150 155.850 ;
    LAYER MET3 ;
    RECT 0.000 155.850 70.800 156.150 ;
    LAYER MET3 ;
    RECT 0.650 156.150 70.150 156.450 ;
    LAYER MET3 ;
    RECT 0.000 156.450 70.800 156.750 ;
    LAYER MET3 ;
    RECT 0.650 156.750 70.150 157.050 ;
    LAYER MET3 ;
    RECT 0.000 157.050 70.800 157.350 ;
    LAYER MET3 ;
    RECT 0.650 157.350 70.150 157.650 ;
    LAYER MET3 ;
    RECT 0.000 157.650 70.800 157.950 ;
    LAYER MET3 ;
    RECT 0.650 157.950 70.150 158.250 ;
    LAYER MET3 ;
    RECT 0.000 158.250 70.800 158.550 ;
    LAYER MET3 ;
    RECT 0.650 158.550 70.150 158.850 ;
    LAYER MET3 ;
    RECT 0.000 158.850 70.800 159.150 ;
    LAYER MET3 ;
    RECT 0.650 159.150 70.150 159.450 ;
    LAYER MET3 ;
    RECT 0.000 159.450 70.800 159.750 ;
    LAYER MET3 ;
    RECT 0.650 159.750 70.150 160.050 ;
    LAYER MET3 ;
    RECT 0.000 160.050 70.800 160.350 ;
    LAYER MET3 ;
    RECT 0.650 160.350 70.150 160.650 ;
    LAYER MET3 ;
    RECT 0.000 160.650 70.800 160.950 ;
    LAYER MET3 ;
    RECT 0.650 160.950 70.150 161.250 ;
    LAYER MET3 ;
    RECT 0.000 161.250 70.800 161.550 ;
    LAYER MET3 ;
    RECT 0.650 161.550 70.150 161.850 ;
    LAYER MET3 ;
    RECT 0.000 161.850 70.800 162.150 ;
    LAYER MET3 ;
    RECT 0.650 162.150 70.150 162.450 ;
    LAYER MET3 ;
    RECT 0.000 162.450 70.800 162.750 ;
    LAYER MET3 ;
    RECT 0.650 162.750 70.150 163.050 ;
    LAYER MET3 ;
    RECT 0.000 163.050 70.800 163.350 ;
    LAYER MET3 ;
    RECT 0.650 163.350 70.150 163.650 ;
    LAYER MET3 ;
    RECT 0.000 163.650 70.800 163.950 ;
    LAYER MET3 ;
    RECT 0.650 163.950 70.150 164.250 ;
    LAYER MET3 ;
    RECT 0.000 164.250 70.800 168.000 ;
    LAYER MET4 ;
    RECT 0.000 0.000 3.950 168.000 ;
    LAYER MET4 ;
    RECT 3.950 0.650 4.250 167.350 ;
    LAYER MET4 ;
    RECT 4.250 0.000 4.350 168.000 ;
    LAYER MET4 ;
    RECT 4.350 0.650 4.650 167.350 ;
    LAYER MET4 ;
    RECT 4.650 0.000 4.750 168.000 ;
    LAYER MET4 ;
    RECT 4.750 0.650 5.050 167.350 ;
    LAYER MET4 ;
    RECT 5.050 0.000 5.150 168.000 ;
    LAYER MET4 ;
    RECT 5.150 0.650 5.450 167.350 ;
    LAYER MET4 ;
    RECT 5.450 0.000 5.550 168.000 ;
    LAYER MET4 ;
    RECT 5.550 0.650 5.850 167.350 ;
    LAYER MET4 ;
    RECT 5.850 0.000 5.950 168.000 ;
    LAYER MET4 ;
    RECT 5.950 0.650 6.250 167.350 ;
    LAYER MET4 ;
    RECT 6.250 0.000 6.350 168.000 ;
    LAYER MET4 ;
    RECT 6.350 0.650 6.650 167.350 ;
    LAYER MET4 ;
    RECT 6.650 0.000 6.750 168.000 ;
    LAYER MET4 ;
    RECT 6.750 0.650 7.050 167.350 ;
    LAYER MET4 ;
    RECT 7.050 0.000 7.150 168.000 ;
    LAYER MET4 ;
    RECT 7.150 0.650 7.450 167.350 ;
    LAYER MET4 ;
    RECT 7.450 0.000 7.550 168.000 ;
    LAYER MET4 ;
    RECT 7.550 0.650 7.850 167.350 ;
    LAYER MET4 ;
    RECT 7.850 0.000 7.950 168.000 ;
    LAYER MET4 ;
    RECT 7.950 0.650 8.250 167.350 ;
    LAYER MET4 ;
    RECT 8.250 0.000 8.350 168.000 ;
    LAYER MET4 ;
    RECT 8.350 0.650 8.650 167.350 ;
    LAYER MET4 ;
    RECT 8.650 0.000 8.750 168.000 ;
    LAYER MET4 ;
    RECT 8.750 0.650 9.050 167.350 ;
    LAYER MET4 ;
    RECT 9.050 0.000 9.150 168.000 ;
    LAYER MET4 ;
    RECT 9.150 0.650 9.450 167.350 ;
    LAYER MET4 ;
    RECT 9.450 0.000 9.550 168.000 ;
    LAYER MET4 ;
    RECT 9.550 0.650 9.850 167.350 ;
    LAYER MET4 ;
    RECT 9.850 0.000 9.950 168.000 ;
    LAYER MET4 ;
    RECT 9.950 0.650 10.250 167.350 ;
    LAYER MET4 ;
    RECT 10.250 0.000 10.350 168.000 ;
    LAYER MET4 ;
    RECT 10.350 0.650 10.650 167.350 ;
    LAYER MET4 ;
    RECT 10.650 0.000 12.350 168.000 ;
    LAYER MET4 ;
    RECT 12.350 0.650 12.650 167.350 ;
    LAYER MET4 ;
    RECT 12.650 0.000 12.750 168.000 ;
    LAYER MET4 ;
    RECT 12.750 0.650 13.050 167.350 ;
    LAYER MET4 ;
    RECT 13.050 0.000 13.150 168.000 ;
    LAYER MET4 ;
    RECT 13.150 0.650 13.450 167.350 ;
    LAYER MET4 ;
    RECT 13.450 0.000 13.550 168.000 ;
    LAYER MET4 ;
    RECT 13.550 0.650 13.850 167.350 ;
    LAYER MET4 ;
    RECT 13.850 0.000 13.950 168.000 ;
    LAYER MET4 ;
    RECT 13.950 0.650 14.250 167.350 ;
    LAYER MET4 ;
    RECT 14.250 0.000 14.350 168.000 ;
    LAYER MET4 ;
    RECT 14.350 0.650 14.650 167.350 ;
    LAYER MET4 ;
    RECT 14.650 0.000 14.750 168.000 ;
    LAYER MET4 ;
    RECT 14.750 0.650 15.050 167.350 ;
    LAYER MET4 ;
    RECT 15.050 0.000 15.150 168.000 ;
    LAYER MET4 ;
    RECT 15.150 0.650 15.450 167.350 ;
    LAYER MET4 ;
    RECT 15.450 0.000 15.550 168.000 ;
    LAYER MET4 ;
    RECT 15.550 0.650 15.850 167.350 ;
    LAYER MET4 ;
    RECT 15.850 0.000 15.950 168.000 ;
    LAYER MET4 ;
    RECT 15.950 0.650 16.250 167.350 ;
    LAYER MET4 ;
    RECT 16.250 0.000 16.350 168.000 ;
    LAYER MET4 ;
    RECT 16.350 0.650 16.650 167.350 ;
    LAYER MET4 ;
    RECT 16.650 0.000 16.750 168.000 ;
    LAYER MET4 ;
    RECT 16.750 0.650 17.050 167.350 ;
    LAYER MET4 ;
    RECT 17.050 0.000 17.150 168.000 ;
    LAYER MET4 ;
    RECT 17.150 0.650 17.450 167.350 ;
    LAYER MET4 ;
    RECT 17.450 0.000 17.550 168.000 ;
    LAYER MET4 ;
    RECT 17.550 0.650 17.850 167.350 ;
    LAYER MET4 ;
    RECT 17.850 0.000 17.950 168.000 ;
    LAYER MET4 ;
    RECT 17.950 0.650 18.250 167.350 ;
    LAYER MET4 ;
    RECT 18.250 0.000 18.350 168.000 ;
    LAYER MET4 ;
    RECT 18.350 0.650 18.650 167.350 ;
    LAYER MET4 ;
    RECT 18.650 0.000 18.750 168.000 ;
    LAYER MET4 ;
    RECT 18.750 0.650 19.050 167.350 ;
    LAYER MET4 ;
    RECT 19.050 0.000 20.750 168.000 ;
    LAYER MET4 ;
    RECT 20.750 0.650 21.050 167.350 ;
    LAYER MET4 ;
    RECT 21.050 0.000 21.150 168.000 ;
    LAYER MET4 ;
    RECT 21.150 0.650 21.450 167.350 ;
    LAYER MET4 ;
    RECT 21.450 0.000 21.550 168.000 ;
    LAYER MET4 ;
    RECT 21.550 0.650 21.850 167.350 ;
    LAYER MET4 ;
    RECT 21.850 0.000 21.950 168.000 ;
    LAYER MET4 ;
    RECT 21.950 0.650 22.250 167.350 ;
    LAYER MET4 ;
    RECT 22.250 0.000 22.350 168.000 ;
    LAYER MET4 ;
    RECT 22.350 0.650 22.650 167.350 ;
    LAYER MET4 ;
    RECT 22.650 0.000 22.750 168.000 ;
    LAYER MET4 ;
    RECT 22.750 0.650 23.050 167.350 ;
    LAYER MET4 ;
    RECT 23.050 0.000 23.150 168.000 ;
    LAYER MET4 ;
    RECT 23.150 0.650 23.450 167.350 ;
    LAYER MET4 ;
    RECT 23.450 0.000 23.550 168.000 ;
    LAYER MET4 ;
    RECT 23.550 0.650 23.850 167.350 ;
    LAYER MET4 ;
    RECT 23.850 0.000 23.950 168.000 ;
    LAYER MET4 ;
    RECT 23.950 0.650 24.250 167.350 ;
    LAYER MET4 ;
    RECT 24.250 0.000 24.350 168.000 ;
    LAYER MET4 ;
    RECT 24.350 0.650 24.650 167.350 ;
    LAYER MET4 ;
    RECT 24.650 0.000 24.750 168.000 ;
    LAYER MET4 ;
    RECT 24.750 0.650 25.050 167.350 ;
    LAYER MET4 ;
    RECT 25.050 0.000 25.150 168.000 ;
    LAYER MET4 ;
    RECT 25.150 0.650 25.450 167.350 ;
    LAYER MET4 ;
    RECT 25.450 0.000 25.550 168.000 ;
    LAYER MET4 ;
    RECT 25.550 0.650 25.850 167.350 ;
    LAYER MET4 ;
    RECT 25.850 0.000 25.950 168.000 ;
    LAYER MET4 ;
    RECT 25.950 0.650 26.250 167.350 ;
    LAYER MET4 ;
    RECT 26.250 0.000 26.350 168.000 ;
    LAYER MET4 ;
    RECT 26.350 0.650 26.650 167.350 ;
    LAYER MET4 ;
    RECT 26.650 0.000 26.750 168.000 ;
    LAYER MET4 ;
    RECT 26.750 0.650 27.050 167.350 ;
    LAYER MET4 ;
    RECT 27.050 0.000 27.150 168.000 ;
    LAYER MET4 ;
    RECT 27.150 0.650 27.450 167.350 ;
    LAYER MET4 ;
    RECT 27.450 0.000 29.150 168.000 ;
    LAYER MET4 ;
    RECT 29.150 0.650 29.450 167.350 ;
    LAYER MET4 ;
    RECT 29.450 0.000 29.550 168.000 ;
    LAYER MET4 ;
    RECT 29.550 0.650 29.850 167.350 ;
    LAYER MET4 ;
    RECT 29.850 0.000 29.950 168.000 ;
    LAYER MET4 ;
    RECT 29.950 0.650 30.250 167.350 ;
    LAYER MET4 ;
    RECT 30.250 0.000 30.350 168.000 ;
    LAYER MET4 ;
    RECT 30.350 0.650 30.650 167.350 ;
    LAYER MET4 ;
    RECT 30.650 0.000 30.750 168.000 ;
    LAYER MET4 ;
    RECT 30.750 0.650 31.050 167.350 ;
    LAYER MET4 ;
    RECT 31.050 0.000 31.150 168.000 ;
    LAYER MET4 ;
    RECT 31.150 0.650 31.450 167.350 ;
    LAYER MET4 ;
    RECT 31.450 0.000 31.550 168.000 ;
    LAYER MET4 ;
    RECT 31.550 0.650 31.850 167.350 ;
    LAYER MET4 ;
    RECT 31.850 0.000 31.950 168.000 ;
    LAYER MET4 ;
    RECT 31.950 0.650 32.250 167.350 ;
    LAYER MET4 ;
    RECT 32.250 0.000 32.350 168.000 ;
    LAYER MET4 ;
    RECT 32.350 0.650 32.650 167.350 ;
    LAYER MET4 ;
    RECT 32.650 0.000 32.750 168.000 ;
    LAYER MET4 ;
    RECT 32.750 0.650 33.050 167.350 ;
    LAYER MET4 ;
    RECT 33.050 0.000 33.150 168.000 ;
    LAYER MET4 ;
    RECT 33.150 0.650 33.450 167.350 ;
    LAYER MET4 ;
    RECT 33.450 0.000 33.550 168.000 ;
    LAYER MET4 ;
    RECT 33.550 0.650 33.850 167.350 ;
    LAYER MET4 ;
    RECT 33.850 0.000 33.950 168.000 ;
    LAYER MET4 ;
    RECT 33.950 0.650 34.250 167.350 ;
    LAYER MET4 ;
    RECT 34.250 0.000 34.350 168.000 ;
    LAYER MET4 ;
    RECT 34.350 0.650 34.650 167.350 ;
    LAYER MET4 ;
    RECT 34.650 0.000 34.750 168.000 ;
    LAYER MET4 ;
    RECT 34.750 0.650 35.050 167.350 ;
    LAYER MET4 ;
    RECT 35.050 0.000 35.150 168.000 ;
    LAYER MET4 ;
    RECT 35.150 0.650 35.450 167.350 ;
    LAYER MET4 ;
    RECT 35.450 0.000 35.550 168.000 ;
    LAYER MET4 ;
    RECT 35.550 0.650 35.850 167.350 ;
    LAYER MET4 ;
    RECT 35.850 0.000 37.550 168.000 ;
    LAYER MET4 ;
    RECT 37.550 0.650 37.850 167.350 ;
    LAYER MET4 ;
    RECT 37.850 0.000 37.950 168.000 ;
    LAYER MET4 ;
    RECT 37.950 0.650 38.250 167.350 ;
    LAYER MET4 ;
    RECT 38.250 0.000 38.350 168.000 ;
    LAYER MET4 ;
    RECT 38.350 0.650 38.650 167.350 ;
    LAYER MET4 ;
    RECT 38.650 0.000 38.750 168.000 ;
    LAYER MET4 ;
    RECT 38.750 0.650 39.050 167.350 ;
    LAYER MET4 ;
    RECT 39.050 0.000 39.150 168.000 ;
    LAYER MET4 ;
    RECT 39.150 0.650 39.450 167.350 ;
    LAYER MET4 ;
    RECT 39.450 0.000 39.550 168.000 ;
    LAYER MET4 ;
    RECT 39.550 0.650 39.850 167.350 ;
    LAYER MET4 ;
    RECT 39.850 0.000 39.950 168.000 ;
    LAYER MET4 ;
    RECT 39.950 0.650 40.250 167.350 ;
    LAYER MET4 ;
    RECT 40.250 0.000 40.350 168.000 ;
    LAYER MET4 ;
    RECT 40.350 0.650 40.650 167.350 ;
    LAYER MET4 ;
    RECT 40.650 0.000 40.750 168.000 ;
    LAYER MET4 ;
    RECT 40.750 0.650 41.050 167.350 ;
    LAYER MET4 ;
    RECT 41.050 0.000 41.150 168.000 ;
    LAYER MET4 ;
    RECT 41.150 0.650 41.450 167.350 ;
    LAYER MET4 ;
    RECT 41.450 0.000 41.550 168.000 ;
    LAYER MET4 ;
    RECT 41.550 0.650 41.850 167.350 ;
    LAYER MET4 ;
    RECT 41.850 0.000 41.950 168.000 ;
    LAYER MET4 ;
    RECT 41.950 0.650 42.250 167.350 ;
    LAYER MET4 ;
    RECT 42.250 0.000 42.350 168.000 ;
    LAYER MET4 ;
    RECT 42.350 0.650 42.650 167.350 ;
    LAYER MET4 ;
    RECT 42.650 0.000 42.750 168.000 ;
    LAYER MET4 ;
    RECT 42.750 0.650 43.050 167.350 ;
    LAYER MET4 ;
    RECT 43.050 0.000 43.150 168.000 ;
    LAYER MET4 ;
    RECT 43.150 0.650 43.450 167.350 ;
    LAYER MET4 ;
    RECT 43.450 0.000 43.550 168.000 ;
    LAYER MET4 ;
    RECT 43.550 0.650 43.850 167.350 ;
    LAYER MET4 ;
    RECT 43.850 0.000 43.950 168.000 ;
    LAYER MET4 ;
    RECT 43.950 0.650 44.250 167.350 ;
    LAYER MET4 ;
    RECT 44.250 0.000 45.950 168.000 ;
    LAYER MET4 ;
    RECT 45.950 0.650 46.250 167.350 ;
    LAYER MET4 ;
    RECT 46.250 0.000 46.350 168.000 ;
    LAYER MET4 ;
    RECT 46.350 0.650 46.650 167.350 ;
    LAYER MET4 ;
    RECT 46.650 0.000 46.750 168.000 ;
    LAYER MET4 ;
    RECT 46.750 0.650 47.050 167.350 ;
    LAYER MET4 ;
    RECT 47.050 0.000 47.150 168.000 ;
    LAYER MET4 ;
    RECT 47.150 0.650 47.450 167.350 ;
    LAYER MET4 ;
    RECT 47.450 0.000 47.550 168.000 ;
    LAYER MET4 ;
    RECT 47.550 0.650 47.850 167.350 ;
    LAYER MET4 ;
    RECT 47.850 0.000 47.950 168.000 ;
    LAYER MET4 ;
    RECT 47.950 0.650 48.250 167.350 ;
    LAYER MET4 ;
    RECT 48.250 0.000 48.350 168.000 ;
    LAYER MET4 ;
    RECT 48.350 0.650 48.650 167.350 ;
    LAYER MET4 ;
    RECT 48.650 0.000 48.750 168.000 ;
    LAYER MET4 ;
    RECT 48.750 0.650 49.050 167.350 ;
    LAYER MET4 ;
    RECT 49.050 0.000 49.150 168.000 ;
    LAYER MET4 ;
    RECT 49.150 0.650 49.450 167.350 ;
    LAYER MET4 ;
    RECT 49.450 0.000 49.550 168.000 ;
    LAYER MET4 ;
    RECT 49.550 0.650 49.850 167.350 ;
    LAYER MET4 ;
    RECT 49.850 0.000 49.950 168.000 ;
    LAYER MET4 ;
    RECT 49.950 0.650 50.250 167.350 ;
    LAYER MET4 ;
    RECT 50.250 0.000 50.350 168.000 ;
    LAYER MET4 ;
    RECT 50.350 0.650 50.650 167.350 ;
    LAYER MET4 ;
    RECT 50.650 0.000 50.750 168.000 ;
    LAYER MET4 ;
    RECT 50.750 0.650 51.050 167.350 ;
    LAYER MET4 ;
    RECT 51.050 0.000 51.150 168.000 ;
    LAYER MET4 ;
    RECT 51.150 0.650 51.450 167.350 ;
    LAYER MET4 ;
    RECT 51.450 0.000 51.550 168.000 ;
    LAYER MET4 ;
    RECT 51.550 0.650 51.850 167.350 ;
    LAYER MET4 ;
    RECT 51.850 0.000 51.950 168.000 ;
    LAYER MET4 ;
    RECT 51.950 0.650 52.250 167.350 ;
    LAYER MET4 ;
    RECT 52.250 0.000 52.350 168.000 ;
    LAYER MET4 ;
    RECT 52.350 0.650 52.650 167.350 ;
    LAYER MET4 ;
    RECT 52.650 0.000 54.350 168.000 ;
    LAYER MET4 ;
    RECT 54.350 0.650 54.650 167.350 ;
    LAYER MET4 ;
    RECT 54.650 0.000 54.750 168.000 ;
    LAYER MET4 ;
    RECT 54.750 0.650 55.050 167.350 ;
    LAYER MET4 ;
    RECT 55.050 0.000 55.150 168.000 ;
    LAYER MET4 ;
    RECT 55.150 0.650 55.450 167.350 ;
    LAYER MET4 ;
    RECT 55.450 0.000 55.550 168.000 ;
    LAYER MET4 ;
    RECT 55.550 0.650 55.850 167.350 ;
    LAYER MET4 ;
    RECT 55.850 0.000 55.950 168.000 ;
    LAYER MET4 ;
    RECT 55.950 0.650 56.250 167.350 ;
    LAYER MET4 ;
    RECT 56.250 0.000 56.350 168.000 ;
    LAYER MET4 ;
    RECT 56.350 0.650 56.650 167.350 ;
    LAYER MET4 ;
    RECT 56.650 0.000 56.750 168.000 ;
    LAYER MET4 ;
    RECT 56.750 0.650 57.050 167.350 ;
    LAYER MET4 ;
    RECT 57.050 0.000 57.150 168.000 ;
    LAYER MET4 ;
    RECT 57.150 0.650 57.450 167.350 ;
    LAYER MET4 ;
    RECT 57.450 0.000 57.550 168.000 ;
    LAYER MET4 ;
    RECT 57.550 0.650 57.850 167.350 ;
    LAYER MET4 ;
    RECT 57.850 0.000 57.950 168.000 ;
    LAYER MET4 ;
    RECT 57.950 0.650 58.250 167.350 ;
    LAYER MET4 ;
    RECT 58.250 0.000 58.350 168.000 ;
    LAYER MET4 ;
    RECT 58.350 0.650 58.650 167.350 ;
    LAYER MET4 ;
    RECT 58.650 0.000 58.750 168.000 ;
    LAYER MET4 ;
    RECT 58.750 0.650 59.050 167.350 ;
    LAYER MET4 ;
    RECT 59.050 0.000 59.150 168.000 ;
    LAYER MET4 ;
    RECT 59.150 0.650 59.450 167.350 ;
    LAYER MET4 ;
    RECT 59.450 0.000 59.550 168.000 ;
    LAYER MET4 ;
    RECT 59.550 0.650 59.850 167.350 ;
    LAYER MET4 ;
    RECT 59.850 0.000 59.950 168.000 ;
    LAYER MET4 ;
    RECT 59.950 0.650 60.250 167.350 ;
    LAYER MET4 ;
    RECT 60.250 0.000 60.350 168.000 ;
    LAYER MET4 ;
    RECT 60.350 0.650 60.650 167.350 ;
    LAYER MET4 ;
    RECT 60.650 0.000 60.750 168.000 ;
    LAYER MET4 ;
    RECT 60.750 0.650 61.050 167.350 ;
    LAYER MET4 ;
    RECT 61.050 0.000 62.750 168.000 ;
    LAYER MET4 ;
    RECT 62.750 0.650 63.050 167.350 ;
    LAYER MET4 ;
    RECT 63.050 0.000 63.150 168.000 ;
    LAYER MET4 ;
    RECT 63.150 0.650 63.450 167.350 ;
    LAYER MET4 ;
    RECT 63.450 0.000 63.550 168.000 ;
    LAYER MET4 ;
    RECT 63.550 0.650 63.850 167.350 ;
    LAYER MET4 ;
    RECT 63.850 0.000 63.950 168.000 ;
    LAYER MET4 ;
    RECT 63.950 0.650 64.250 167.350 ;
    LAYER MET4 ;
    RECT 64.250 0.000 64.350 168.000 ;
    LAYER MET4 ;
    RECT 64.350 0.650 64.650 167.350 ;
    LAYER MET4 ;
    RECT 64.650 0.000 64.750 168.000 ;
    LAYER MET4 ;
    RECT 64.750 0.650 65.050 167.350 ;
    LAYER MET4 ;
    RECT 65.050 0.000 65.150 168.000 ;
    LAYER MET4 ;
    RECT 65.150 0.650 65.450 167.350 ;
    LAYER MET4 ;
    RECT 65.450 0.000 65.550 168.000 ;
    LAYER MET4 ;
    RECT 65.550 0.650 65.850 167.350 ;
    LAYER MET4 ;
    RECT 65.850 0.000 65.950 168.000 ;
    LAYER MET4 ;
    RECT 65.950 0.650 66.250 167.350 ;
    LAYER MET4 ;
    RECT 66.250 0.000 66.350 168.000 ;
    LAYER MET4 ;
    RECT 66.350 0.650 66.650 167.350 ;
    LAYER MET4 ;
    RECT 66.650 0.000 70.800 168.000 ;
    LAYER MET5 ;
    RECT 0.000 0.000 70.800 2.400 ;
    LAYER MET5 ;
    RECT 0.000 3.600 70.800 10.800 ;
    LAYER MET5 ;
    RECT 0.000 12.000 70.800 19.200 ;
    LAYER MET5 ;
    RECT 0.000 20.400 70.800 27.600 ;
    LAYER MET5 ;
    RECT 0.000 28.800 70.800 36.000 ;
    LAYER MET5 ;
    RECT 0.000 37.200 70.800 44.400 ;
    LAYER MET5 ;
    RECT 0.000 45.600 70.800 52.800 ;
    LAYER MET5 ;
    RECT 0.000 54.000 70.800 61.200 ;
    LAYER MET5 ;
    RECT 0.000 62.400 70.800 69.600 ;
    LAYER MET5 ;
    RECT 0.000 70.800 70.800 78.000 ;
    LAYER MET5 ;
    RECT 0.000 79.200 70.800 86.400 ;
    LAYER MET5 ;
    RECT 0.000 87.600 70.800 94.800 ;
    LAYER MET5 ;
    RECT 0.000 96.000 70.800 103.200 ;
    LAYER MET5 ;
    RECT 0.000 104.400 70.800 111.600 ;
    LAYER MET5 ;
    RECT 0.000 112.800 70.800 120.000 ;
    LAYER MET5 ;
    RECT 0.000 121.200 70.800 128.400 ;
    LAYER MET5 ;
    RECT 0.000 129.600 70.800 136.800 ;
    LAYER MET5 ;
    RECT 0.000 138.000 70.800 145.200 ;
    LAYER MET5 ;
    RECT 0.000 146.400 70.800 153.600 ;
    LAYER MET5 ;
    RECT 0.000 154.800 70.800 162.000 ;
    LAYER MET5 ;
    RECT 0.000 163.200 70.800 168.000 ;
  END

END MACC

END LIBRARY
